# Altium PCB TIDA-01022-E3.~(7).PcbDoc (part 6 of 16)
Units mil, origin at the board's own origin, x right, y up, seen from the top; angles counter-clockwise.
Board outline 6929.13 x 11614.17 mil, 12 copper layers (L1_Top Layer, L2_GND, L3_GND, L4_Signal Layer 1, L5_GND, L6_PWR, L7_GND/PWR, L8_PWR, L9_GND/PWR, L10_Signal Layer 2, L11_GND, L12_Bottom Layer), stack 64.6 mil thick; 1733 components, 993 nets, 5987 pads, 3555 vias.

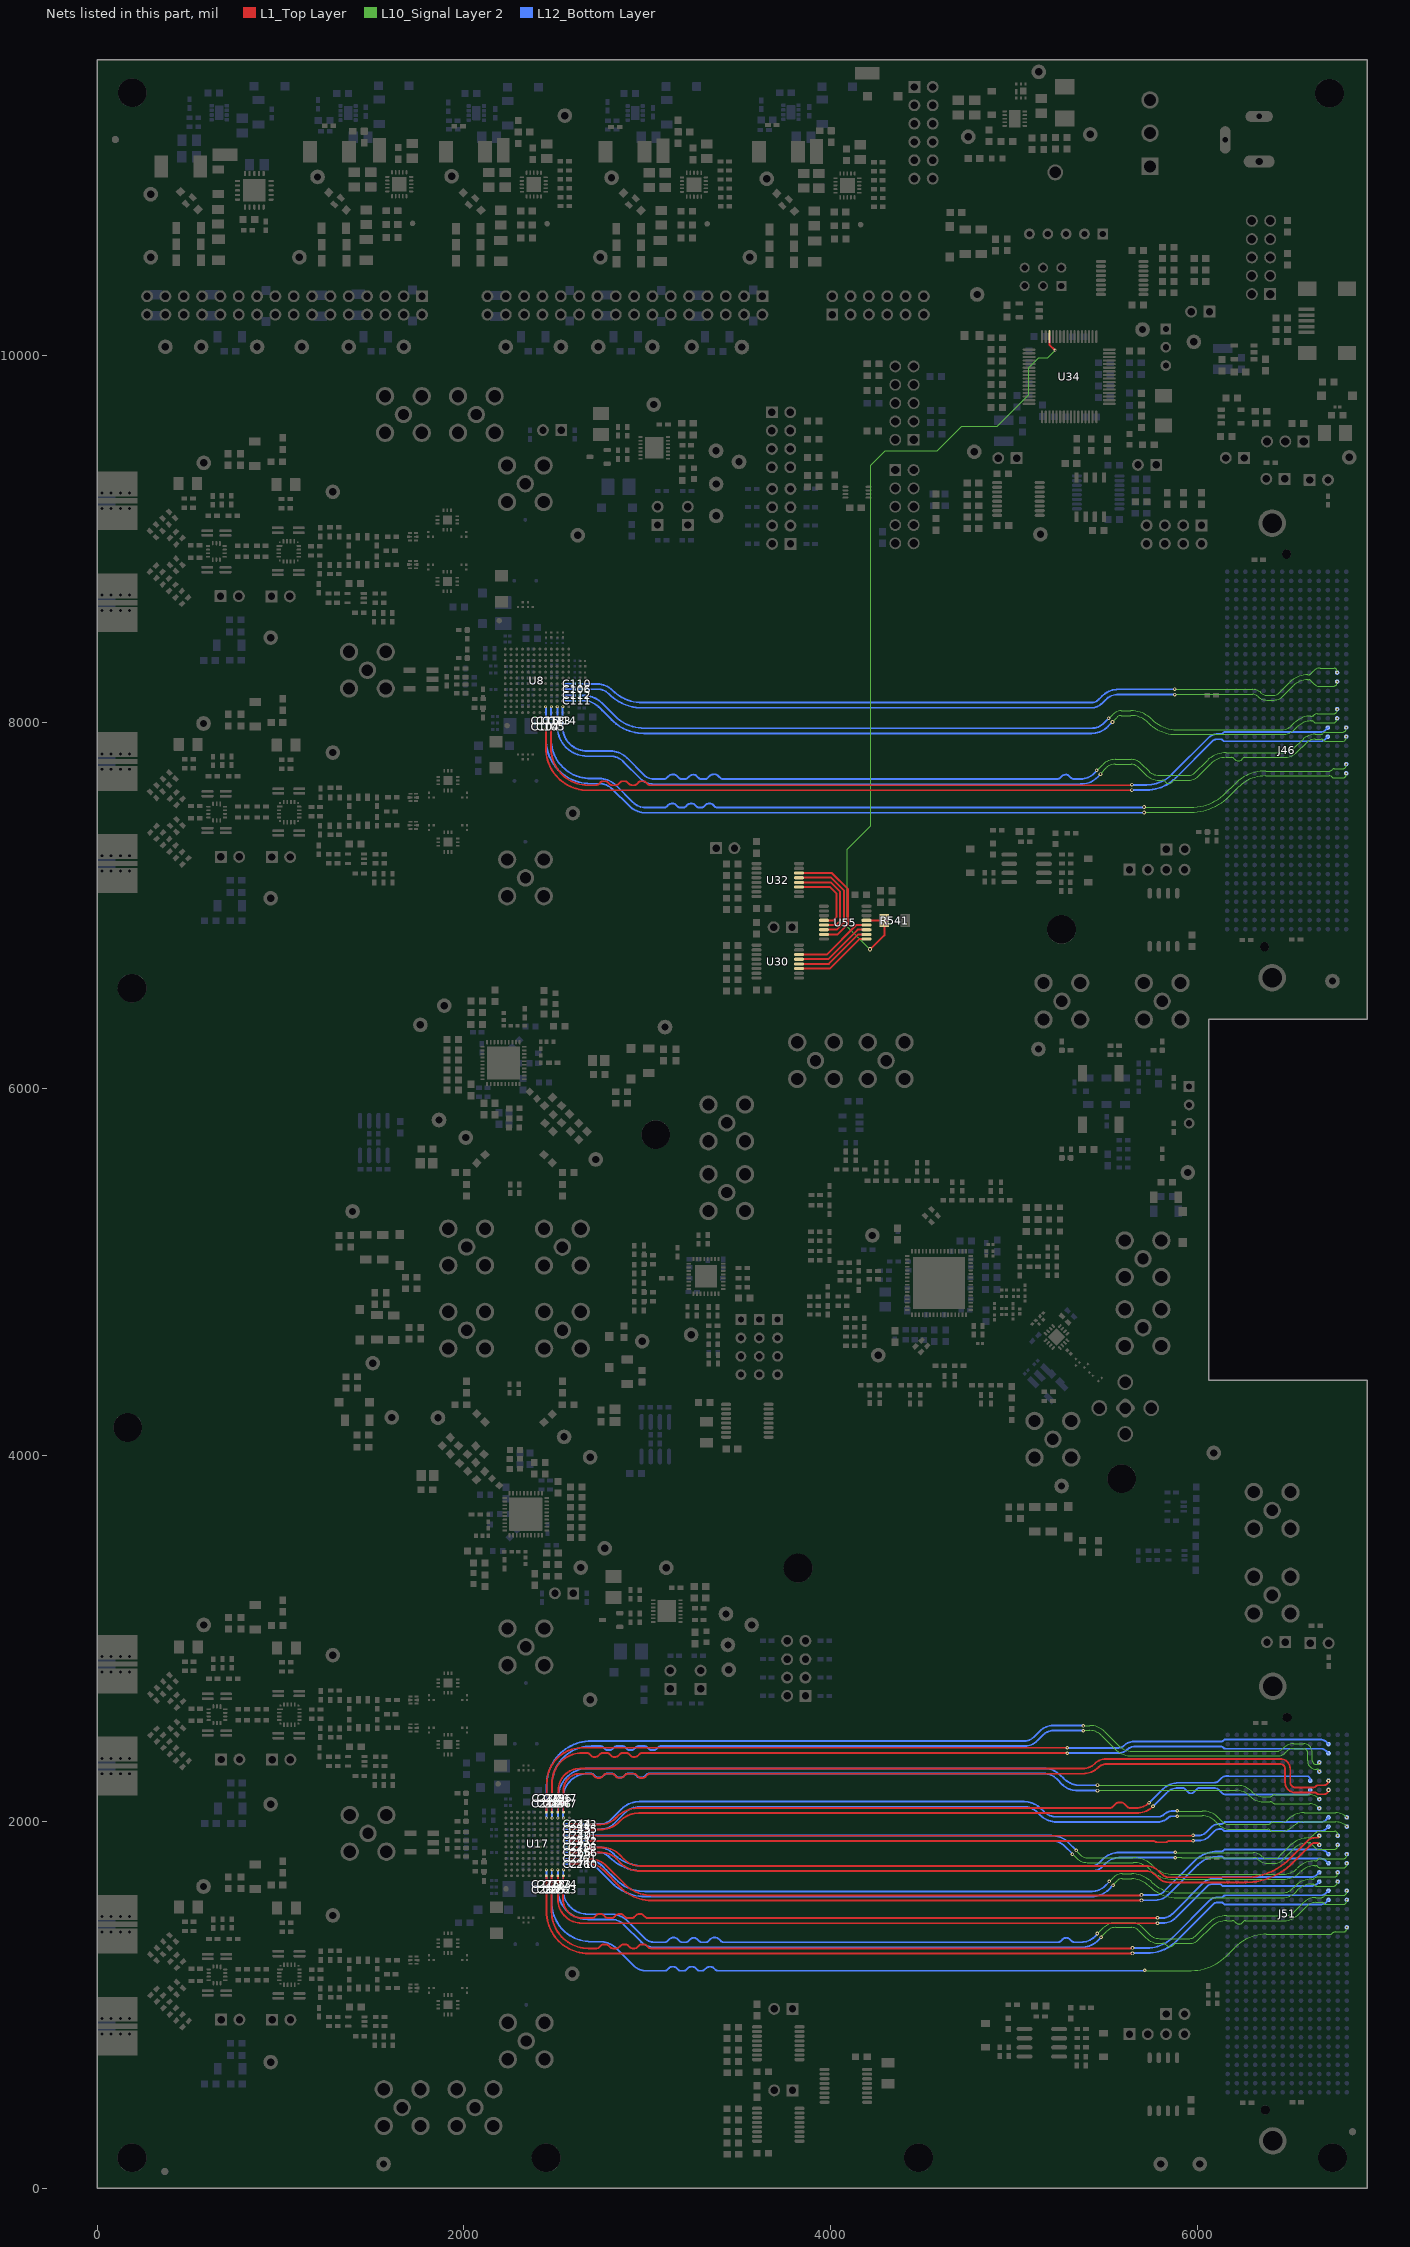
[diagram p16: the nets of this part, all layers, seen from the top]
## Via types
v1: diameter 16, hole 8, L1_Top Layer to L12_Bottom Layer, tented both sides, 1686 vias
v2: diameter 24, hole 12, L1_Top Layer to L12_Bottom Layer, tented both sides, 1590 vias
v3: diameter 20, hole 10, L1_Top Layer to L12_Bottom Layer, 279 vias

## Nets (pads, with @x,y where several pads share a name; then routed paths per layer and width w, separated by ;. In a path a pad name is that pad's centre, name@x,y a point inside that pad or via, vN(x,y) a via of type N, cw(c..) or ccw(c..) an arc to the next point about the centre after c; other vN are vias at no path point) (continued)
ADC1_DB3_M: C105.2 J46.A18 | length 4618.2
  L1_Top Layer w10: C105.2@2475.75,7961.28 2474.75,7960.28 2474.75,7856.77 ccw(c2675.85,7856.77) 2675.85,7655.67 2720.69,7655.67 ccw(c2720.69,7675.64) 2734.81,7661.52 2739.81,7666.52 2744.24,7670.96 cw(c2759.74,7655.46) 2759.74,7677.38 2770.91,7677.38 cw(c2770.91,7658.67) 2784.14,7671.9 2789.51,7666.53 2794.55,7661.48 ccw(c2808.58,7675.51) 2808.58,7655.67 2828.21,7655.67 ccw(c2828.21,7675.64) 2842.33,7661.52 2847.33,7666.52 2851.76,7670.96 cw(c2867.26,7655.46) 2867.26,7677.38 2878.43,7677.38 cw(c2878.43,7658.67) 2891.66,7671.9 2897.03,7666.53 2902.07,7661.48 ccw(c2916.1,7675.51) 2916.1,7655.67 2928.17,7655.67 ccw(c2928.17,7675.64) 2942.29,7661.52 2947.29,7666.52 2951.72,7670.96 cw(c2967.22,7655.46) 2967.22,7677.38 2978.39,7677.38 cw(c2978.39,7658.67) 2991.62,7671.9 2996.99,7666.53 3002.03,7661.48 ccw(c3016.06,7675.51) 3016.06,7655.67 v3@5643.74,7655.67
  L12_Bottom Layer w10: v3(5643.74,7658.4) 5644.74,7657.4 5724.33,7657.4 ccw(c5724.33,7852.38) 5862.19,7714.5 6064.69,7917.01 cw(c6105.74,7875.95) 6105.74,7934.01 6130.02,7934.01 ccw(c6130.02,7944) 6137.09,7936.94 6142.23,7942.08 cw(c6149.3,7935.02) 6149.3,7945.01 6672.48,7945.01 ccw(c6672.48,7982.74) 6699.16,7956.06 J46.A18@6713.11,7970.01
ADC1_DB3_P: C104.2 J46.A19 | length 4616.3
  L1_Top Layer w10: C104.2@2445.75,7961.28 2446.75,7960.28 2446.75,7856.77 ccw(c2675.85,7856.77) 2675.85,7627.67 v3@5641.81,7627.67
  L12_Bottom Layer w10: v3(5643.74,7628.4) 5644.74,7629.4 5724.33,7629.4 ccw(c5724.33,7852.38) 5882,7694.71 6084.49,7897.21 cw(c6105.74,7875.95) 6105.74,7906.01 6130.02,7906.01 cw(c6130.02,7896.02) 6137.09,7903.08 6142.23,7897.94 ccw(c6149.3,7905) 6149.3,7895.01 6669.06,7895.01 ccw(c6669.06,7941) 6701.58,7908.48 J46.A19@6713.11,7920.01
ADC1_DB4+: C106.1 U8.H11 | length 65.1
  L12_Bottom Layer w10: v1(2539.9,8177.85) 2541.65,8179.6 2602.91,8179.6 C106.1@2603.9,8178.61
ADC1_DB4-: C110.1 U8.G11 | length 65.1
  L12_Bottom Layer w10: v1(2539.9,8209.35) 2541.65,8207.6 2602.9,8207.6 C110.1@2603.9,8208.6
ADC1_DB4_M: C110.2 J46.Z12 | length 4261.4
  L10_Signal Layer 2 w6.3: v3(5877.5,8179.62) 5879.42,8177.7 6302.86,8177.7 cw(c6302.86,8111.32) 6349.78,8158.27 ccw(c6378.98,8187.44) 6378.96,8146.17 6418.51,8146.17 ccw(c6418.51,8184.8) 6445.83,8157.49 6505.46,8217.12 cw(c6603.86,8118.72) 6603.86,8257.88 6609.01,8257.88 ccw(c6609.01,8268.6) 6616.59,8261.02 6635,8279.43 cw(c6671.24,8243.2) 6671.24,8294.44 6746.74,8294.44 cw(c6746.74,8278.07) 6763.11,8278.07 v1(6763.11,8270.01)
  L12_Bottom Layer w10: C110.2@2629.88,8208.6 2631.11,8207.37 2727.5,8207.37 cw(c2727.49,8090.77) 2809.93,8173.22 ccw(c2972.65,8335.93) 2972.65,8105.82 4845.67,8105.82 ; 4845.68,8105.82 4887.67,8105.82 ; 4887.67,8105.82 5403.67,8105.82 5424.45,8105.82 ccw(c5424.45,8154.33) 5458.75,8120.03 ccw(c5416.88,8174.18) 5465.28,8125.78 5480.84,8141.34 cw(c5570.85,8051.33) 5570.85,8178.62 5876.5,8178.62 v3(5877.5,8179.62)
ADC1_DB4_P: C106.2 J46.Z13 | length 4262.5
  L10_Signal Layer 2 w6.3: v3(5877.5,8149.62) 5879.18,8151.3 6302.85,8151.3 cw(c6302.85,8111.32) 6331.12,8139.59 ccw(c6378.97,8187.44) 6378.97,8119.77 6418.51,8119.77 ccw(c6418.51,8184.81) 6464.5,8138.82 6524.13,8198.45 cw(c6603.87,8118.72) 6603.87,8231.48 6609.01,8231.48 cw(c6609.01,8219.94) 6617.17,8228.1 6639.06,8206.2 ccw(c6664.59,8231.74) 6664.59,8195.63 6745.03,8195.65 ccw(c6745.03,8213.73) 6763.11,8213.73 v1(6763.11,8220.01)
  L12_Bottom Layer w10: C106.2@2629.88,8178.61 2630.64,8179.37 2727.49,8179.37 cw(c2727.48,8090.77) 2790.13,8153.42 ccw(c2972.64,8335.93) 2972.64,8077.82 4887.67,8077.82 ; 4887.67,8077.82 5403.67,8077.82 5424.45,8077.82 ccw(c5424.45,8154.33) 5477.24,8098.95 ; 5478.55,8100.23 cw(c5424.45,8154.33) 5477.24,8098.95 ; v3(5877.5,8149.62) 5876.5,8150.62 5570.85,8150.62 ccw(c5570.85,8051.33) 5500.64,8121.54 5485.08,8105.98 cw(c5416.88,8174.18) 5477.24,8098.95
ADC1_DB5+: C111.1 U8.K11 | length 65.1
  L12_Bottom Layer w10: v1(2539.9,8114.86) 2541.65,8116.6 2602.91,8116.6 C111.1@2603.9,8115.61
ADC1_DB5-: C112.1 U8.J11 | length 65.1
  L12_Bottom Layer w10: v1(2539.9,8146.35) 2541.65,8144.6 2602.9,8144.6 C112.1@2603.9,8145.6
ADC1_DB5_M: C112.2 J46.Z16 | length 4295.2
  L10_Signal Layer 2 w6.3: v3(5516.96,8021.06) 5519.5,8021.06 5541.59,8043.15 cw(c5586.84,7997.9) 5586.83,8061.89 5638.45,8061.89 cw(c5638.48,7900.69) 5752.46,8014.68 ccw(c5887.41,8149.63) 5887.4,7958.78 6462.43,7958.78 ccw(c6462.43,8035.32) 6516.55,7981.2 6530.77,7995.42 cw(c6620.45,7905.73) 6620.45,8032.56 6625.27,8032.56 ccw(c6625.27,8048.57) 6636.59,8037.25 6636.7,8037.36 cw(c6655.17,8018.89) 6655.17,8045.01 6744.96,8045.01 ccw(c6744.96,8063.16) 6763.11,8063.16 v1(6763.11,8070.01)
  L12_Bottom Layer w10: C112.2@2629.88,8145.6 2630.88,8144.6 2652.49,8144.6 cw(c2652.49,8001.01) 2754.02,8102.55 2773.33,8083.24 2813.19,8043.37 2825.12,8031.44 ccw(c2982.5,8188.82) 2982.5,7966.25 4885.07,7966.25 ; 4885.07,7966.26 5422.75,7966.26 ccw(c5422.75,8066.26) 5493.46,7995.55 5515.54,8017.63 ccw(c5512.1,8021.06) v3(5516.96,8021.06)
ADC1_DB5_P: C111.2 J46.Z17 | length 4293.4
  L10_Signal Layer 2 w6.3: v3(5538.18,7999.84) 5538.18,8002.4 5560.26,8024.48 cw(c5586.84,7997.9) 5586.84,8035.49 5638.48,8035.49 cw(c5638.48,7900.69) 5733.79,7996.01 ccw(c5887.41,8149.63) 5887.39,7932.38 6462.43,7932.38 ccw(c6462.43,8035.32) 6535.22,7962.53 6549.44,7976.75 cw(c6620.45,7905.73) 6620.45,8006.16 6625.27,8006.16 cw(c6625.27,7991.36) 6635.74,8001.82 6640.3,7997.26 ccw(c6645.73,8002.69) 6645.73,7995.01 6740.88,7995.01 ccw(c6740.88,8017.24) 6763.11,8017.24 v1(6763.11,8020.01)
  L12_Bottom Layer w10: C111.2@2630.87,8116.6 2652.49,8116.6 cw(c2652.49,8001.01) 2734.22,8082.75 2753.53,8063.44 ; 2753.53,8063.43 2805.32,8011.64 ccw(c2982.5,8188.82) 2982.49,7938.25 4896.66,7938.25 5422.75,7938.26 ccw(c5422.75,8066.26) 5513.26,7975.75 5536.76,7999.25 cw(c5538.18,7997.83) v3(5538.18,7999.84)
ADC1_DB6+: C113.1 U8.L10 | length 65.1
  L12_Bottom Layer w10: v1(2508.4,8083.36) 2510.15,8081.62 2510.15,8020.35 C113.1@2509.16,8019.36
ADC1_DB6-: C114.1 U8.L11 | length 65.1
  L12_Bottom Layer w10: C114.1@2539.15,8019.36 2538.15,8020.36 2538.15,8081.61 v1(2539.9,8083.36)
ADC1_DB6_M: C114.2 J46.Y18 | length 4654.8
  L10_Signal Layer 2 w6.3: v3(5451.47,7737.01) 5454.01,7737.01 5485.04,7768.04 cw(c5552.57,7700.51) 5552.56,7796.01 5640.45,7796.01 cw(c5640.45,7719.77) 5694.36,7773.68 5735.02,7733.02 ccw(c5792.79,7790.79) 5792.79,7709.09 5880.37,7709.09 ; 5880.82,7709.09 5900.73,7709.09 ccw(c5900.6,7836.94) 5908.59,7709.34 5908.63,7709.38 5955.02,7709.38 ccw(c5955.02,7755.29) 5987.49,7722.83 6054.75,7790.09 cw(c6158.44,7686.39) 6158.46,7833.04 6472.07,7833.04 ccw(c6472.06,7911.05) 6527.22,7855.89 6575.47,7904.14 cw(c6644.11,7835.5) 6644.1,7932.57 6674.25,7932.57 ccw(c6674.25,7947.85) 6685.05,7937.04 ; 6686.71,7938.7 cw(c6701.94,7923.47) 6701.94,7945.01 6794.96,7945.01 ccw(c6794.96,7963.16) 6813.11,7963.16 v1(6813.11,7970.01)
  L12_Bottom Layer w10: C114.2@2538.16,7994.37 2537.16,7993.37 2537.16,7976.66 ccw(c2671.95,7976.66) 2671.95,7841.87 2798.71,7841.87 cw(c2798.71,7713.87) 2889.22,7804.38 2982.8,7710.8 ccw(c3035.17,7763.17) 3035.17,7689.11 3092,7689.11 ccw(c3092,7709.08) 3106.12,7694.96 3111.12,7699.96 3115.55,7704.4 cw(c3140.13,7679.81) 3140.13,7714.58 cw(c3140.14,7683.03) 3162.45,7705.34 3167.82,7699.97 3172.86,7694.92 ccw(c3186.89,7708.95) 3186.89,7689.11 3206.36,7689.11 ccw(c3206.36,7709.08) 3220.48,7694.96 3225.48,7699.96 3229.9,7704.39 cw(c3251,7683.3) 3250.99,7713.13 cw(c3251,7686.53) 3269.81,7705.34 3275.18,7699.97 3280.22,7694.92 ccw(c3294.25,7708.95) 3294.25,7689.11 3318.9,7689.11 ccw(c3318.9,7699.13) 3325.98,7692.04 3333.9,7699.96 3338.33,7704.4 cw(c3364.4,7678.33) 3364.4,7715.2 ; 3364.42,7715.2 cw(c3364.42,7681.52) 3388.23,7705.34 3393.6,7699.97 3398.64,7694.92 ccw(c3412.67,7708.95) 3412.67,7689.11 4885.07,7689.11 ; 4885.07,7689.11 4890.87,7689.11 4908.27,7689.11 5238.05,7689.11 5238.05,7689.27 ccw(c5238.05,7709.24) 5252.17,7695.12 5257.17,7700.12 5261.6,7704.56 cw(c5282.68,7683.48) 5282.68,7713.29 cw(c5282.69,7686.69) 5301.5,7705.5 5306.87,7700.13 5311.91,7695.08 ccw(c5325.94,7709.11) 5325.94,7689.27 ; 5324.09,7689.11 5324.24,7689.27 5325.94,7689.27 ; 5327.09,7689.11 5326.93,7689.27 ; v3(5451.47,7737.01) 5451.47,7733.53 5437.82,7719.88 cw(c5363.92,7793.78) 5363.92,7689.27 5326.93,7689.27 ; 5325.94,7689.27 5326.93,7689.27
ADC1_DB6_P: C113.2 J46.Y19 | length 4652.8
  L10_Signal Layer 2 w6.3: v3(5472.69,7715.79) 5472.69,7718.35 5503.71,7749.37 cw(c5552.57,7700.51) 5552.57,7769.61 5640.45,7769.61 cw(c5640.45,7719.77) 5675.69,7755.01 5716.35,7714.35 ccw(c5792.79,7790.8) 5792.79,7682.69 5810.15,7682.69 cw(c5810.15,7663.67) 5823.6,7677.12 5829.51,7671.21 ; 5829.53,7671.21 ccw(c5844.87,7687.11) 5844.85,7665.02 ccw(c5844.86,7694.57) 5865.76,7673.68 5870.49,7678.41 cw(c5880.82,7668.08) 5880.82,7682.69 5900.72,7682.69 ccw(c5900.75,7836.94) 5910.2,7682.98 5955.03,7682.98 ccw(c5955.03,7755.29) 6006.16,7704.16 6073.42,7771.42 cw(c6158.45,7686.39) 6158.45,7806.64 6189.14,7806.64 cw(c6189.14,7787.62) 6202.59,7801.07 6208.5,7795.16 6208.77,7794.9 ccw(c6224.4,7810.52) 6224.4,7788.42 6225.77,7788.42 ccw(c6225.77,7812.01) 6242.45,7795.33 6249.8,7802.68 cw(c6259.36,7793.12) 6259.36,7806.64 6472.06,7806.64 ccw(c6472.06,7911.05) 6545.89,7837.22 6594.14,7885.47 cw(c6644.11,7835.5) 6644.11,7906.17 6675.78,7906.17 cw(c6675.78,7887.53) 6688.96,7900.71 ccw(c6702.72,7914.47) 6702.72,7895.01 6791.29,7895.01 ccw(c6791.29,7916.83) 6813.11,7916.83 v1(6813.11,7920.01)
  L12_Bottom Layer w10: C113.2@2508.17,7994.37 C113.2@2509.16,7993.38 2509.16,7976.66 ccw(c2671.95,7976.66) 2671.95,7813.87 2798.71,7813.87 cw(c2798.71,7713.87) 2869.42,7784.58 2963,7691 ccw(c3035.17,7763.17) 3035.17,7661.11 4874.67,7661.11 ; 4874.68,7661.11 5362.96,7661.11 ; 5363.91,7661.27 ccw(c5363.92,7793.78) 5457.62,7700.08 5471.59,7714.05 v3@5472.69,7714.05
ADC1_DB7+: C115.1 U8.L8 | length 65.1
  L12_Bottom Layer w10: v1(2445.41,8083.36) 2447.16,8081.62 2447.16,8020.35 C115.1@2446.17,8019.36
ADC1_DB7-: C118.1 U8.L9 | length 65.1
  L12_Bottom Layer w10: C118.1@2476.16,8019.36 2475.16,8020.36 2475.16,8081.61 v1(2476.91,8083.36)
ADC1_DB7_M: C118.2 J46.Y22 | length 4730.5
  L10_Signal Layer 2 w6.3: v3(5710.46,7536.14) 5712.26,7534.34 5964.92,7534.34 ccw(c5964.92,7803.56) 6155.29,7613.2 6204.1,7662 cw(c6374.33,7491.77) 6374.32,7732.51 6722.02,7732.51 ccw(c6722.02,7749.55) 6734.07,7737.5 6736.55,7739.98 cw(c6748.7,7727.82) 6748.7,7745.01 6794.96,7745.01 ccw(c6794.96,7763.16) 6813.11,7763.16 v1(6813.11,7770.01)
  L12_Bottom Layer w10: C118.2@2476,7993.99 2475.77,7993.76 2475,7992.99 2475,7906.98 ccw(c2690.2,7906.98) 2690.2,7691.78 2738.8,7691.78 cw(c2738.8,7563.78) 2829.31,7654.29 2921.19,7562.41 ccw(c2991.9,7633.12) 2991.9,7533.12 3092,7533.12 ccw(c3092,7553.09) 3106.12,7538.97 3111.12,7543.97 3115.55,7548.41 cw(c3131.05,7532.91) 3131.05,7554.83 3142.22,7554.83 cw(c3142.22,7536.12) 3155.45,7549.35 3160.82,7543.98 3165.86,7538.93 ccw(c3179.89,7552.96) 3179.89,7533.12 3195.52,7533.12 ccw(c3195.52,7553.09) 3209.64,7538.97 3214.64,7543.97 3219.07,7548.41 cw(c3234.57,7532.91) 3234.57,7554.83 3245.74,7554.83 cw(c3245.74,7536.12) 3258.97,7549.35 3264.34,7543.98 3269.38,7538.93 ccw(c3283.41,7552.96) 3283.41,7533.12 3294.57,7533.12 ccw(c3294.57,7553.09) 3308.69,7538.97 3313.69,7543.97 3318.12,7548.41 cw(c3333.62,7532.91) 3333.62,7554.83 3344.79,7554.83 cw(c3344.79,7536.12) 3358.02,7549.35 3363.39,7543.98 3368.43,7538.93 ccw(c3382.46,7552.96) 3382.46,7533.12 4884.95,7533.12 4885.07,7533.24 5703.47,7533.24 ccw(c5703.47,7543.13) v3(5710.46,7536.14)
ADC1_DB7_P: C115.2 J46.Y23 | length 4728
  L10_Signal Layer 2 w6.3: v3(5710.46,7506.14) 5712.26,7507.94 5964.93,7507.94 ccw(c5964.92,7803.56) 6173.96,7594.53 6222.77,7643.33 cw(c6374.33,7491.77) 6374.33,7706.11 6434.9,7706.11 6662.33,7706.1 6720.74,7706.1 cw(c6720.74,7684.28) 6736.17,7699.71 ccw(c6747.52,7711.06) 6747.52,7695.01 6794.96,7695.01 ccw(c6794.96,7713.16) 6813.11,7713.16 v1(6813.11,7720.01)
  L12_Bottom Layer w10: C115.2@2447,7993 2447,7906.98 ccw(c2690.2,7906.98) 2690.2,7663.78 2738.8,7663.78 cw(c2738.8,7563.78) 2809.51,7634.49 2901.39,7542.61 ccw(c2991.9,7633.12) 2991.9,7505.12 4896.54,7505.12 4896.67,7505.24 v3@5710.46,7505.24
ADC1_NCOA0: U30.3 U55.9 | length 435.1
  L1_Top Layer w11: U30.3@3827.61,6654.83 3996.01,6654.83 4157.12,6815.95 U55.9@4195.96,6815.95
ADC1_NCOA1: U30.4 U55.10 | length 435.1
  L1_Top Layer w11: U30.4@3827.61,6680.42 3990.6,6680.42 4151.71,6841.54 U55.10@4195.96,6841.54
ADC1_NCOB0: U30.5 U55.11 | length 435.1
  L1_Top Layer w11: U30.5@3827.61,6706.01 3986.19,6706.01 4147.3,6867.13 U55.11@4195.96,6867.13
ADC1_NCOB1: U30.6 U55.12 | length 435.1
  L1_Top Layer w11: U30.6@3827.61,6731.61 3978.78,6731.61 4139.89,6892.72 U55.12@4195.96,6892.72
ADC1_OVRA0: U32.3 U55.4 | length 424.5
  L1_Top Layer w11: U32.3@3827.61,7099.54 3997.15,7099.54 4033.43,7063.26 4033.43,6937.08 4014.65,6918.31 U55.4@3963.68,6918.31
ADC1_OVRA1: U32.4 U55.5 | length 502.5
  L1_Top Layer w11: U32.4@3827.61,7125.13 4000.55,7125.13 4052.43,7073.26 4052.43,6915.08 4030.06,6892.72 U55.5@3963.68,6892.72
ADC1_OVRB0: U32.5 U55.6 | length 573.9
  L1_Top Layer w11: U32.5@3827.61,7150.72 4002.96,7150.72 4072.07,7081.62 4072.07,6904.73 4034.47,6867.13 U55.6@3963.68,6867.13
ADC1_OVRB1: U32.6 U55.7 | length 648.3
  L1_Top Layer w11: U32.6@3827.61,7176.31 4007.48,7176.31 4093.68,7090.12 4093.68,6896.33 4038.88,6841.54 U55.7@3963.68,6841.54
ADC1_STS: R541.1 U34.30 U55.13 | length 4473.6
  L1_Top Layer w11: U55.13@4195.96,6918.31 4291.6,6918.31 R541.1@4292.91,6917 4292.91,6835.91 4217,6760 v2(4215,6760) ; U34.30@5193.62,10102.47 5193.62,10059.13 5224.31,10028.44 v1(5225.31,10029.44)
  L10_Signal Layer 2 w6.5: v2(4215,6760) 4091,6884 4091,7306 4218.5,7433.5 4218.5,9400.5 4298,9480 4583,9480 4716,9613 4908,9613 5082,9787 5082,9933 5137,9988 5183.87,9988 v1(5225.31,10029.44)
ADC2_DA0+: C231.1 U17.E12 | length 64.5
  L1_Top Layer w10: U17.E12@2574.72,1926.34 2576.88,1924.18 C231.1@2638.33,1924.18
ADC2_DA0-: C232.1 U17.F12 | length 65.6
  L1_Top Layer w10: U17.F12@2574.72,1894.85 2576.06,1896.18 2638.33,1896.18 C232.1@2639.33,1895.18
ADC2_DA0_M: C232.2 J51.A11 | length 4087.4
  L1_Top Layer w10: C232.2@2666.3,1896.18 5045.6,1896.18 5758.86,1896.19 cw(c5758.86,1874.49) 5768.78,1893.79 ccw(c5780.57,1905.58) 5773.56,1890.45 ccw(c5780.57,1905.58) 5780.57,1888.91 5830.59,1888.91 ccw(c5830.59,1901.72) 5839.66,1892.66 cw(c5848.18,1884.14) 5848.18,1896.19 v3@5977.92,1896.19
  L12_Bottom Layer w10: v3(5977.92,1896.5) 5978.92,1897.5 6009.17,1897.5 ccw(c6009.17,1978.74) 6066.6,1921.28 6096.67,1951.33 cw(c6117.62,1930.39) 6117.61,1960.01 6133.35,1960.01 cw(c6133.35,1950.02) 6140.42,1957.08 6145.56,1951.94 ccw(c6152.63,1959) 6152.63,1949.01 6672.39,1949.01 ccw(c6672.39,1995) 6700.63,1958.71 ccw(c6672.39,1995) 6704.91,1962.48 J51.A11@6716.44,1974.01
ADC2_DA0_P: C231.2 J51.A10 | length 4093.2
  L1_Top Layer w10: C231.2@2664.31,1924.18 5034,1924.18 v3@5972.34,1924.19 ; v3@5972.34,1924.19 ccw(c5972.34,1932.08) v3(5977.92,1926.5) 5975.61,1924.19 v3@5972.34,1924.19
  L12_Bottom Layer w10: v3(5977.92,1926.5) 5978.92,1925.5 6009.17,1925.5 ccw(c6009.17,1978.73) 6046.8,1941.08 6076.87,1971.13 cw(c6117.62,1930.39) 6117.6,1988.01 6133.35,1988.01 ccw(c6133.35,1998) 6140.42,1990.94 6145.56,1996.08 cw(c6152.63,1989.02) 6152.63,1999.01 6675.81,1999.01 ccw(c6675.81,2036.74) 6702.49,2010.06 J51.A10@6716.44,2024.01
ADC2_DA1+: C233.1 U17.C12 | length 64.5
  L1_Top Layer w10: U17.C12@2574.72,1989.33 2576.88,1987.18 C233.1@2638.33,1987.18
ADC2_DA1-: C235.1 U17.D12 | length 65.6
  L1_Top Layer w10: U17.D12@2574.72,1957.84 2576.06,1959.18 2638.33,1959.18 C235.1@2639.33,1958.18
ADC2_DA1_M: C235.2 J51.C7 | length 4073.9
  L1_Top Layer w10: C235.2@2665.31,1958.18 2714.14,1958.17 2745.78,1958.17 ccw(c2745.78,2101.65) 2847.23,2000.19 2852.78,2005.74 cw(c2953.98,1904.54) 2953.98,2047.66 5670.11,2047.66 ccw(c5670.12,2173.78) v3(5759.3,2084.6)
  L12_Bottom Layer w10: v3(5759.3,2084.6) 5832.96,2158.25 cw(c5897.85,2093.37) 5897.84,2185.13 5920.34,2185.13 cw(c5920.34,2167) 5933.16,2179.82 5952.05,2160.93 ccw(c5963.85,2172.75) 5963.84,2156.05 5968.62,2156.04 ccw(c5968.65,2172.68) 5980.41,2160.91 5999.83,2180.33 cw(c6011.42,2168.74) 6011.42,2185.13 6092.11,2185.13 cw(c6092.11,2147.68) 6118.59,2174.16 6134.47,2158.28 ccw(c6157.07,2180.88) 6157.07,2148.92 6170.78,2148.92 6563.35,2149.01 6598.54,2149.01 ccw(c6598.54,2166.91) 6616.44,2166.91 J51.C7@6616.44,2174.01
ADC2_DA1_P: C233.2 J51.C6 | length 4078
  L1_Top Layer w10: C233.2@2664.31,1987.18 ccw(c2666.74,1989.6) 2666.74,1986.17 2714.14,1986.17 2745.78,1986.17 ccw(c2745.78,2101.64) 2827.43,2019.99 2832.98,2025.54 cw(c2953.98,1904.54) 2953.98,2075.66 5523.41,2075.66 ccw(c5523.42,2098.06) 5539.26,2082.22 5555.61,2098.57 cw(c5572.56,2081.62) 5572.56,2105.6 5589.34,2105.6 cw(c5582.26,2079.31) 5601.49,2098.57 5613.54,2086.52 5618.58,2081.47 ccw(c5632.61,2095.5) 5632.61,2075.66 5668.69,2075.66 ccw(c5668.69,2173.79) v3(5738.08,2104.4) cw(c5734.31,2104.4) v3@5736.98,2101.74
  L12_Bottom Layer w10: v3(5738.08,2104.4) 5739.5,2104.4 5813.16,2178.06 cw(c5897.85,2093.37) 5897.83,2213.13 6092.12,2213.13 ccw(c6092.11,2250.58) 6118.59,2224.1 6134.06,2239.57 cw(c6157.07,2216.56) 6157.07,2249.1 6170.78,2249.1 6563.35,2249.01 6598.54,2249.01 cw(c6598.54,2231.11) 6616.44,2231.11 J51.C6@6616.44,2224.01
ADC2_DA2+: C236.1 U17.A10 | length 64.5
  L1_Top Layer w10: U17.A10@2511.73,2052.33 2513.89,2054.48 C236.1@2513.89,2115.93
ADC2_DA2-: C237.1 U17.A11 | length 64.2
  L1_Top Layer w10: C237.1@2541.89,2115.93 2541.89,2053.66 U17.A11@2543.23,2052.33
ADC2_DA2_M: C237.2 J51.A7 | length 4450.3
  L1_Top Layer w10: C237.2@2542.88,2142.9 2542.88,2173.66 cw(c2631.45,2173.66) 2631.45,2262.23 2689.96,2262.23 cw(c2689.96,2242.39) 2703.99,2256.42 2709.03,2251.38 2714.4,2246 ccw(c2730.04,2261.64) 2730.04,2239.52 2736.39,2239.52 ccw(c2736.39,2264.85) 2754.3,2246.94 2758.73,2251.37 2763.73,2256.38 cw(c2777.85,2242.26) 2777.85,2262.23 2806.43,2262.23 cw(c2806.43,2242.39) 2820.46,2256.42 2825.5,2251.38 2830.87,2246 ccw(c2844.1,2259.23) 2844.1,2240.52 2855.27,2240.52 ccw(c2855.27,2262.44) 2870.77,2246.94 ; 2870.77,2246.94 2875.2,2251.37 2880.2,2256.38 cw(c2894.32,2242.26) 2894.32,2262.23 2927.08,2262.23 cw(c2927.08,2242.39) 2941.11,2256.42 2946.15,2251.38 2951.52,2246 ; 2951.52,2246 ccw(c2967.16,2261.64) 2967.16,2239.52 2973.51,2239.52 ccw(c2973.51,2264.85) 2991.42,2246.94 2995.85,2251.37 3000.85,2256.38 cw(c3014.97,2242.26) 3014.97,2262.23 5375.19,2262.23 ccw(c5375.19,2385.53) 5462.38,2298.34 cw(c5503.07,2257.67) 5503.06,2315.2 6453.64,2315.19 cw(c6453.64,2289.1) 6479.73,2289.1 6479.73,2214.59 ccw(c6534.57,2214.59) 6534.57,2159.75 6641.41,2159.75 cw(c6641.4,2146.28) 6650.93,2155.8 ccw(c6663.58,2168.45) 6663.58,2150.56 6692.99,2150.56 ccw(c6692.99,2174.01) v3(6716.44,2174.01)
ADC2_DA2_P: C236.2 J51.A6 | length 4452.2
  L1_Top Layer w10: C236.2@2513.89,2141.91 2514.88,2142.9 2514.88,2173.66 cw(c2631.45,2173.66) 2631.45,2290.23 5375.19,2290.23 ccw(c5375.19,2385.52) 5442.58,2318.14 cw(c5503.07,2257.66) 5503.05,2343.2 6453.64,2343.2 cw(c6453.63,2289.1) 6507.73,2289.1 6507.73,2214.59 ccw(c6534.57,2214.59) 6534.57,2187.75 6631.75,2187.75 ccw(c6631.74,2211.53) 6648.56,2194.72 6648.89,2195.04 cw(c6660.33,2183.6) 6660.33,2199.78 6692.21,2199.78 ccw(c6692.21,2224.01) v3(6716.44,2224.01)
ADC2_DA3+: C238.1 U17.A8 | length 64.5
  L1_Top Layer w10: U17.A8@2448.74,2052.33 2450.9,2054.48 C238.1@2450.9,2115.93
ADC2_DA3-: C239.1 U17.A9 | length 65.6
  L1_Top Layer w10: C239.1@2479.9,2116.93 2478.9,2115.93 2478.9,2053.66 U17.A9@2480.24,2052.33
ADC2_DA3_M: C239.2 J51.A3 | length 4465.4
  L1_Top Layer w10: C239.2@2480.9,2141.91 C239.2@2479.9,2142.91 2479.9,2210.29 cw(c2645.69,2210.29) 2645.69,2376.08 2669.53,2376.08 cw(c2669.53,2356.24) 2683.56,2370.27 2688.6,2365.23 2693.97,2359.85 ccw(c2707.2,2373.08) 2707.2,2354.37 2718.37,2354.37 ccw(c2718.37,2376.29) 2733.87,2360.79 2738.3,2365.22 2743.3,2370.23 cw(c2757.42,2356.11) 2757.42,2376.08 2778.55,2376.08 cw(c2778.55,2356.24) 2792.58,2370.27 2797.62,2365.23 2802.99,2359.85 ccw(c2816.22,2373.08) 2816.22,2354.37 2827.39,2354.37 ccw(c2827.39,2376.29) 2842.89,2360.79 2847.32,2365.22 2852.32,2370.23 cw(c2866.44,2356.11) 2866.44,2376.08 2884.96,2376.08 cw(c2884.96,2356.24) 2898.99,2370.27 2904.03,2365.23 2909.4,2359.85 ccw(c2922.63,2373.08) 2922.63,2354.37 2933.8,2354.37 ccw(c2933.8,2376.29) 2949.3,2360.79 2953.73,2365.22 2958.73,2370.23 cw(c2972.85,2356.11) 2972.85,2376.08 v3@5291.42,2376.08
  L12_Bottom Layer w10: v3(5291.42,2374.18) 5292.42,2375.18 5571.44,2375.18 ccw(c5571.44,2442.78) 5619.24,2394.98 cw(c5655.53,2358.69) 5655.53,2410.01 6133.35,2410.01 cw(c6133.35,2400.02) 6140.42,2407.08 6145.56,2401.94 ccw(c6152.63,2409) 6152.63,2399.01 6672.39,2399.01 cw(c6672.39,2353.02) 6704.91,2385.54 J51.A3@6716.44,2374.01
ADC2_DA3_P: C238.2 J51.A2 | length 4465.7
  L1_Top Layer w10: C238.2@2450.9,2141.91 2451.9,2142.91 2451.9,2210.29 cw(c2645.69,2210.29) 2645.69,2404.08 v3@5291.42,2404.08
  L12_Bottom Layer w10: v3(5291.42,2404.18) 5292.42,2403.18 5571.44,2403.18 ccw(c5571.44,2442.78) 5599.44,2414.78 cw(c5655.53,2358.69) 5655.53,2438.01 6133.35,2438.01 ccw(c6133.35,2448) 6140.42,2440.94 6145.56,2446.08 cw(c6152.63,2439.02) 6152.63,2449.01 6672.39,2449.01 cw(c6672.39,2403.02) 6704.91,2435.54 J51.A2@6716.44,2424.01
ADC2_DA4+: C240.1 U17.E11 | length 65.1
  L12_Bottom Layer w10: v1(2543.23,1926.34) 2544.98,1924.59 2606.23,1924.59 C240.1@2607.23,1925.59
ADC2_DA4-: C241.1 U17.F11 | length 65.1
  L12_Bottom Layer w10: v1(2543.23,1894.85) 2544.98,1896.59 2606.24,1896.59 C241.1@2607.23,1895.6
ADC2_DA4_M: C241.2 J51.Y15 | length 4301.6
  L10_Signal Layer 2 w6.3: v3(5319.08,1822.91) 5321.64,1822.91 5342.75,1801.8 ccw(c5400.38,1859.43) 5400.38,1777.93 5650.17,1777.93 cw(c5650.17,1650.68) 5740.15,1740.66 ccw(c5869.12,1869.63) 5869.12,1687.24 6469.13,1687.24 ccw(c6469.13,1820.2) 6563.14,1726.18 ; 6564.97,1728.01 cw(c6642.16,1650.82) 6642.16,1759.98 6646.57,1759.98 ; v1(6816.44,1774.01) 6816.44,1767.16 cw(c6797.96,1767.16) 6797.96,1748.68 6673.85,1748.68 cw(c6673.85,1770.05) 6658.74,1754.94 ; 6646.57,1759.98 cw(c6646.57,1742.77) 6658.74,1754.94 ; 6646.57,1759.98 cw(c6646.56,1742.77) 6654.3,1758.14 cw(c6646.59,1742.76) 6658.74,1754.95
  L12_Bottom Layer w10: C241.2@2633.21,1895.6 2634.2,1896.59 5206.87,1896.59 cw(c5206.87,1797.27) 5277.1,1867.5 5317.23,1827.37 cw(c5312.78,1822.91) v3(5319.08,1822.91)
ADC2_DA4_P: C240.2 J51.Y14 | length 4288.3
  L10_Signal Layer 2 w6.3: v3(5340.3,1844.13) 5340.3,1841.59 5361.42,1820.47 ccw(c5400.38,1859.43) 5400.37,1804.33 5650.18,1804.33 cw(c5650.18,1650.68) 5758.82,1759.33 ; 5758.82,1759.33 ccw(c5869.12,1869.63) 5869.11,1713.64 6469.12,1713.64 ccw(c6469.12,1820.2) 6544.47,1744.85 ; 6546.3,1746.68 cw(c6642.15,1650.82) 6642.15,1786.38 6646.34,1786.38 ccw(c6646.34,1798.48) 6654.89,1789.92 ; 6655.93,1790.97 6659.58,1794.62 cw(c6670.18,1784.02) 6670.18,1799.01 6798.29,1799.01 ccw(c6798.29,1817.16) 6816.44,1817.16 v1(6816.44,1824.01)
  L12_Bottom Layer w10: C240.2@2633.21,1925.59 2634.21,1924.59 5206.87,1924.59 cw(c5206.87,1797.27) 5296.9,1887.3 5340.07,1844.13 v3(5340.3,1844.13)
ADC2_DA5+: C244.1 U17.C11 | length 65.1
  L12_Bottom Layer w10: v1(2543.23,1989.33) 2544.98,1987.58 2606.23,1987.58 C244.1@2607.23,1988.58
ADC2_DA5-: C245.1 U17.D11 | length 65.1
  L12_Bottom Layer w10: v1(2543.23,1957.84) 2544.98,1959.58 2606.24,1959.58 C245.1@2607.23,1958.59
ADC2_DA5_M: C245.2 J51.Y11 | length 4304
  L10_Signal Layer 2 w6.3: v3(5891.6,2030.45) 5893.4,2032.25 6026.64,2032.25 cw(c6026.64,1927.98) 6100.37,2001.71 6119.06,1983.02 ccw(c6176.06,2040.02) 6176.06,1959.41 6383.9,1959.41 cw(c6383.9,1935.2) 6401.02,1952.32 ccw(c6412.08,1963.38) 6412.08,1947.74 6458.06,1947.74 ccw(c6458.06,2033.68) 6518.83,1972.91 cw(c6581.79,1909.95) 6581.79,1998.99 6756.13,1998.99 cw(c6756.13,1913.7) v1(6816.44,1974.01)
  L12_Bottom Layer w10: C245.2@2633.21,1958.59 2634.2,1959.58 2742.48,1959.58 ccw(c2742.48,2070.99) 2821.26,1992.22 2878.47,2049.42 cw(c2957.13,1970.75) 2957.13,2082 4900,2082 5056.17,2082.01 cw(c5056.17,1982.01) 5126.88,2052.72 5142.93,2036.67 ccw(c5233.44,2127.18) 5233.44,1999.18 5784.79,1999.18 ccw(c5784.79,2081.81) 5843.22,2023.38 cw(c5859.63,2006.97) 5859.63,2030.18 v3@5891.6,2030.18
ADC2_DA5_P: C244.2 J51.Y10 | length 4306.6
  L10_Signal Layer 2 w6.3: v3(5891.6,2060.45) 5893.4,2058.65 6026.65,2058.65 cw(c6026.64,1927.98) 6119.04,2020.38 6137.73,2001.69 ccw(c6176.06,2040.01) 6176.06,1985.81 6384.44,1985.81 ccw(c6384.44,2010.84) 6402.14,1993.14 cw(c6416.21,1979.07) 6416.21,1998.97 6461.63,1998.97 ccw(c6461.63,2049.43) 6497.31,2013.75 cw(c6583.62,1927.44) 6583.62,2049.5 6754.9,2049.5 cw(c6754.9,1962.47) v1(6816.44,2024.01)
  L12_Bottom Layer w10: C244.2@2633.21,1988.58 2634.21,1987.58 2742.48,1987.58 ccw(c2742.48,2070.99) 2801.46,2012.01 2858.67,2069.22 cw(c2957.13,1970.75) 2957.13,2110 4836,2110 5056.17,2110.01 cw(c5056.17,1982.01) 5146.68,2072.52 5162.73,2056.47 ccw(c5233.44,2127.18) 5233.44,2027.18 5784.79,2027.18 ccw(c5784.79,2081.81) 5823.42,2043.18 cw(c5859.63,2006.97) 5859.63,2058.18 5891.6,2058.18 v3(5891.6,2060.45)
ADC2_DA6+: C246.1 U17.B10 | length 65.1
  L12_Bottom Layer w10: v1(2511.73,2020.83) 2512.98,2022.08 2512.98,2084 C246.1@2511.98,2085
ADC2_DA6-: C247.1 U17.B11 | length 65.5
  L12_Bottom Layer w10: C247.1@2541.97,2085 2540.98,2084.01 2540.98,2023.07 v1(2543.23,2020.83)
ADC2_DA6_M: C247.2 J51.B9 | length 4321.8
  L10_Signal Layer 2 w6.3: v3(5456.51,2170.39) 5458.31,2172.19 6212.15,2172.19 cw(c6212.15,2072.19) 6282.86,2142.9 6283.02,2142.74 ccw(c6361.84,2221.56) 6361.84,2110.09 6397.48,2110.09 cw(c6397.48,2087.62) 6413.37,2103.51 ccw(c6426.33,2116.47) 6426.33,2098.14 6614.47,2098.14 cw(c6614.46,2030.93) 6661.99,2078.45 6665.19,2075.25 v1(6666.44,2074.01)
  L12_Bottom Layer w10: C247.2@2541.97,2110.98 2540.97,2111.98 2540.97,2128.69 cw(c2675.76,2128.69) 2675.76,2263.48 2693.35,2263.48 cw(c2693.35,2243.64) 2707.38,2257.67 2712.42,2252.63 ; 2712.42,2252.62 2717.79,2247.25 ccw(c2731.02,2260.48) 2731.02,2241.77 2742.19,2241.77 ccw(c2742.19,2263.69) 2757.69,2248.19 2762.12,2252.62 ; 2762.12,2252.63 2767.12,2257.63 cw(c2781.24,2243.51) 2781.24,2263.48 2806.67,2263.48 cw(c2806.67,2243.64) 2820.7,2257.67 2825.74,2252.63 ; 2825.74,2252.62 2831.11,2247.25 ccw(c2844.34,2260.48) 2844.34,2241.77 2855.51,2241.77 ccw(c2855.51,2263.69) 2871.01,2248.19 2875.44,2252.62 ; 2875.44,2252.63 2880.44,2257.63 cw(c2894.56,2243.51) 2894.56,2263.48 2920.48,2263.48 cw(c2920.48,2243.64) 2934.51,2257.67 2939.55,2252.63 ; 2939.55,2252.62 2944.92,2247.25 ccw(c2958.15,2260.48) 2958.15,2241.77 2969.32,2241.77 ccw(c2969.32,2263.69) 2984.82,2248.19 2989.25,2252.62 ; 2989.25,2252.63 2994.25,2257.63 cw(c3008.37,2243.51) 3008.37,2263.48 4928.59,2263.48 5163.27,2263.49 cw(c5163.27,2163.49) 5233.98,2234.2 5267.5,2200.68 ccw(c5338.21,2271.39) 5338.21,2171.39 5455.51,2171.39 v3(5456.51,2170.39)
ADC2_DA6_P: C246.2 J51.B8 | length 4320.8
  L10_Signal Layer 2 w6.3: v3(5456.51,2200.39) 5458.31,2198.59 6222.86,2198.59 cw(c6222.86,2098.05) 6293.96,2169.14 6301.69,2161.41 ccw(c6361.85,2221.56) 6361.85,2136.49 6396.65,2136.49 ccw(c6396.65,2153.32) 6408.55,2141.42 ; 6408.57,2141.44 cw(c6424.75,2125.26) 6424.75,2148.14 6614.47,2148.14 cw(c6614.46,2080.93) 6661.99,2128.45 6665.19,2125.25 v1(6666.44,2124.01)
  L12_Bottom Layer w10: C246.2@2511.98,2110.98 2512.97,2111.97 2512.97,2128.69 cw(c2675.76,2128.69) 2675.76,2291.48 4916.99,2291.48 5163.27,2291.49 cw(c5163.27,2163.49) 5253.78,2254 5270.9,2236.88 ccw(c5361.41,2327.39) 5361.41,2199.39 5455.51,2199.39 v3(5456.51,2200.39)
ADC2_DA7+: C248.1 U17.B8 | length 62.9
  L12_Bottom Layer w10: v1@2450,2022.09 C248.1@2450,2085
  other v1: 2448.74,2020.83
ADC2_DA7-: C249.1 U17.B9 | length 63.9
  L12_Bottom Layer w10: v1@2479.99,2021.08 C249.1@2479.99,2085
  other v1: 2480.24,2020.83
ADC2_DA7_M: C249.2 J51.B5 | length 4620.3
  L10_Signal Layer 2 w6.3: v3(5378.21,2496.82) 5380.01,2498.62 5414.38,2498.62 cw(c5414.38,2410.19) 5476.91,2472.72 5551.35,2398.26 ccw(c5645.13,2492.05) 5645.15,2359.43 6438.94,2359.43 ccw(c6438.93,2418.33) 6480.58,2376.68 6486.96,2383.06 cw(c6525.88,2344.14) 6525.87,2399.18 6580.74,2399.18 cw(c6580.74,2377.5) 6602.42,2377.5 6602.42,2332.36 ccw(c6647.74,2332.36) 6647.74,2287.04 6653.41,2287.04 cw(c6653.41,2274.01) v1(6666.44,2274.01)
  L12_Bottom Layer w10: C249.2@2479.99,2110.98 2478.99,2111.98 2478.99,2197.99 cw(c2694.19,2197.99) 2694.19,2413.19 2746.15,2413.19 cw(c2746.15,2393.35) 2760.18,2407.38 ; 2760.18,2407.38 2765.22,2402.34 2770.59,2396.96 ccw(c2784.06,2410.43) 2784.06,2391.38 2794.75,2391.38 ccw(c2794.75,2413.64) 2810.49,2397.9 2814.92,2402.33 2819.92,2407.34 ; 2819.92,2407.35 cw(c2834.04,2393.22) 2834.04,2413.19 2864.86,2413.19 cw(c2864.86,2393.35) 2878.89,2407.38 ; 2878.89,2407.38 2883.93,2402.34 2889.3,2396.96 ccw(c2902.55,2410.21) 2902.55,2391.47 2913.68,2391.47 ccw(c2913.68,2413.42) 2929.2,2397.9 2933.63,2402.33 2938.63,2407.34 cw(c2952.75,2393.22) 2952.75,2413.19 2985.81,2413.19 cw(c2985.81,2393.35) 2999.84,2407.38 ; 2999.84,2407.38 3004.88,2402.34 3010.25,2396.96 ccw(c3023.48,2410.19) 3023.48,2391.48 3034.65,2391.48 ccw(c3034.65,2413.4) 3050.15,2397.9 3054.58,2402.33 3059.58,2407.34 cw(c3073.7,2393.22) 3073.7,2413.19 4899.81,2413.19 4900,2413 ; 4900,2413.2 5058.42,2413.2 ccw(c5058.42,2511.26) 5127.75,2441.92 5161.22,2475.38 cw(c5215.39,2421.21) 5215.39,2497.82 v3@5378.21,2497.82
ADC2_DA7_P: C248.2 J51.B4 | length 4619.1
  L10_Signal Layer 2 w6.3: v3(5378.2,2523.22) 5380,2525.02 5414.37,2525.02 cw(c5414.39,2410.19) 5495.58,2491.39 5570.03,2416.94 ccw(c5645.14,2492.05) 5645.14,2385.83 6438.93,2385.83 ccw(c6438.93,2418.33) 6461.91,2395.35 6468.28,2401.73 cw(c6525.87,2344.13) 6525.87,2425.58 6580.74,2425.58 cw(c6580.74,2377.5) 6628.82,2377.5 6628.82,2332.36 ccw(c6647.74,2332.36) 6647.74,2313.44 6659.71,2313.44 ccw(c6659.71,2320.17) 6666.44,2320.17 v1(6666.44,2324.01)
  L12_Bottom Layer w10: C248.2@2450.99,2111.97 2450.99,2197.99 cw(c2694.19,2197.99) 2694.19,2441.19 4850,2441.19 5058.42,2441.2 ccw(c5058.42,2511.26) 5107.95,2461.72 5141.42,2495.18 cw(c5215.39,2421.21) 5215.39,2525.82 v3@5378,2525.82
ADC2_DB0+: C256.1 U17.H12 | length 65.6
  L1_Top Layer w10: U17.H12@2574.72,1831.85 2576.06,1833.19 2638.33,1833.19 C256.1@2639.33,1832.19
ADC2_DB0-: C258.1 U17.G12 | length 64.5
  L1_Top Layer w10: U17.G12@2574.72,1863.35 2576.88,1861.19 C258.1@2638.33,1861.19
ADC2_DB0_M: C258.2 J51.B12 | length 4132.3
  L1_Top Layer w10: C258.2@2664.31,1861.19 ccw(c2666.73,1863.61) 2666.73,1860.19 2753.07,1860.19 cw(c2753.07,1724.54) 2848.98,1820.47 2875.04,1794.42 ccw(c2958.79,1878.17) 2958.78,1759.73 5720.13,1759.73 cw(c5720.13,1660.3) 5789.24,1731.79 ; 5790.44,1730.61 ccw(c5720.13,1660.3) 5789.24,1731.79 ; v3(6666.44,1924.01) cw(c6655.44,1924.01) 6655.44,1913.01 6642.06,1913.01 ccw(c6642.06,1857.7) 6602.95,1896.81 6502.4,1796.26 cw(c6263.88,2034.78) 6263.88,1697.46 5847.96,1697.46 cw(c5847.96,1754) 5807.98,1714.02 5799,1723 ccw(c5710.32,1634.32) 5789.24,1731.79
ADC2_DB0_P: C256.2 J51.B13 | length 4129.3
  L1_Top Layer w10: C256.2@2665.31,1832.19 2753.08,1832.19 cw(c2753.07,1724.54) 2829.19,1800.66 2855.24,1774.62 ccw(c2958.79,1878.17) 2958.79,1731.73 5720.13,1731.73 cw(c5720.13,1660.3) 5770.64,1710.81 cw(c5710.32,1634.32) 5779.2,1703.2 5788.18,1694.22 ccw(c5847.96,1754) 5847.96,1669.46 6263.88,1669.46 ccw(c6263.88,2034.78) 6522.2,1776.46 6622.75,1877.01 cw(c6642.06,1857.71) 6642.06,1885.01 6655.44,1885.01 cw(c6655.44,1874.01) v3(6666.44,1874.01)
ADC2_DB1+: C260.1 U17.K12 | length 65.6
  L1_Top Layer w10: U17.K12@2574.72,1768.86 2576.06,1770.2 2638.33,1770.2 C260.1@2639.33,1769.2
ADC2_DB1-: C261.1 U17.J12 | length 64.5
  L1_Top Layer w10: U17.J12@2574.72,1800.36 2576.88,1798.2 C261.1@2638.33,1798.2
ADC2_DB1_M: C261.2 J51.A14 | length 4220.7
  L1_Top Layer w10: C261.2@2664.31,1798.2 ccw(c2666.73,1800.61) 2666.73,1797.2 2687.28,1797.2 cw(c2687.28,1671.55) 2776.13,1760.4 2878.31,1658.23 ccw(c3021.61,1801.52) 3021.61,1598.87 5031,1598.87 v3@5695.98,1598.88
  L12_Bottom Layer w10: v3(5695.98,1601.19) 5696.98,1600.19 5771.42,1600.19 ccw(c5771.42,1667.17) 5818.78,1619.81 5983.93,1784.96 cw(c6112.01,1656.88) 6112.01,1838.01 6133.35,1838.01 ccw(c6133.35,1848) 6140.42,1840.94 6145.56,1846.08 cw(c6152.63,1839.02) 6152.63,1849.01 6672.39,1849.01 cw(c6672.39,1803.02) 6704.91,1835.54 J51.A14@6716.44,1824.01
ADC2_DB1_P: C260.2 J51.A15 | length 4219.8
  L1_Top Layer w10: C260.2@2665.31,1769.2 2687.28,1769.2 cw(c2687.28,1671.55) 2756.33,1740.6 2858.51,1638.43 ccw(c3021.61,1801.52) 3021.6,1570.87 5042.6,1570.87 v3@5695.98,1570.88
  L12_Bottom Layer w10: v3(5695.98,1571.19) 5696.98,1572.19 5771.42,1572.19 ccw(c5771.42,1667.17) 5838.58,1600.01 6003.73,1765.16 cw(c6112.01,1656.88) 6112.01,1810.01 6133.35,1810.01 cw(c6133.35,1800.02) 6140.42,1807.08 6145.56,1801.94 ccw(c6152.63,1809) 6152.63,1799.01 6675.81,1799.01 cw(c6675.81,1761.28) 6702.49,1787.96 J51.A15@6716.44,1774.01
ADC2_DB2+: C262.1 U17.M10 | length 65.6
  L1_Top Layer w10: U17.M10@2511.73,1705.87 2513.07,1704.53 2513.07,1642.27 C262.1@2512.07,1641.27
ADC2_DB2-: C263.1 U17.M11 | length 64.5
  L1_Top Layer w10: C263.1@2541.07,1642.27 2541.07,1703.71 U17.M11@2543.23,1705.87
ADC2_DB2_M: C263.2 J51.B16 | length 4363.5
  L1_Top Layer w10: C263.2@2541.07,1616.28 2540.08,1615.29 2540.08,1577.83 ccw(c2643.06,1577.83) 2643.06,1474.85 2697.69,1474.85 ccw(c2697.69,1494.82) 2711.81,1480.7 2716.81,1485.7 2721.24,1490.14 cw(c2736.74,1474.64) 2736.74,1496.56 2747.91,1496.56 cw(c2747.91,1477.85) 2761.14,1491.08 2766.51,1485.71 2771.55,1480.66 ccw(c2785.58,1494.69) 2785.58,1474.85 2805.5,1474.85 ccw(c2805.5,1494.82) 2819.62,1480.7 2824.62,1485.7 2829.05,1490.14 cw(c2844.55,1474.64) 2844.55,1496.56 2855.72,1496.56 cw(c2855.72,1477.85) 2868.95,1491.08 2874.32,1485.71 2879.36,1480.66 ccw(c2893.39,1494.69) 2893.39,1474.85 2914.95,1474.85 ccw(c2914.95,1494.82) 2929.07,1480.7 2934.07,1485.7 2938.5,1490.14 cw(c2954,1474.64) 2954,1496.56 2965.17,1496.56 cw(c2965.17,1477.85) 2978.4,1491.08 2983.77,1485.71 2988.81,1480.66 ccw(c3002.84,1494.69) 3002.84,1474.85 5776.7,1474.85 ccw(c5776.7,1484.17) v3@5783.29,1477.58
  L12_Bottom Layer w10: v3(5783.29,1476.58) 5784.29,1475.58 5813.23,1475.58 ccw(c5813.22,1546.41) 5863.31,1496.33 6037.08,1670.09 cw(c6080.35,1626.81) 6080.37,1688.01 6123.35,1688.01 ccw(c6123.35,1698) 6130.42,1690.94 6135.56,1696.08 cw(c6142.63,1689.02) 6142.63,1699.01 6625.81,1699.01 ccw(c6625.81,1736.74) 6652.49,1710.06 J51.B16@6666.44,1724.01
ADC2_DB2_P: C262.2 J51.B17 | length 4363.2
  L1_Top Layer w10: C262.2@2511.08,1616.28 C262.2@2512.07,1615.28 ; C262.2@2512.07,1615.28 2512.08,1577.83 ccw(c2643.06,1577.83) 2643.06,1446.85 5779.94,1446.85 cw(c5779.94,1442.51) v3@5783.01,1445.58 ; v3@5783.01,1446.86 v3(5783.29,1446.58)
  L12_Bottom Layer w10: v3(5783.29,1446.58) 5784.29,1447.58 5813.23,1447.58 ccw(c5813.23,1546.42) 5883.12,1476.53 6056.88,1650.29 cw(c6080.35,1626.81) 6080.35,1660.01 6123.35,1660.01 cw(c6123.35,1650.02) 6130.42,1657.08 6135.56,1651.94 ccw(c6142.63,1659) 6142.63,1649.01 6622.39,1649.01 ccw(c6622.39,1695) 6654.91,1662.48 J51.B17@6666.44,1674.01
ADC2_DB3+: C264.1 U17.M8 | length 65.6
  L1_Top Layer w10: U17.M8@2448.74,1705.87 2450.08,1704.53 2450.08,1642.27 C264.1@2449.08,1641.27
ADC2_DB3-: C265.1 U17.M9 | length 64.5
  L1_Top Layer w10: C265.1@2478.08,1642.27 2478.08,1703.71 U17.M9@2480.24,1705.87
ADC2_DB3_M: C265.2 J51.A18 | length 4619.2
  L1_Top Layer w10: C265.2@2479.08,1615.28 2478.08,1614.28 2478.08,1510.77 ccw(c2679.18,1510.77) 2679.18,1309.67 2724.02,1309.67 ccw(c2724.02,1329.64) 2738.14,1315.52 2743.14,1320.52 2747.57,1324.96 cw(c2763.07,1309.46) 2763.07,1331.38 2774.24,1331.38 cw(c2774.24,1312.67) 2787.47,1325.9 2792.84,1320.53 2797.88,1315.48 ; 2797.88,1315.48 ccw(c2811.91,1329.51) 2811.91,1309.67 2831.54,1309.67 ccw(c2831.54,1329.64) 2845.66,1315.52 2850.66,1320.52 2855.09,1324.96 cw(c2870.59,1309.46) 2870.59,1331.38 2881.76,1331.38 cw(c2881.76,1312.67) 2894.99,1325.9 2900.36,1320.53 2905.4,1315.48 ; 2905.4,1315.48 ccw(c2919.43,1329.51) 2919.43,1309.67 2931.5,1309.67 ccw(c2931.5,1329.64) 2945.62,1315.52 2950.62,1320.52 2955.05,1324.96 cw(c2970.55,1309.46) 2970.55,1331.38 2981.72,1331.38 cw(c2981.72,1312.67) 2994.95,1325.9 3000.32,1320.53 3005.36,1315.48 ; 3005.36,1315.48 ccw(c3019.39,1329.51) 3019.39,1309.67 5638.06,1309.67 ccw(c5638.06,1322.41) v3@5647.07,1313.4
  L12_Bottom Layer w10: v3(5647.07,1312.4) 5648.07,1311.4 5727.66,1311.4 ccw(c5727.66,1506.38) 5865.52,1368.5 6068.02,1571.01 cw(c6109.07,1529.95) 6109.07,1588.01 6133.35,1588.01 ccw(c6133.35,1598) 6140.42,1590.94 6145.56,1596.08 cw(c6152.63,1589.02) 6152.63,1599.01 6675.81,1599.01 ccw(c6675.81,1636.74) 6702.49,1610.06 J51.A18@6716.44,1624.01
ADC2_DB3_P: C264.2 J51.A19 | length 4618.5
  L1_Top Layer w10: C264.2@2449.08,1615.28 2450.08,1614.28 2450.08,1510.77 ccw(c2679.18,1510.77) 2679.18,1281.67 5645.14,1281.67 cw(c5645.14,1278.95) v3@5647.07,1280.87
  L12_Bottom Layer w10: v3(5647.07,1282.4) 5648.07,1283.4 5727.66,1283.4 ccw(c5727.66,1506.38) 5885.33,1348.71 6087.82,1551.21 cw(c6109.07,1529.95) 6109.07,1560.01 ; 6109.08,1560.01 6133.35,1560.01 cw(c6133.35,1550.02) 6140.42,1557.08 6145.56,1551.94 ccw(c6152.63,1559) 6152.63,1549.01 6672.39,1549.01 ccw(c6672.39,1595) 6704.91,1562.48 J51.A19@6716.44,1574.01
ADC2_DB4+: C266.1 U17.H11 | length 65.1
  L12_Bottom Layer w10: v1(2543.23,1831.85) 2544.98,1833.6 2606.24,1833.6 C266.1@2607.23,1832.61
ADC2_DB4-: C270.1 U17.G11 | length 65.1
  L12_Bottom Layer w10: v1(2543.23,1863.35) 2544.98,1861.6 2606.23,1861.6 C270.1@2607.23,1862.6
ADC2_DB4_M: C270.2 J51.Z12 | length 4261.4
  L10_Signal Layer 2 w6.3: v3(5880.83,1833.62) 5882.63,1831.82 5927.94,1831.82 5928.06,1831.7 6306.19,1831.7 cw(c6306.19,1765.32) 6353.12,1812.27 ccw(c6382.31,1841.44) 6382.29,1800.17 6421.84,1800.17 ccw(c6421.84,1838.8) 6449.16,1811.49 6508.79,1871.12 cw(c6607.19,1772.72) 6607.19,1911.88 6612.34,1911.88 ccw(c6612.34,1922.6) 6619.92,1915.02 6638.33,1933.43 cw(c6674.57,1897.2) 6674.57,1948.44 6750.07,1948.44 cw(c6750.07,1932.07) 6766.44,1932.07 v1(6766.44,1924.01)
  L12_Bottom Layer w10: C270.2@2633.21,1862.6 2634.44,1861.37 2730.83,1861.37 cw(c2730.82,1744.77) 2813.26,1827.23 ccw(c2975.98,1989.93) 2975.98,1759.82 4849,1759.82 4891,1759.83 5407,1759.82 5427.78,1759.83 ccw(c5427.78,1808.33) 5462.08,1774.03 ccw(c5420.21,1828.18) 5468.61,1779.78 5484.17,1795.34 ; 5484.17,1795.34 cw(c5574.18,1705.33) 5574.18,1832.62 5879.83,1832.62 v3(5880.83,1833.62)
ADC2_DB4_P: C266.2 J51.Z13 | length 4262.4
  L10_Signal Layer 2 w6.3: v3(5880.83,1803.62) 5882.63,1805.42 5917,1805.42 ; 5917.12,1805.3 6306.18,1805.3 cw(c6306.18,1765.32) 6334.45,1793.59 ccw(c6382.3,1841.44) 6382.3,1773.77 6421.84,1773.77 ccw(c6421.84,1838.81) 6467.83,1792.82 6527.46,1852.45 cw(c6607.2,1772.72) 6607.2,1885.48 6612.34,1885.48 cw(c6612.34,1873.94) 6620.5,1882.1 6642.39,1860.2 ccw(c6667.92,1885.74) 6667.92,1849.63 6748.36,1849.65 ccw(c6748.36,1867.73) 6766.44,1867.73 v1(6766.44,1874.01)
  L12_Bottom Layer w10: C266.2@2633.21,1832.61 2633.97,1833.37 2730.82,1833.37 cw(c2730.81,1744.77) 2793.46,1807.42 ccw(c2975.97,1989.93) 2975.97,1731.82 4891,1731.82 5407,1731.82 5427.78,1731.83 ccw(c5427.78,1808.33) 5480.57,1752.95 ; 5481.88,1754.23 cw(c5427.78,1808.33) 5480.57,1752.95 ; v3(5880.83,1803.62) 5879.83,1804.62 5574.18,1804.62 ccw(c5574.18,1705.33) 5503.97,1775.54 5488.41,1759.98 cw(c5420.21,1828.18) 5480.57,1752.95
ADC2_DB5+: C271.1 U17.K11 | length 65.1
  L12_Bottom Layer w10: v1@2543.23,1768.86 2544.98,1770.61 2606.24,1770.61 C271.1@2607.23,1769.62
  other v1: 2543.23,1768.86
ADC2_DB5-: C272.1 U17.J11 | length 65.1
  L12_Bottom Layer w10: v1(2543.23,1800.36) 2544.98,1798.61 2606.23,1798.61 C272.1@2607.23,1799.61
ADC2_DB5_M: C272.2 J51.Z16 | length 4295.2
  L10_Signal Layer 2 w6.3: v3(5520.29,1675.06) 5522.83,1675.06 5544.92,1697.15 ; 5544.92,1697.15 cw(c5590.17,1651.9) 5590.16,1715.89 5641.78,1715.89 cw(c5641.81,1554.69) 5755.79,1668.68 ccw(c5890.74,1803.63) 5890.73,1612.78 6465.76,1612.78 ccw(c6465.76,1689.32) 6519.88,1635.2 6534.1,1649.42 cw(c6623.78,1559.73) 6623.78,1686.56 6628.6,1686.56 ccw(c6628.6,1702.57) 6639.92,1691.25 6640.03,1691.36 cw(c6658.5,1672.89) 6658.5,1699.01 6748.29,1699.01 ccw(c6748.29,1717.16) 6766.44,1717.16 v1(6766.44,1724.01)
  L12_Bottom Layer w10: C272.2@2633.21,1799.61 2634.21,1798.61 2655.82,1798.61 cw(c2655.82,1655.02) 2757.35,1756.56 2776.66,1737.25 2816.52,1697.38 2828.45,1685.45 ccw(c2985.83,1842.83) 2985.83,1620.26 4888.4,1620.26 5426.08,1620.26 ccw(c5426.08,1720.26) 5496.79,1649.55 v3@5518.87,1671.63 ; v3@5518.87,1671.64 ccw(c5515.43,1675.06) v3(5520.29,1675.06)
ADC2_DB5_P: C271.2 J51.Z17 | length 4293.4
  L10_Signal Layer 2 w6.3: v3(5541.51,1653.84) 5541.51,1656.4 5563.59,1678.48 cw(c5590.17,1651.9) 5590.17,1689.49 5641.81,1689.49 cw(c5641.81,1554.69) 5737.12,1650.02 ; 5737.12,1650.01 ccw(c5890.74,1803.63) 5890.72,1586.38 6465.76,1586.38 ccw(c6465.76,1689.32) 6538.55,1616.53 6552.77,1630.75 cw(c6623.78,1559.73) 6623.78,1660.16 6628.6,1660.16 cw(c6628.6,1645.36) 6639.07,1655.82 6643.63,1651.26 ccw(c6649.06,1656.69) 6649.06,1649.01 6744.21,1649.01 ccw(c6744.21,1671.24) 6766.44,1671.24 v1(6766.44,1674.01)
  L12_Bottom Layer w10: C271.2@2634.2,1770.61 2655.82,1770.61 cw(c2655.82,1655.02) 2737.55,1736.76 2756.86,1717.45 2808.65,1665.65 ccw(c2985.83,1842.83) 2985.82,1592.26 4899.99,1592.26 5426.08,1592.26 ccw(c5426.08,1720.26) 5516.59,1629.75 5540.09,1653.25 cw(c5541.51,1651.83) v3(5541.51,1653.84)
ADC2_DB6+: C273.1 U17.L10 | length 65.1
  L12_Bottom Layer w10: v1(2511.73,1737.37) 2513.48,1735.63 2513.48,1674.36 C273.1@2512.49,1673.37
ADC2_DB6-: C274.1 U17.L11 | length 65.1
  L12_Bottom Layer w10: C274.1@2542.48,1673.37 2541.48,1674.37 2541.48,1735.62 v1(2543.23,1737.37)
ADC2_DB6_M: C274.2 J51.Y18 | length 4654.8
  L10_Signal Layer 2 w6.3: v3(5454.8,1391.01) 5457.34,1391.01 5488.37,1422.04 cw(c5555.9,1354.51) 5555.89,1450.01 5643.78,1450.01 cw(c5643.78,1373.77) 5697.69,1427.68 5738.35,1387.02 ccw(c5796.12,1444.79) 5796.12,1363.09 5883.7,1363.09 ; 5884.15,1363.09 5904.06,1363.09 ccw(c5903.93,1490.94) 5911.92,1363.34 5911.96,1363.38 5958.35,1363.38 ccw(c5958.35,1409.29) 5990.82,1376.83 ; 5990.82,1376.83 6058.08,1444.09 cw(c6161.77,1340.39) 6161.79,1487.04 6475.4,1487.04 ccw(c6475.39,1565.05) 6530.55,1509.89 6578.8,1558.14 cw(c6647.44,1489.5) 6647.43,1586.57 6677.58,1586.57 ccw(c6677.58,1601.85) 6688.38,1591.04 ; 6690.04,1592.7 cw(c6705.27,1577.47) 6705.27,1599.01 6798.29,1599.01 ccw(c6798.29,1617.16) 6816.44,1617.16 v1(6816.44,1624.01)
  L12_Bottom Layer w10: C274.2@2541.49,1648.37 2540.49,1647.37 2540.49,1630.66 ccw(c2675.28,1630.66) 2675.28,1495.87 2802.04,1495.87 cw(c2802.04,1367.87) 2892.55,1458.38 2986.13,1364.8 ccw(c3038.5,1417.17) 3038.5,1343.11 3095.33,1343.11 ccw(c3095.33,1363.08) 3109.45,1348.96 3114.45,1353.96 3118.88,1358.4 cw(c3143.46,1333.81) 3143.46,1368.58 ; 3143.47,1368.58 cw(c3143.47,1337.03) 3165.78,1359.34 3171.15,1353.97 3176.19,1348.92 ccw(c3190.22,1362.95) 3190.22,1343.11 3209.69,1343.11 ccw(c3209.69,1363.08) 3223.81,1348.96 3228.81,1353.96 3233.23,1358.39 cw(c3254.33,1337.3) 3254.32,1367.13 cw(c3254.33,1340.53) 3273.14,1359.34 3278.51,1353.97 3283.55,1348.92 ccw(c3297.58,1362.95) 3297.58,1343.11 3322.23,1343.11 ccw(c3322.23,1353.13) 3329.31,1346.04 3337.23,1353.96 3341.66,1358.4 cw(c3367.73,1332.33) 3367.73,1369.2 cw(c3367.75,1335.52) 3391.56,1359.34 3396.93,1353.97 3401.97,1348.92 ccw(c3416,1362.95) 3416,1343.11 4888.4,1343.11 4894.2,1343.12 4911.6,1343.12 5241.38,1343.12 5241.38,1343.27 ccw(c5241.38,1363.24) 5255.5,1349.12 5260.5,1354.12 5264.93,1358.56 cw(c5286.01,1337.48) 5286.01,1367.29 cw(c5286.02,1340.69) 5304.83,1359.5 5310.2,1354.13 5315.24,1349.08 ccw(c5329.27,1363.11) 5329.27,1343.27 ; 5327.42,1343.12 5327.57,1343.27 5329.27,1343.27 ; 5330.42,1343.12 5330.26,1343.27 ; v3(5454.8,1391.01) 5454.8,1387.53 5441.15,1373.88 cw(c5367.25,1447.78) 5367.25,1343.27 5330.26,1343.27 ; 5329.27,1343.27 5330.26,1343.27
ADC2_DB6_P: C273.2 J51.Y19 | length 4652.8
  L10_Signal Layer 2 w6.3: v3(5476.02,1369.79) 5476.02,1372.35 5507.04,1403.37 cw(c5555.9,1354.51) 5555.9,1423.61 5643.78,1423.61 cw(c5643.78,1373.77) 5679.02,1409.01 ; 5679.02,1409.01 5719.68,1368.35 ccw(c5796.12,1444.8) 5796.12,1336.69 5813.48,1336.69 cw(c5813.48,1317.67) 5826.93,1331.12 5832.84,1325.21 ccw(c5848.2,1341.11) 5848.18,1319.02 ccw(c5848.19,1348.57) 5869.09,1327.68 5873.82,1332.41 cw(c5884.15,1322.08) 5884.15,1336.69 5904.05,1336.69 ccw(c5904.08,1490.94) 5913.53,1336.98 5958.36,1336.98 ccw(c5958.36,1409.29) 6009.49,1358.16 6076.75,1425.42 cw(c6161.78,1340.39) 6161.78,1460.64 6192.47,1460.64 cw(c6192.47,1441.62) 6205.92,1455.07 6211.83,1449.16 6212.1,1448.9 ccw(c6227.73,1464.52) 6227.73,1442.42 6229.1,1442.42 ccw(c6229.1,1466.01) 6245.78,1449.33 6253.13,1456.68 cw(c6262.69,1447.12) 6262.69,1460.64 6475.39,1460.64 ccw(c6475.39,1565.05) 6549.22,1491.22 6597.47,1539.47 cw(c6647.44,1489.5) 6647.44,1560.17 6679.11,1560.17 cw(c6679.11,1541.53) 6692.29,1554.71 ccw(c6706.05,1568.47) 6706.05,1549.01 6794.62,1549.01 ccw(c6794.62,1570.83) 6816.44,1570.83 v1(6816.44,1574.01)
  L12_Bottom Layer w10: C273.2@2511.5,1648.37 C273.2@2512.49,1647.38 2512.49,1630.66 ccw(c2675.28,1630.66) 2675.28,1467.87 2802.04,1467.87 cw(c2802.04,1367.87) 2872.75,1438.58 2966.33,1345 ccw(c3038.5,1417.17) 3038.5,1315.11 4878,1315.11 5366.29,1315.12 ; 5367.24,1315.27 ccw(c5367.25,1447.78) 5460.95,1354.08 5474.92,1368.05 v3@5476.02,1368.05
ADC2_DB7+: C275.1 U17.L8 | length 65.1
  L12_Bottom Layer w10: v1(2448.74,1737.37) 2450.49,1735.63 2450.49,1674.36 C275.1@2449.5,1673.37
ADC2_DB7-: C278.1 U17.L9 | length 65.1
  L12_Bottom Layer w10: C278.1@2479.49,1673.37 2478.49,1674.37 2478.49,1735.62 v1(2480.24,1737.37)
ADC2_DB7_M: C278.2 J51.Y22 | length 4730.3
  L10_Signal Layer 2 w6.3: v3(5713.79,1190.14) 5715.59,1188.34 5968.25,1188.34 ccw(c5968.25,1457.56) 6158.62,1267.2 ; 6158.62,1267.2 6207.43,1316 cw(c6377.66,1145.77) 6377.65,1386.51 6725.35,1386.51 ccw(c6725.35,1403.55) 6737.4,1391.5 6739.88,1393.98 cw(c6752.03,1381.82) 6752.03,1399.01 6798.29,1399.01 ccw(c6798.29,1417.16) 6816.44,1417.16 v1(6816.44,1424.01)
  L12_Bottom Layer w10: C278.2@2479.33,1647.99 2479.1,1647.77 2478.33,1646.99 2478.33,1560.98 ccw(c2693.53,1560.98) 2693.53,1345.78 2742.13,1345.78 cw(c2742.13,1217.78) 2832.64,1308.29 2924.52,1216.41 ccw(c2995.23,1287.12) 2995.23,1187.12 3095.33,1187.12 ccw(c3095.33,1207.09) 3109.45,1192.97 3114.45,1197.97 3118.88,1202.41 cw(c3134.38,1186.91) 3134.38,1208.83 3145.55,1208.83 cw(c3145.55,1190.12) 3158.78,1203.35 3164.15,1197.98 3169.19,1192.93 ccw(c3183.22,1206.96) 3183.22,1187.12 3198.85,1187.12 ccw(c3198.85,1207.09) 3212.97,1192.97 3217.97,1197.97 3222.4,1202.41 cw(c3237.9,1186.91) 3237.9,1208.83 3249.07,1208.83 cw(c3249.07,1190.12) 3262.3,1203.35 3267.67,1197.98 3272.71,1192.93 ccw(c3286.74,1206.96) 3286.74,1187.12 3297.9,1187.12 ccw(c3297.9,1207.09) 3312.02,1192.97 3317.02,1197.97 3321.45,1202.41 cw(c3336.95,1186.91) 3336.95,1208.83 3348.12,1208.83 cw(c3348.12,1190.12) 3361.35,1203.35 3366.72,1197.98 3371.76,1192.93 ccw(c3385.79,1206.96) 3385.79,1187.12 4888.28,1187.12 ; 4888.4,1187.25 5706.8,1187.25 ccw(c5706.8,1197.13) v3(5713.79,1190.14)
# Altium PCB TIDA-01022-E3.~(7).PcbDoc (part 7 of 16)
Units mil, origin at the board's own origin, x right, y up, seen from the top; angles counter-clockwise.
Board outline 6929.13 x 11614.17 mil, 12 copper layers (L1_Top Layer, L2_GND, L3_GND, L4_Signal Layer 1, L5_GND, L6_PWR, L7_GND/PWR, L8_PWR, L9_GND/PWR, L10_Signal Layer 2, L11_GND, L12_Bottom Layer), stack 64.6 mil thick; 1733 components, 993 nets, 5987 pads, 3555 vias.

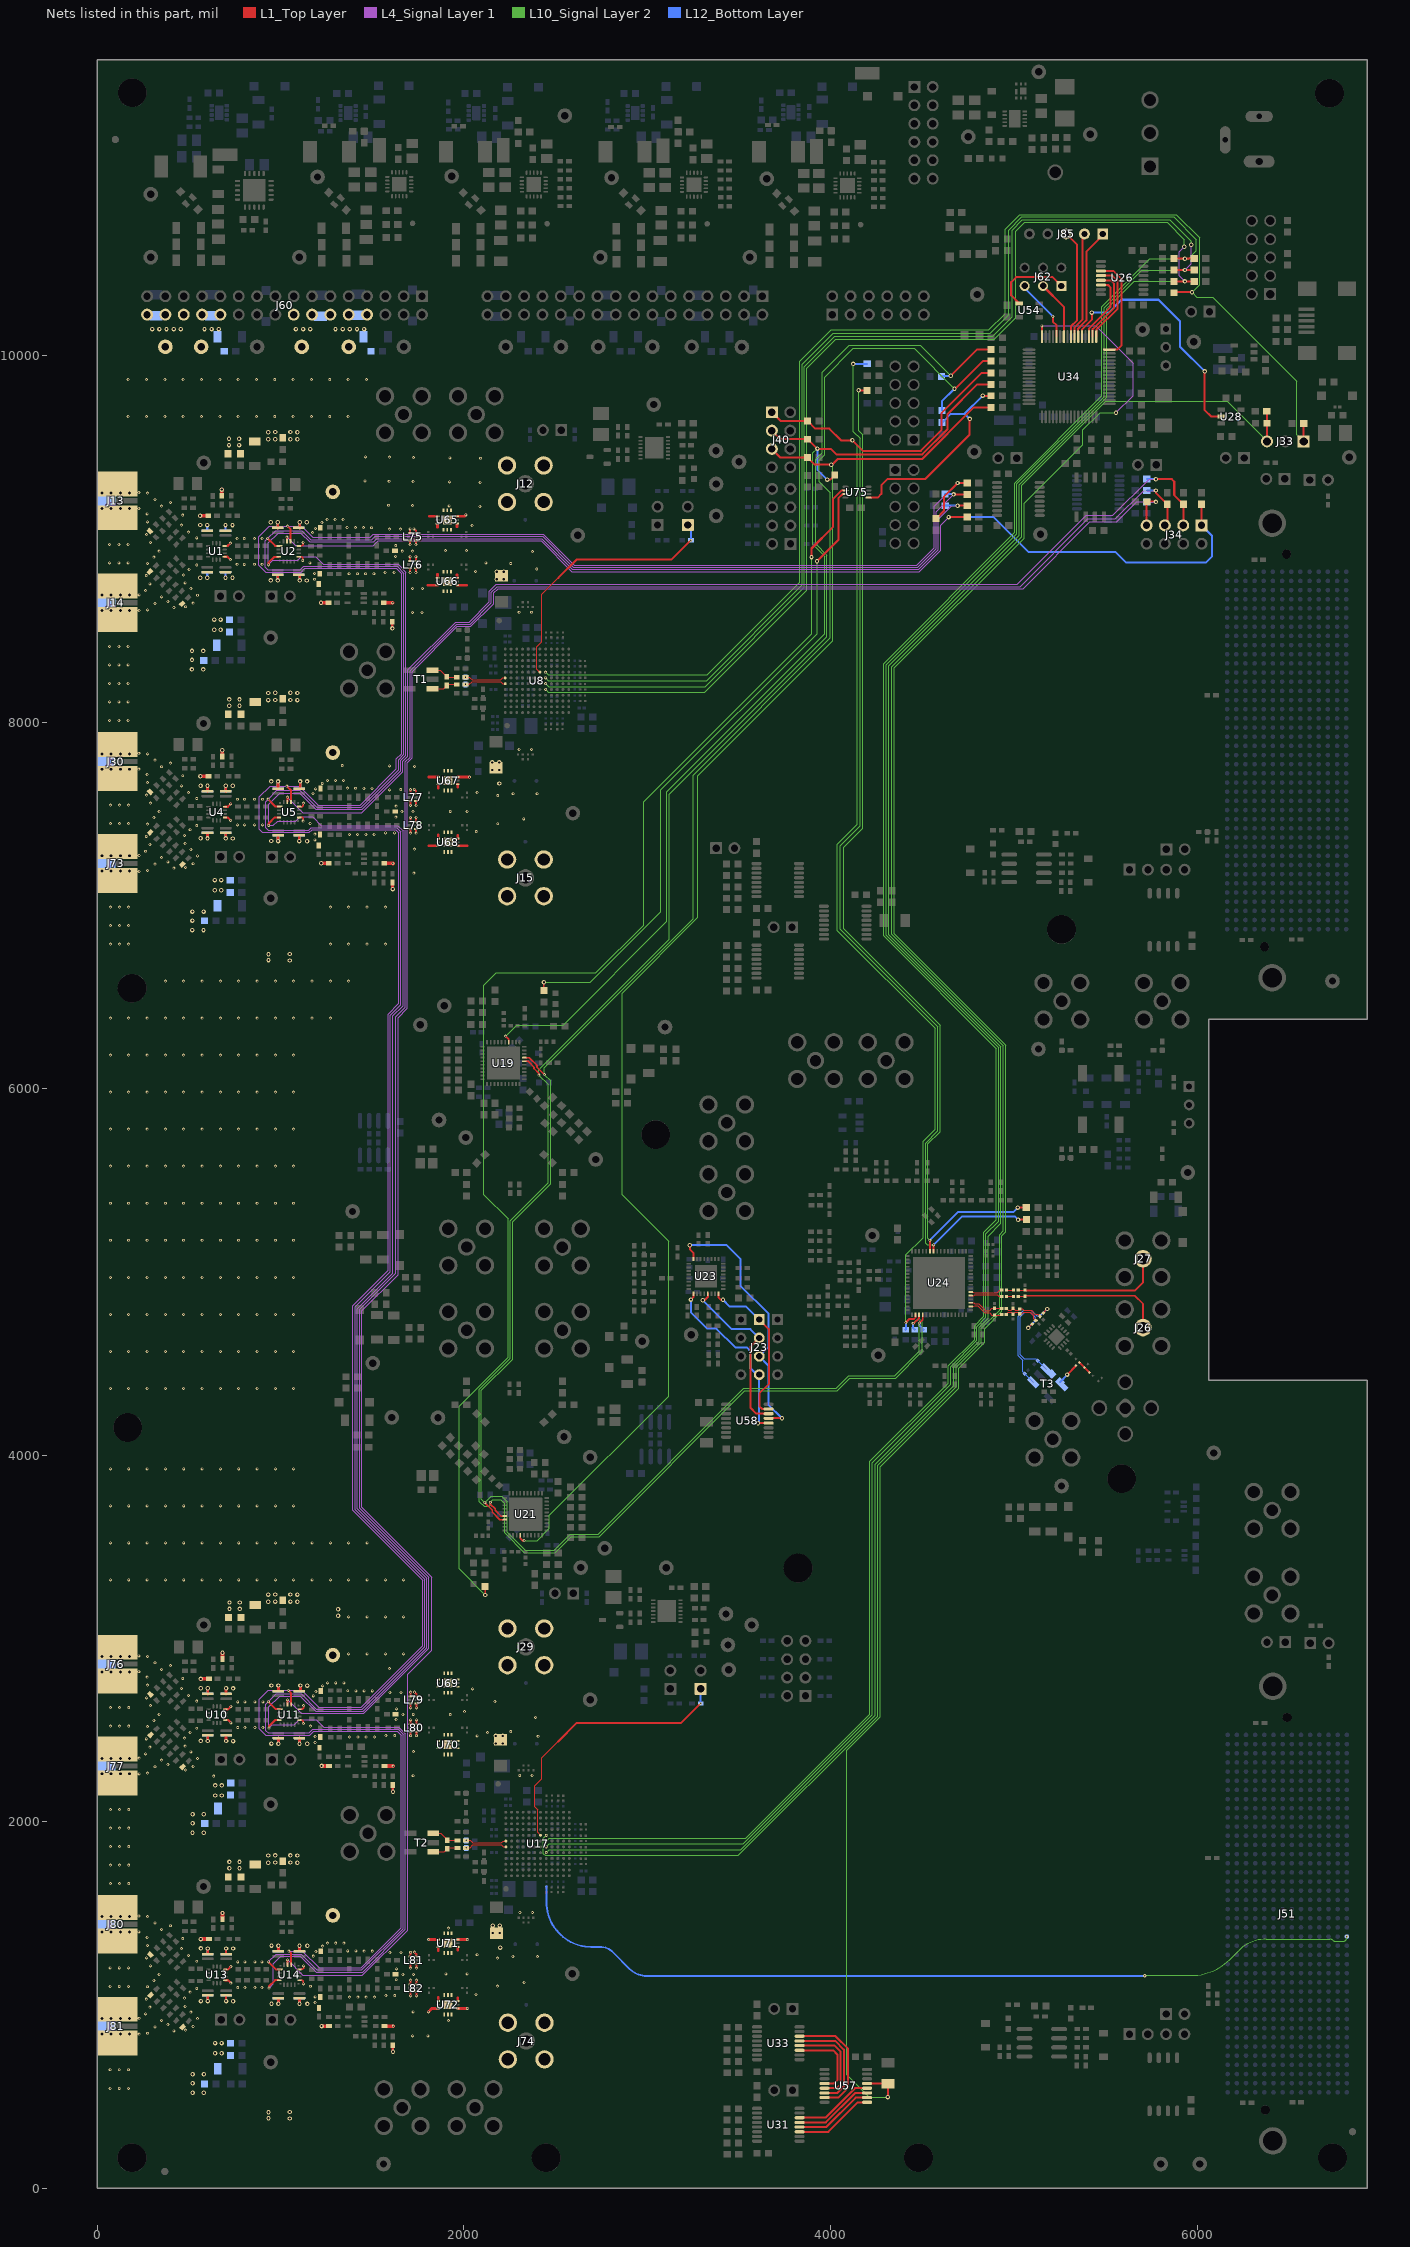
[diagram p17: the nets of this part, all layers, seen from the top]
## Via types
v1: diameter 16, hole 8, L1_Top Layer to L12_Bottom Layer, tented both sides, 1686 vias
v2: diameter 24, hole 12, L1_Top Layer to L12_Bottom Layer, tented both sides, 1590 vias
v3: diameter 20, hole 10, L1_Top Layer to L12_Bottom Layer, 279 vias

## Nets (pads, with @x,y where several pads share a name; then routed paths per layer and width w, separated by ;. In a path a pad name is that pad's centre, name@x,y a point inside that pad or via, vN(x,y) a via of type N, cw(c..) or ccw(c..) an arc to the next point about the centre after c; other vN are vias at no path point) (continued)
ADC2_DB7_P: C275.2 J51.Y23 | length 4727.8
  L10_Signal Layer 2 w6.3: v3(5713.79,1160.14) 5715.59,1161.94 5968.26,1161.94 ccw(c5968.25,1457.56) 6177.29,1248.53 6226.1,1297.33 cw(c6377.66,1145.77) 6377.66,1360.11 6438.23,1360.11 6665.66,1360.1 6724.07,1360.1 cw(c6724.07,1338.28) 6739.5,1353.71 ccw(c6750.85,1365.06) 6750.85,1349.01 6798.29,1349.01 ccw(c6798.29,1367.16) 6816.44,1367.16 v1(6816.44,1374.01)
  L12_Bottom Layer w10: C275.2@2450.33,1647 2450.33,1560.98 ccw(c2693.53,1560.98) 2693.53,1317.78 2742.13,1317.78 cw(c2742.13,1217.78) 2812.84,1288.49 2904.72,1196.61 ccw(c2995.23,1287.12) 2995.23,1159.12 4899.87,1159.12 ; 4900,1159.25 v3@5713.79,1159.25
ADC2_NCOA0: U31.3 U57.9 | length 435.1
  L1_Top Layer w11: U31.3@3830.94,308.84 3987.51,308.84 4148.62,469.95 U57.9@4199.29,469.95
ADC2_NCOA1: U31.4 U57.10 | length 435.1
  L1_Top Layer w11: U31.4@3830.94,334.43 3975.1,334.43 4136.21,495.54 U57.10@4199.29,495.54
ADC2_NCOB0: U31.5 U57.11 | length 435.1
  L1_Top Layer w11: U31.5@3830.94,360.02 3974.7,360.02 4135.81,521.13 U57.11@4199.29,521.13
ADC2_NCOB1: U31.6 U57.12 | length 435.1
  L1_Top Layer w11: U31.6@3830.94,385.61 3972.29,385.61 4133.4,546.72 U57.12@4199.29,546.72
ADC2_OVRA0: U33.3 U57.4 | length 432.2
  L1_Top Layer w11: U33.3@3830.94,753.55 4013.59,753.55 4036.76,730.37 4036.76,591.09 4017.98,572.31 U57.4@3967.01,572.31
ADC2_OVRA1: U33.4 U57.5 | length 512.1
  L1_Top Layer w11: U33.4@3830.94,779.14 4021.7,779.14 4054.76,746.08 4054.76,568.09 4033.39,546.72 U57.5@3967.01,546.72
ADC2_OVRB0: U33.5 U57.6 | length 582.8
  L1_Top Layer w11: U33.5@3830.94,804.73 4025.11,804.73 4072.76,757.08 4072.76,556.09 4037.8,521.13 U57.6@3967.01,521.13
ADC2_OVRB1: U33.6 U57.7 | length 656.3
  L1_Top Layer w11: U33.6@3830.94,830.32 4026.79,830.32 4095.4,761.7 4095.4,548.73 4042.21,495.54 U57.7@3967.01,495.54
ADC2_STS: R548.1 U34.32 U57.13 | length 11641.4
  L1_Top Layer w11: U57.13@4199.29,572.31 4312.27,572.31 R548.1@4313.15,571.43 ; R548.1@4312.27,570.55 4312.27,498.27 v2(4312.41,498.27) ; v1(5153.31,10161.44) 5154.25,10160.5 U34.32@5154.25,10102.47
  L4_Signal Layer 1 w5.5: v1(5153.31,10161.44) 5447.27,10161.44 5650,9958.7 5650,9781 v2(5557,9688)
  L10_Signal Layer 2 w6.5: v2(4312.41,498.27) 4209.73,498.27 4088.59,619.41 4088.59,2390.94 4271,2573.36 4271,3938.32 4699,4366.32 4699,4474 4840.1,4615.1 4840.1,4691.1 4935,4786 4935,5197 4956,5218 4956,6236.71 4348,6844.71 4348,8295 5056.5,9003.5 5056.5,9194.5 5376,9514 5376,9594 5470,9688 v2(5557,9688)
ADC_SCK: U26.3 U34.16 | length 569.8
  L1_Top Layer w11: U26.3@5474.72,10461.36 5542.64,10461.36 5588,10416 5588,10056 5563.61,10031.61 U34.16@5520.39,10031.61
ADC_SCS0: U26.6 U34.19 | length 374
  L1_Top Layer w11: U34.19@5410.15,10102.47 5410.15,10148.15 5526,10264 5526,10372 5513.41,10384.59 U26.6@5474.72,10384.59
ADC_SCS1: U28.2 U34.21 | length 1358.3
  L1_Top Layer w11: U34.21@5370.78,10102.47 5370.78,10141.39 5425,10195.61 v2(5425,10234) ; v2(6041,9913) 6041,9702 6076.09,9666.91 U28.2@6131.45,9666.91
  L12_Bottom Layer w11: v2(5425,10234) 5517,10234 5587,10304 5789,10304 5906.5,10186.5 5906.5,10047.5 v2(6041,9913)
ADC_SCS2X: J85.1 U34.22 | length 618.9
  L1_Top Layer w11: U34.22@5351.1,10102.47 5351.1,10147.1 5396,10192 5396,10567 J85.1@5492,10663
ADC_SCS3X: J85.2 U34.23 | length 585.6
  L1_Top Layer w11: U34.23@5331.41,10102.47 5331.41,10153.41 5374,10196 5374,10645 J85.2@5392,10663
ADC_SCS4X: J85.3 U34.24 | length 599.2
  L1_Top Layer w11: J85.3@5285,10663 5345,10603 5345,10193 5311.73,10159.73 U34.24@5311.73,10102.47
ADC_SDI: U26.4 U34.17 | length 456
  L1_Top Layer w11: U34.17@5449.52,10102.47 5449.52,10139.44 5566,10255.92 5566,10407 5537.23,10435.77 U26.4@5474.72,10435.77
ADC_SDO: U26.5 U34.18 | length 417.9
  L1_Top Layer w11: U34.18@5429.84,10102.47 5429.84,10143.8 5547,10260.96 5547,10392 5528.82,10410.18 U26.5@5474.72,10410.18
AGND: C1.2 C2.1 C3.1 C4.1 C5.1 C6.2 C7.2 C8.2 C9.2 C10.2 C12.2 C15.2 C17.2 C18.2 C19.2 C20.2 C21.1 C22.1 C23.1 C24.1 C25.1 C27.2 C28.2 C35.2 C36.1 C37.1 C38.1 C39.1 C40.2 C41.2 C42.2 C43.2 C44.2 C46.2 C49.2 C51.2 C52.2 C53.2 C54.2 C55.1 C56.1 C57.1 C58.1 C59.1 C61.2 C62.2 C161.2 C162.1 C163.1 C164.1 C165.1 C166.2 C167.2 C168.2 C169.2 C170.2 C172.2 C175.2 C177.2 C178.2 C179.2 C180.2 C181.1 C182.1 C183.1 C184.1 C185.1 C187.2 C188.2 C195.2 C196.1 C197.1 C198.1 C199.1 C200.2 C201.2 C202.2 C203.2 C204.2 C206.2 C209.2 C211.2 C212.2 C213.2 C214.2 C215.1 C216.1 C217.1 C218.1 C219.1 C221.2 C222.2 C561.1 C562.1 C563.1 C564.1 C566.1 C567.1 C570.1 C572.1 C573.1 C574.1 C575.1 C576.1 C658.2 C659.2 C663.1 C664.2 C665.1 C666.2 C670.2 C671.2 C672.1 C673.2 C674.1 C675.2 C689.2 C693.1 C694.2 C700.2 C703.1 C704.2 C709.2 C712.1 C713.2 C718.2 C721.1 C722.2 J12.2 J12.3 J12.4 J12.5 J13. J13.2 J13.3 J13.4 J14. J14.2 J14.3 J14.4 J15.2 J15.3 J15.4 J15.5 J29.2 J29.3 J29.4 J29.5 J30. J30.2 J30.3 J30.4 J60.8 J60.10 J60.12 J60.14 J60.16 J60.24 J60.26 J60.28 J60.30 J60.32 J73. J73.2 J73.3 J73.4 J74.2 J74.3 J74.4 J74.5 J76. J76.2 J76.3 J76.4 J77. J77.2 J77.3 J77.4 J80. J80.2 J80.3 J80.4 J81. J81.2 J81.3 J81.4 L75.1 L75.3 L75.4 L75.6 L76.1 L76.3 L76.4 L76.6 L77.1 L77.3 L77.4 L77.6 L78.1 L78.3 L78.4 L78.6 L79.1 L79.3 L79.4 L79.6 L80.1 L80.3 L80.4 L80.6 L81.1 L81.3 L81.4 L81.6 L82.1 L82.3 L82.4 L82.6 L93.1 L94.1 L95.1 L96.1 R20.1 R21.1 R44.1 R45.1 R101.1 R102.1 R125.1 R126.1 R188.2 R204.2 R207.2 R215.2 R483.1 R555.1 R558.1 R559.1 R564.1 R567.1 R568.1 R573.1 R576.1 R577.1 R582.1 R585.1 TP15.1 TP28.1 TP29.1 TP50.1 TP51.1 TP52.1 TP53.1 TP64.1 U1.11 U1.14 U2.9 U2.12 U4.11 U4.14 U5.9 U5.12 U10.11 U10.14 U11.9 U11.12 U13.11 U13.14 U14.9 U14.12 U65.1 U65.3 U65.4 U65.5 U65.6 U65.7 U65.9 U65.10 U65.11 U65.12 U65.13 U66.1 U66.3 U66.4 U66.5 U66.6 U66.7 U66.9 U66.10 U66.11 U66.12 U66.13 U67.1 U67.3 U67.4 U67.5 U67.6 U67.7 U67.9 U67.10 U67.11 U67.12 U67.13 U68.1 U68.3 U68.4 U68.5 U68.6 U68.7 U68.9 U68.10 U68.11 U68.12 U68.13 U69.1 U69.3 U69.4 U69.5 U69.6 U69.7 U69.9 U69.10 U69.11 U69.12 U69.13 U70.1 U70.3 U70.4 U70.5 U70.6 U70.7 U70.9 U70.10 U70.11 U70.12 U70.13 U71.1 U71.3 U71.4 U71.5 U71.6 U71.7 U71.9 U71.10 U71.11 U71.12 U71.13 U72.1 U72.3 U72.4 U72.5 U72.6 U72.7 U72.9 U72.10 U72.11 U72.12 U72.13 | length 4920.4
  L1_Top Layer w8: U2.9@1099.21,8901.73 1114.81,8901.73 1120.34,8896.2 v1(1120.34,8882) ; U2.12@1099.21,8960.79 1114.81,8960.79 1122,8967.98 v1(1122,8980) ; U5.9@1101.01,7479.6 1116.6,7479.6 1122.14,7474.07 v1(1122.14,7459.87) ; U5.12@1101.01,7538.66 1116.6,7538.66 1123.8,7545.85 v1(1123.8,7557.87) ; U11.9@1102.53,2555.37 1118.12,2555.37 1123.65,2549.84 v1(1123.65,2535.64) ; U11.12@1102.53,2614.42 1118.12,2614.42 1125.32,2621.62 v1(1125.32,2633.64) ; U14.9@1102.6,1136.03 1118.2,1136.03 1123.73,1130.5 v1(1123.73,1116.3) ; U14.12@1102.6,1195.09 1118.2,1195.09 1125.39,1202.28 v1(1125.39,1214.3)
  L1_Top Layer w11: v1(1705.63,8816) L76.3@1705.63,8839.31 ; L76.1@1705.63,8878.69 v1(1705.63,8902) ; v1(1705.63,8968) L75.3@1705.63,8991.31 ; L75.1@1705.63,9030.69 v1(1705.63,9054) ; v1(1707.43,7393.87) L78.3@1707.43,7417.19 ; L78.1@1707.43,7456.56 v1(1707.43,7479.87) ; v1(1707.43,7545.87) L77.3@1707.43,7569.19 ; L77.1@1707.43,7608.56 v1(1707.43,7631.87) ; v1(1708.95,2469.64) L80.3@1708.95,2492.95 ; L80.1@1708.95,2532.32 v1(1708.95,2555.64) ; v1(1708.95,2621.64) L79.3@1708.95,2644.95 ; L79.1@1708.95,2684.32 v1(1708.95,2707.64) ; v1(1709.02,1050.3) L82.3@1709.02,1073.62 ; L82.1@1709.02,1112.99 v1(1709.02,1136.3) ; v1(1709.02,1202.3) L81.3@1709.02,1225.62 ; L81.1@1709.02,1264.99 v1(1709.02,1288.3) ; v1(1726.68,9054.36) 1737.13,9043.92 L75.6@1737.13,9030.69 ; v1(1728.48,7632.23) 1738.92,7621.79 L77.6@1738.92,7608.56 ; v1(1730,2708) 1740.44,2697.56 L79.6@1740.44,2684.32 ; v1(1730.07,1288.66) 1740.52,1278.22 L81.6@1740.52,1264.99 ; v1(1737.13,8816) L76.4@1737.13,8839.31 ; L76.6@1737.13,8878.69 v1(1737.13,8902) ; v1(1737.13,8968) L75.4@1737.13,8991.31 ; v1(1738.92,7393.87) L78.4@1738.92,7417.19 ; L78.6@1738.92,7456.56 v1(1738.92,7479.87) ; v1(1738.92,7545.87) L77.4@1738.92,7569.19 ; v1(1740.44,2469.64) L80.4@1740.44,2492.95 ; L80.6@1740.44,2532.32 v1(1740.44,2555.64) ; v1(1740.44,2621.64) L79.4@1740.44,2644.95 ; v1(1740.52,1050.3) L82.4@1740.52,1073.62 ; L82.6@1740.52,1112.99 v1(1740.52,1136.3) ; v1(1740.52,1202.3) L81.4@1740.52,1225.62
  L1_Top Layer w12: v2(602.3,1021.64) C215.1@602.3,1052.5 ; C196.1@602.3,1278.09 v2(602.3,1308.95) ; U1.11@694.19,8901.46 709.78,8901.46 v1(725.19,8886.05) ; U1.14@694.19,8960.52 709.78,8960.52 v1(725.19,8975.93) ; U4.11@695.98,7479.34 711.58,7479.34 v1(726.99,7463.92) ; U4.14@695.98,7538.39 711.58,7538.39 v1(726.99,7553.8) ; U10.11@697.5,2555.1 713.1,2555.1 v1(728.51,2539.69) ; U10.14@697.5,2614.16 713.1,2614.16 v1(728.51,2629.57) ; U13.11@697.58,1135.76 713.17,1135.76 v1(728.59,1120.35) ; U13.14@697.58,1194.82 713.17,1194.82 v1(728.59,1210.23) ; v2(702.3,1021.64) C216.1@702.3,1052.5 ; C197.1@702.3,1278.09 v2(702.3,1308.95)
  L1_Top Layer w15: v2(600.71,7365.21) C55.1@600.71,7396.07 ; C36.1@600.71,7621.66 v2(600.71,7652.52) ; v2(602.23,2440.97) C181.1@602.23,2471.83 ; C162.1@602.23,2697.42 v2(602.23,2728.29) ; v2(700.71,7365.21) C56.1@700.71,7396.07 ; C37.1@700.71,7621.66 v2(700.71,7652.52) ; v2(702.23,2440.97) C182.1@702.23,2471.83 ; C163.1@702.23,2697.42 v2(702.23,2728.29) ; v2(984.09,8772.6) C23.1@984.09,8803.46 ; C4.1@984.09,9059.05 v2(984.09,9089.92) ; v2(985.55,7676) 985.55,7637.27 C38.1@985.89,7636.93 ; v2(985.89,7350.47) C57.1@985.89,7381.34 ; v2(987.41,2426.24) C183.1@987.41,2457.1 ; C164.1@987.41,2712.69 v2(987.41,2743.55) ; v2(987.48,1006.9) C217.1@987.48,1037.77 ; C198.1@987.48,1293.36 v2(987.48,1324.22) ; v2(1100.89,7350.47) C58.1@1100.89,7381.34 ; v2(1102.41,2426.24) C184.1@1102.41,2457.1 ; v2(1102.48,1006.9) C218.1@1102.48,1037.76 ; C199.1@1102.48,1293.36 v2(1102.48,1324.22) ; v2(1104.09,8772.6) C24.1@1104.09,8803.46 ; C5.1@1104.09,9059.05 v2(1104.09,9089.92) ; C39.1@1105.89,7636.93 1106,7637.04 v2(1106,7676) ; C165.1@1107.41,2712.69 v2(1107.41,2743.55) ; R558.1@1607.91,8547.16 1607.91,8512.21 v2(1609.19,8510.93) ; R567.1@1609.71,7125.04 1609.71,7090.09 v2(1610.99,7088.8) ; R576.1@1611.23,2200.8 1611.23,2165.85 v2(1612.51,2164.57) ; R585.1@1611.3,781.47 1611.3,746.52 v2(1612.59,745.23) ; 1803.55,8746.76 U66.3@1855.38,8746.76 ; v1(1805.24,963.3) 1823.92,981.98 U72.3@1859,981.98 ; v1(1807.16,1357.84) U71.1@1859,1357.84 ; 1807.16,7324.68 U68.3@1859,7324.68 ; 1807.16,7700.54 U67.1@1859,7700.54 ; 1810,9122.62 U65.1@1855.38,9122.62 ; U66.1@1855.38,8786.92 1855.38,8806.6 ; 1855.38,9062.78 U65.3@1855.38,9082.46 ; U72.1@1859,1022.14 1859,1041.81 ; 1859,1298 U71.3@1859,1317.68 ; U68.1@1859,7364.84 1859,7384.52 ; 1859,7640.7 U67.3@1859,7660.38 ; U66.7@1962.46,8746.76 2014.3,8746.76 ; U66.9@1962.46,8786.92 1962.46,8803.52 ; 1962.46,9065.86 U65.7@1962.46,9082.46 ; U65.9@1962.46,9122.62 2002.62,9122.62 v1(2010,9130) ; U72.7@1966.08,981.98 v1(2017.91,981.98) ; U72.9@1966.08,1022.14 1966.08,1038.74 ; 1966.08,1301.08 U71.7@1966.08,1317.68 ; U71.9@1966.08,1357.84 v1(2017.91,1357.84) ; U68.7@1966.08,7324.68 2017.91,7324.68 ; U68.9@1966.08,7364.84 1966.08,7381.44 ; 1966.08,7643.78 U67.7@1966.08,7660.38 ; U67.9@1966.08,7700.54 1966.62,7700 v1(2030,7700)
  L1_Top Layer w20: v2(560.31,9125.93) 560.25,9125.99 C1.2@604.79,9125.99 ; v2(562.11,7703.8) 562.05,7703.86 C35.2@606.59,7703.86 ; v2(563.63,2779.57) 563.57,2779.63 C161.2@608.11,2779.63 ; v2(563.7,1360.23) 563.65,1360.29 C195.2@608.18,1360.29 ; R483.1@678.91,9234.61 v2(678.91,9268.33) ; R559.1@680.71,7812.48 v2(680.71,7846.2) ; R568.1@682.23,2888.25 v2(682.23,2921.97) ; R577.1@682.3,1468.91 v2(682.3,1502.63) ; v2(1219.87,8651.26) C25.1@1260.47,8651.26 ; v2(1221.67,7229.13) C59.1@1262.27,7229.13 ; v2(1223.18,2304.9) C185.1@1263.79,2304.9 ; v2(1223.26,885.56) C219.1@1263.86,885.56 ; C28.2@1562.71,8651.26 1610.52,8651.26 v1(1610.52,8650.6) ; C62.2@1564.51,7229.13 1612.32,7229.13 v1(1612.32,7228.48) ; C188.2@1566.03,2304.9 1613.84,2304.9 v1(1613.84,2304.24) ; C222.2@1566.11,885.56 v1@1613.91,885.56
  L12_Bottom Layer w12: v2(598.91,8787.33) C17.2@598.91,8818.19 ; C6.2@598.91,9043.79 v2(598.91,9074.65) ; v2(600.71,7365.21) C51.2@600.71,7396.07 ; C40.2@600.71,7621.66 v2(600.71,7652.52) ; v2(602.23,2440.97) C177.2@602.23,2471.83 ; C166.2@602.23,2697.42 v2(602.23,2728.29) ; v2(602.3,1021.64) C211.2@602.3,1052.5 ; C200.2@602.3,1278.09 v2(602.3,1308.95) ; v2(698.91,8787.33) C18.2@698.91,8818.19 ; C7.2@698.91,9043.79 v2(698.91,9074.65) ; v2(700.71,7365.21) C52.2@700.71,7396.07 ; C41.2@700.71,7621.66 v2(700.71,7652.52) ; v2(702.23,2440.97) C178.2@702.23,2471.83 ; C167.2@702.23,2697.42 v2(702.23,2728.29) ; v2(702.3,1021.64) C212.2@702.3,1052.5 ; C201.2@702.3,1278.09 v2(702.3,1308.95)
  L12_Bottom Layer w15: v2(984.09,8772.6) C19.2@984.09,8803.46 ; C8.2@984.09,9059.05 v2(984.09,9089.92) ; v2(985.55,7676) 985.55,7637.27 C42.2@985.89,7636.93 ; v2(985.89,7350.47) C53.2@985.89,7381.34 ; v2(987.41,2426.24) C179.2@987.41,2457.1 ; C168.2@987.41,2712.69 v2(987.41,2743.55) ; v2(987.48,1006.9) C213.2@987.48,1037.77 ; C202.2@987.48,1293.36 v2(987.48,1324.22) ; v2(1100.89,7350.47) C54.2@1100.89,7381.34 ; v2(1102.41,2426.24) C180.2@1102.41,2457.1 ; v2(1102.48,1006.9) C214.2@1102.48,1037.77 ; C203.2@1102.48,1293.36 v2(1102.48,1324.22) ; v2(1104.09,8772.6) C20.2@1104.09,8803.46 ; C9.2@1104.09,9059.05 v2(1104.09,9089.92) ; C43.2@1105.89,7636.93 1106,7637.04 v2(1106,7676) ; C169.2@1107.41,2712.69 v2(1107.41,2743.55)
  other v1: 69.24,546.21 119.24,546.21 169.24,546.21 69.24,647.21 119.24,647.21 169.24,647.21 1720.14,832.11 1803.14,832.11 228,841.78 274.3,846.65 417.41,859.3 481,863.3 314.19,881.18 522.54,883.3 1613.91,884.91 383.97,893.04 1915,915 350.19,917.18 546.13,926.16 228,928.44 263.52,951.68 510.23,962.13 1722.24,963.3 286.33,988.61 478.68,993.2 1912.54,1002.06 1188.16,1013.3 266.36,1033.18 475.15,1037.74 1376.47,1043.3 1421.39,1043.3 1466.31,1043.3 1511.23,1043.3 1188.16,1045.3 1573.39,1051.3 1622.39,1051.3 2065.45,1058.43 505.77,1070.43 541.98,1091.1 765.59,1095.16 804.39,1095.03 859.59,1095.16 897.59,1095.16 272.7,1100.01 69.24,1102.3 119.24,1102.3 169.24,1102.3 1162.39,1102.88 2182,1104 2328,1124 307.79,1134.57 1630.23,1138.3 337,1167.3 1666.59,1167.3 1723.39,1167.3 1901.62,1170.22 2016.62,1170.22 1630.96,1197.3 69.24,1203.3 119.24,1203.3 169.24,1203.3 289,1214.3 804.39,1235.3 765.59,1235.43 859.59,1235.43 897.59,1235.43 541.98,1239.35 2182,1256 268,1257.3 2400,1265 2266.45,1265.43 1177.73,1267.33 495.97,1270.94 2071.16,1274.74 1596.2,1286.87 1656.39,1287.3 1192.43,1291.3 1410.39,1295.3 1455.01,1294.91 1499.64,1294.53 1365.77,1295.69 458.51,1308.33 1228.39,1322.03 272.23,1326.3 1256.39,1338.3 1300.39,1338.3 1344.39,1338.3 1912.54,1337.76 465.76,1363.3 271.35,1369.73 226.3,1399.51 350.19,1412.65 1915,1420 397.79,1432.78 314.19,1448.65 274.3,1483.17 226.3,1486.17 2305.26,1505.23 2372.85,1505.23 71.08,1662.55 121.08,1662.55 171.08,1662.55 71.08,1763.55 121.08,1763.55 171.08,1763.55 71.08,1864.55 121.08,1864.55 171.08,1864.55 71.08,1965.55 121.08,1965.55 171.08,1965.55 71.08,2066.55 121.08,2066.55 171.08,2066.55 634.63,2249.69 1721.98,2251.45 2304.05,2253.38 2371.64,2253.38 228,2261.12 274.3,2265.99 481,2282.64 314.19,2300.51 522.54,2302.64 383.97,2312.38 350.19,2336.51 546.13,2345.5 228,2347.77 263.52,2371.02 510.23,2381.46 1724.08,2382.64 286.33,2407.95 478.68,2412.53 1928,2419.27 1188.09,2432.64 266.36,2452.52 475.93,2457.06 1376.39,2462.64 1421.32,2462.64 1466.24,2462.64 1511.16,2462.64 1188.09,2464.64 2403.97,2467 2072,2469 1573.32,2470.64 1622.32,2470.64 2129,2487 506,2487.63 2255,2491.64 541.98,2510.44 765.52,2514.49 804.32,2514.36 859.52,2514.49 902.32,2514.36 272.7,2519.34 71.08,2521.64 121.08,2521.64 171.08,2521.64 1162.32,2522.21 307.79,2553.9 1630.15,2557.64 2390.65,2569.68 1925,2585 337,2586.64 1666.52,2586.64 1723.32,2586.64 2002.79,2600.89 1630.88,2616.64 71.08,2622.64 121.08,2622.64 171.08,2622.64 289,2633.64 765.52,2654.77 804.32,2654.64 859.52,2654.77 902.32,2654.64 2169,2655.36 541.98,2658.69 268,2676.64 1177.65,2686.67 495.97,2690.28 1596.12,2706.21 1656.32,2706.64 1192.35,2710.64 1454.94,2714.25 1499.56,2713.86 1365.69,2715.03 1410.32,2714.64 2047.32,2725.64 458.51,2727.67 1228.32,2741.37 272.23,2745.64 1912.54,2756.86 1256.32,2757.64 1300.32,2757.64 1344.32,2757.64 465.76,2782.64 271.35,2789.07 226.3,2818.85 350.19,2831.98 1593.09,2836.33 397.79,2852.11 314.19,2867.98 274.3,2902.51 226.3,2905.51 1371,2916 1471,2916 1571,2916 1671,2916 1371,3118 1471,3118 1571,3118 1671,3118 71,3320 171,3320 271,3320 371,3320 471,3320 571,3320 671,3320 771,3320 871,3320 971,3320 1071,3320 1171,3320 1271,3320 1371,3320 1471,3320 1571,3320 1671,3320 71,3522 171,3522 271,3522 371,3522 471,3522 571,3522 671,3522 771,3522 871,3522 971,3522 1071,3522 1171,3522 1271,3522 1371,3522 1471,3522 71,3724 171,3724 271,3724 371,3724 471,3724 571,3724 671,3724 771,3724 871,3724 971,3724 1071,3724 71,3926 171,3926 271,3926 371,3926 471,3926 571,3926 671,3926 771,3926 871,3926 971,3926 1071,3926 70.8,4364.78 170.8,4364.78 270.8,4364.78 370.8,4364.78 470.8,4364.78 570.8,4364.78 670.8,4364.78 770.8,4364.78 870.8,4364.78 970.8,4364.78 1070.8,4364.78 70.8,4566.78 170.8,4566.78 270.8,4566.78 370.8,4566.78 470.8,4566.78 570.8,4566.78 670.8,4566.78 770.8,4566.78 870.8,4566.78 970.8,4566.78 1070.8,4566.78 70.8,4768.78 170.8,4768.78 270.8,4768.78 370.8,4768.78 470.8,4768.78 570.8,4768.78 670.8,4768.78 770.8,4768.78 870.8,4768.78 970.8,4768.78 1070.8,4768.78 70.8,4970.78 170.8,4970.78 270.8,4970.78 370.8,4970.78 470.8,4970.78 570.8,4970.78 670.8,4970.78 770.8,4970.78 870.8,4970.78 970.8,4970.78 1070.8,4970.78 70.8,5172.78 170.8,5172.78 270.8,5172.78 370.8,5172.78 470.8,5172.78 570.8,5172.78 670.8,5172.78 770.8,5172.78 870.8,5172.78 970.8,5172.78 1070.8,5172.78 70.8,5374.78 170.8,5374.78 270.8,5374.78 370.8,5374.78 470.8,5374.78 570.8,5374.78 670.8,5374.78 770.8,5374.78 870.8,5374.78 970.8,5374.78 1070.8,5374.78 70.8,5576.78 170.8,5576.78 270.8,5576.78 370.8,5576.78 470.8,5576.78 570.8,5576.78 670.8,5576.78 770.8,5576.78 870.8,5576.78 970.8,5576.78 1070.8,5576.78 70.8,5778.78 170.8,5778.78 270.8,5778.78 370.8,5778.78 470.8,5778.78 570.8,5778.78 670.8,5778.78 770.8,5778.78 870.8,5778.78 970.8,5778.78 1070.8,5778.78 70.8,5980.78 170.8,5980.78 270.8,5980.78 370.8,5980.78 470.8,5980.78 570.8,5980.78 670.8,5980.78 770.8,5980.78 870.8,5980.78 970.8,5980.78 1070.8,5980.78 70.8,6182.78 170.8,6182.78 270.8,6182.78 370.8,6182.78 470.8,6182.78 570.8,6182.78 670.8,6182.78 770.8,6182.78 870.8,6182.78 970.8,6182.78 1070.8,6182.78 70.8,6384.78 170.8,6384.78 270.8,6384.78 370.8,6384.78 470.8,6384.78 570.8,6384.78 670.8,6384.78 770.8,6384.78 870.8,6384.78 970.8,6384.78 1070.8,6384.78 1170.8,6384.78 1270.8,6384.78 370.8,6586.78 470.8,6586.78 570.8,6586.78 670.8,6586.78 770.8,6586.78 870.8,6586.78 970.8,6586.78 1070.8,6586.78 1170.8,6586.78 1270.8,6586.78 1370.8,6586.78 70.8,6788.78 120.8,6788.78 170.8,6788.78 1270.8,6788.78 1370.8,6788.78 1470.8,6788.78 1570.8,6788.78 70.8,6889.78 120.8,6889.78 170.8,6889.78 70.8,6990.78 120.8,6990.78 170.8,6990.78 1270.8,6990.78 1370.8,6990.78 1470.8,6990.78 1570.8,6990.78 1727,7176 228,7185.35 274.3,7190.22 417.41,7202.87 481,7206.87 314.19,7224.75 522.54,7226.87 383.97,7236.61 350.19,7260.75 546.13,7269.73 228,7272.01 263.52,7295.25 510.23,7305.7 1729.1,7307.19 286.33,7332.18 478.68,7336.77 1925,7344.31 1186.57,7356.87 266.36,7376.75 474.81,7381.55 1374.88,7386.87 1419.8,7386.87 1464.72,7386.87 1509.64,7386.87 1186.57,7388.87 1571.8,7394.87 1620.8,7394.87 2067,7402 505.59,7412.34 541.98,7434.67 764,7438.73 802.8,7438.6 858,7438.73 900.8,7438.73 272.7,7443.58 2184,7445 70.8,7445.87 120.8,7445.87 170.8,7445.87 1160.8,7446.45 2326,7472 307.79,7478.14 1628.64,7481.87 337,7510.87 1661,7511 1721.8,7510.87 1925,7513 2016.62,7512.92 1629.36,7540.87 70.8,7546.87 120.8,7546.87 170.8,7546.87 289,7557.87 764,7579 802.8,7578.87 858,7579 900.8,7579 541.98,7582.92 2184,7599 268,7600.87 2268,7609 2399,7609 1176.14,7610.9 495.97,7614.51 2071.5,7615.48 1594.6,7630.44 1654.8,7630.87 1190.83,7634.87 1498.04,7638.1 1364.18,7639.26 1408.8,7638.87 1453.42,7638.48 458.51,7651.9 1226.8,7665.6 272.23,7669.87 1925,7680 1254.8,7681.87 1298.8,7681.87 1342.8,7681.87 465.76,7706.87 271.35,7713.3 226.3,7743.08 350.19,7756.22 1731,7758 1592.81,7760.57 1335.62,7762.66 397.79,7776.35 314.19,7792.22 274.3,7826.74 226.3,7829.74 2301.08,7851.2 2368.67,7851.2 67,8008.91 117,8008.91 167,8008.91 67,8109.91 117,8109.91 167,8109.91 67,8210.91 117,8210.91 167,8210.91 67,8311.91 117,8311.91 167,8311.91 67,8412.91 117,8412.91 167,8412.91 1717.9,8597.81 1770.9,8597.81 2301,8599 2368.59,8599 228,8607.48 274.3,8612.35 417.41,8625 481,8629 314.19,8646.87 522.54,8649 383.97,8658.74 350.19,8682.87 546.13,8691.86 228,8694.14 263.52,8717.38 510.23,8727.83 1720,8729 1773,8729 286.33,8754.31 478.68,8758.89 1908.92,8766.84 1184.77,8779 266.36,8798.88 470.28,8802.31 1373.08,8809 1418,8809 1462.92,8809 1507.84,8809 1184.77,8811 1570,8817 1619,8817 2063,8821.88 500.75,8832.4 2397,8835 541.98,8856.8 762.2,8860.85 801,8860.73 856.2,8860.85 899,8860.85 2255,8865 272.7,8865.71 67,8868 117,8868 167,8868 2119,8868 1159,8868.57 307.79,8900.27 1626.84,8904 2373,8930 337,8933 1663.2,8933 1720,8933 1898,8935 2013,8935 1627.57,8963 67,8969 117,8969 167,8969 289,8980 762.2,9001.13 801,9001 856.2,9001.13 899,9001.13 541.98,9005.05 268,9023 1174.34,9033.03 495.97,9036.64 1592.81,9052.57 1653,9053 1189.04,9057 1496.24,9060.22 1407,9061 1451.62,9060.61 1362.38,9061.39 2044,9072 458.51,9074.03 1225,9087.73 272.23,9092 1908.92,9102.54 1253,9104 1297,9104 1341,9104 465.76,9129 271.35,9135.43 226.3,9165.21 2086.19,9176.9 350.19,9178.34 1919.19,9178.9 1720.2,9180.6 1589.01,9182.69 397.79,9198.47 314.19,9214.34 274.3,9248.87 226.3,9251.87 2088.29,9308.09 1921.29,9310.09 1722.3,9311.78 1591.11,9313.88 1459.92,9315.98 2090.39,9439.28 1923.39,9441.28 1724.4,9442.97 1593.21,9445.07 1462.02,9447.17 167.68,9666.36 267.68,9666.36 367.68,9666.36 467.68,9666.36 567.68,9666.36 667.68,9666.36 767.68,9666.36 867.68,9666.36 967.68,9666.36 1067.68,9666.36 1167.68,9666.36 1267.68,9666.36 1367.68,9666.36 167.68,9868.36 267.68,9868.36 367.68,9868.36 467.68,9868.36 567.68,9868.36 667.68,9868.36 767.68,9868.36 867.68,9868.36 967.68,9868.36 1067.68,9868.36 1167.68,9868.36 1267.68,9868.36 1367.68,9868.36 1467.68,9868.36
  other v2: 1049.25,381.2 933.25,383.2 933.64,415.58 1049.25,416.58 519.18,521.43 580.59,521.43 519.59,573.43 519.59,622.43 581.01,622.43 642.33,737.37 677.33,737.37 642.33,792.62 677.33,792.62 949.57,1007.26 1145.4,1006.55 740.21,1021.28 564.39,1021.99 564.39,1309.3 740.21,1308.6 2198,1314 1145.4,1323.87 949.57,1324.57 2157.41,1392.9 2195.33,1393 2157.41,1433.9 2195.33,1434 719.91,1746.23 775.17,1746.23 932.54,1777.06 1091,1777.06 970.54,1777.84 1053,1777.84 719.91,1781.23 775.17,1781.23 932.31,1816.04 1091.23,1816.04 970.77,1816.82 1052.77,1816.82 518.8,1940.55 580.21,1940.55 519.21,1992.55 519.21,2041.55 580.63,2041.55 642.88,2143.32 677.88,2143.32 642.88,2198.58 677.88,2198.58 1145.32,2425.89 949.5,2426.59 2173.08,2427.9 2211,2428 740.14,2440.62 564.32,2441.32 2173.08,2468.9 2211,2469 740.14,2727.93 564.32,2728.64 1145.32,2743.2 949.5,2743.91 1313.41,3124.43 1313.41,3159.43 720.84,3161.5 776.09,3161.5 720.84,3196.5 776.09,3196.5 932.54,3200.64 1091,3200.64 970.54,3201.41 1053,3201.41 932.31,3239.61 1091.23,3239.61 970.77,3240.39 1052.77,3240.39 1049.25,6699.2 933.25,6701.2 933.64,6733.58 1049.25,6734.58 517.58,6865 579,6865 518,6917 518,6966 579.42,6966 640.56,7082.57 675.56,7082.57 640.56,7137.83 675.56,7137.83 1143.8,7350.12 947.98,7350.83 738.62,7364.85 562.8,7365.56 738.62,7652.17 562.8,7652.87 2193,7665 947.98,7676 1143.8,7676 2154.08,7738.9 2192,7739 2154.08,7779.9 2192,7780 719.74,8088.8 774.99,8088.8 932.54,8119.63 1091,8119.63 970.54,8120.41 1053,8120.41 719.74,8123.8 774.99,8123.8 932.31,8158.61 1091.23,8158.61 970.77,8159.39 1052.77,8159.39 515.79,8287.13 577.2,8287.13 516.2,8339.13 516.2,8388.13 577.62,8388.13 636.97,8503.83 671.97,8503.83 636.97,8559.08 671.97,8559.08 1142,8772.25 946.18,8772.95 2179.08,8778.9 2217,8779 736.82,8786.98 561,8787.69 2179.08,8819.9 2217,8820 736.82,9074.29 561,9075 946.18,9090.27 1142,9089.56 717.94,9510.93 773.19,9510.93 932.54,9542.63 1091,9542.63 970.54,9543.42 1053,9543.42 717.94,9545.93 773.19,9545.93 932.31,9581.61 1091.23,9581.61 970.77,9582.39 1052.77,9582.39 299,10144 338,10144 377,10144 416,10144 455,10144 584,10144 623,10144 662,10144 1083,10144 1122,10144 1161,10144 1299,10144 1338,10144 1377,10144 1416,10144 1455,10144
BADC1_SCS: J33.1 R380.2 R400.2 U8.E8 | length 7271.2
  L1_Top Layer w11: R400.2@5873.84,10342.12 5876.72,10345 v2(5972,10345) ; J33.1@6581,9531 R380.2@6581,9629.5
  L10_Signal Layer 2 w3.5: v1(2445.41,8272.34) 2460.16,8257.59 2597.38,8257.59
  L10_Signal Layer 2 w6.5: 2597.38,8257.59 3327.59,8257.59 3832.5,8762.5 3832.5,9967.5 4005,10140 4864,10140 4952,10228 4952,10688 5033,10769 5887,10769 6014,10642 6014,10387 v2(5972,10345) 5999,10318 6084,10318 6544,9858 6544,9568 J33.1@6581,9531
BADC2_SCS: J33.3 R382.2 R416.2 U17.E8 | length 11574.9
  L1_Top Layer w11: R382.2@6379.5,9696 6380.5,9695 R416.2@6380.5,9630 6380.5,9531.5 J33.3@6381,9531
  L10_Signal Layer 2 w3.5: v1(2448.74,1926.34) 2433.33,1910.93 2433.33,1826.4 2442.63,1817.1 2601.3,1817.1
  L10_Signal Layer 2 w6.5: 2601.3,1817.1 3497.07,1817.1 4257,2577.03 4257,3946 4685,4374 4685,4477 4686.5,4478.5 4686.5,4479.18 4823.16,4615.84 4823.16,4691.84 4922.5,4791.18 4922.5,5204 4942,5223.5 4942,6233.03 4334,6841.03 4334,8300.8 5044,9010.8 5044,9291 5502,9749 6163,9749 J33.3@6381,9531
BADC_SCK: R375.1 R394.2 U8.F8 U17.F8 | length 17212.2
  L1_Top Layer w11: R394.2@5873.84,10528.12 v2(5933,10528.12) R375.1@5983.79,10528.12
  L10_Signal Layer 2 w3.5: v1(2445.41,8240.84) 2460.16,8226.09 2597.97,8226.09 ; v1(2448.74,1894.85) 2465.49,1911.59 2601.3,1911.59
  L10_Signal Layer 2 w6.5: 2597.97,8226.09 3323.09,8226.09 3845,8748 3845,9952 4014,10121 4870,10121 4971,10222 4971,10684 5043,10756 5872,10756 5996,10632 5996,10570 5954.12,10528.12 v2(5933,10528.12) 5740.11,10528.12 5479,10267.01 5479,9779.03 5004,9304.03 5004,9034.44 4289,8319.44 4289,6833 4904.5,6217.5 4904.5,5284.5 4835.25,5215.25 4835.25,4756.96 4785.66,4707.37 4785.66,4631.37 4642,4487.71 4642,4394 4214,3966 4214,2587.07 3538.53,1911.59 2601.3,1911.59
BADC_SDI: R377.1 R396.2 U8.G8 U17.G8 | length 17209.2
  L1_Top Layer w11: R396.2@5873.84,10466.12 v2(5933,10466.12) 5933.07,10466.05 R377.1@5983.79,10466.05
  L4_Signal Layer 1 w5.5: v2(5933,10466.12) 5968,10501.12 v2(5968,10604)
  L10_Signal Layer 2 w3.5: v1(2445.41,8209.35) 2461.58,8193.17 2597.97,8193.17 ; v1(2448.74,1863.35) 2465.49,1880.1 2601.3,1880.1
  L10_Signal Layer 2 w6.5: 2597.97,8193.17 3316.17,8193.17 3857.5,8734.5 3857.5,9939.5 4023,10105 4884,10105 4991,10212 4991,10684 5047,10740 5851,10740 5968,10623 v2(5968,10604) ; 2601.3,1880.1 3524.71,1880.1 4228,2583.39 4228,3958 4656,4386 4656,4484.03 4798.16,4626.19 4798.16,4702.19 4847.75,4751.78 4847.75,5207.43 4917,5276.68 4917,6222.68 4303,6836.68 4303,8313.64 5016.5,9027.14 5016.5,9298.86 5493,9775.36 5493,10261.21 5697.9,10466.12 v2(5933,10466.12)
BADC_SDO: R379.1 R398.2 U8.H8 U17.H8 | length 17235.9
  L1_Top Layer w11: R398.2@5873.84,10404.12 v2(5933,10404.12) 5934.12,10403 R379.1@5984,10403
  L4_Signal Layer 1 w5.5: v2(5930,10593) 5903,10566 5903,10434.12 v2(5933,10404.12)
  L10_Signal Layer 2 w3.5: v1(2445.41,8177.85) 2460.16,8163.1 2483.02,8163.1 2483.09,8163.17 2502.22,8163.17 2502.29,8163.1 2546.01,8163.1 2546.08,8163.17 2597.97,8163.17 ; v1(2448.74,1831.85) 2464.06,1847.18 2601.3,1847.18
  L10_Signal Layer 2 w6.5: 2597.97,8163.17 3313.17,8163.17 3870,8720 3870,9931 4027.5,10088.5 4893.5,10088.5 5010,10205 5010,10678 5058,10726 5836,10726 5930,10632 v2(5930,10593) ; 2601.3,1847.18 3509.47,1847.18 4243,2580.71 4243,3952 4671,4380 4671,4481.36 4810.66,4621.02 4810.66,4697.02 4860.25,4746.61 4860.25,5195.86 4929.5,5265.11 4929.5,6227.86 4318,6839.36 4318,8307.43 5029,9018.43 5029,9293.68 5508,9772.68 5508,10255 5657.12,10404.12 v2(5933,10404.12)
BDBUS0: J62.3 U34.26 | length 323.5
  L1_Top Layer w11: J62.3@5159,10379 5272.36,10265.64 U34.26@5272.36,10102.47
BDBUS1: J62.1 U54.4 | length 440.2
  L1_Top Layer w11: U54.4@5029.75,10283.37 4985,10328.12 4985,10400 5012,10427 5211,10427 J62.1@5259,10379
BDBUS2: J62.5 U34.28 | length 348.6
  L1_Top Layer w11: v1(5212.88,10213.47) 5212.88,10184.46 5232.99,10164.35 U34.28@5232.99,10102.47
  L12_Bottom Layer w11: J62.5@5059,10379 5059,10367.36 v1(5212.88,10213.47)
BLMH1_SCS: J34.1 R381.2 R402.2 U2.15 | length 5905.4
  L1_Top Layer w11: U2.15@1034.25,8986.38 v1(1034.25,9009) ; v2(4644,9118) 4745.12,9118 R402.2@4745.32,9118.2 ; R381.2@6021.5,9186 R381.2@6024,9188.5 J34.1@6024,9073
  L4_Signal Layer 1 w5.5: v1@1033,9010 1081.35,8961.65 1505.07,8961.65 1531.58,8988.15 2420.57,8988.15 2587.72,8821 4485,8821 4601,8937 4601,9075 v2(4644,9118)
  L12_Bottom Layer w11: v2(4644,9118) 4890,9118 5079,8929 5553,8929 5612,8870 6047,8870 6082,8905 6082,9015 J34.1@6024,9073
BLMH2_SCS: J34.3 R383.2 R424.2 U5.15 | length 6309.1
  L1_Top Layer w11: U5.15@1036,7566.2 v1(1036,7590) ; v2(5775,9325.2) 5861.8,9325.2 5875,9312 5875,9238.5 R383.2@5925,9188.5 5925,9074 J34.3@5924,9073
  L4_Signal Layer 1 w5.5: v1(1036,7590) 1120,7506 1442,7506 1666,7730 1666,7785.53 1694.5,7814.03 1694.5,8284.82 1954.84,8545.16 2028.51,8545.16 2138.5,8655.15 2138.5,8713.76 2175.74,8751 5018,8751 5394,9127 5540,9127 5738.2,9325.2 v2(5775,9325.2)
  L12_Bottom Layer w11: R424.2@5725.31,9325.2 v2(5775,9325.2)
BLMH3_SCS: J34.5 R384.2 R423.2 U11.15 | length 11361.6
  L1_Top Layer w11: v1(1037.52,2665.77) 1037.52,2640.06 U11.15@1037.57,2640.01 ; v2(5775,9263.2) 5775,9250.5 R384.2@5837,9188.5 5837,9086 J34.5@5824,9073
  L4_Signal Layer 1 w5.5: v1(1037.52,2665.77) 1112.28,2591 1453.8,2591 1808.5,2945.7 1808.5,3333.29 1430,3711.79 1430,4795.74 1627,4992.74 1627,6391.26 1679.18,6443.44 1679.18,7782.44 1706,7809.26 1706,8280.06 1959.6,8533.66 2033.27,8533.66 2150,8650.39 2150,8709 2180.33,8739.33 5034.33,8739.33 5404,9109 5553,9109 5707.2,9263.2 v2(5775,9263.2)
  L12_Bottom Layer w11: R423.2@5725.31,9263.2 v2(5775,9263.2)
BLMH4_SCS: J34.7 R385.2 R421.2 U14.15 | length 12713.9
  L1_Top Layer w11: v1(1037.59,1246.43) 1037.59,1220.73 U14.15@1037.64,1220.68 ; J34.7@5724,9073 5724,9199.89 R385.2@5726.13,9202.01 5774.19,9202.01 v2(5775,9201.2)
  L4_Signal Layer 1 w5.5: v1(1037.59,1246.43) 1121.59,1162.43 1446.22,1162.43 1692.2,1408.41 1692.2,2806.2 1823,2937 1823,3335.05 1442,3716.05 1442,4787 1640,4985 1640,6388 1690.68,6438.68 1690.68,7777.68 1717.5,7804.5 1717.5,8275.3 1964.36,8522.16 2038.03,8522.16 2162,8646.13 2162,8704.23 2185.59,8727.83 5049.83,8727.83 5414,9092 5561,9092 5670.2,9201.2 v2(5775,9201.2)
  L12_Bottom Layer w11: R421.2@5725.31,9201.2 v2(5775,9201.2)
BLMH_CLK: R374.1 R409.2 U2.14 U5.14 U11.14 U14.14 | length 17342.8
  L1_Top Layer w11: v1(1033.23,7650) 1056.5,7626.73 1056.5,7565.02 U5.14@1055.73,7564.25 ; v1(1037.52,9069) 1053.93,9052.58 U2.14@1053.93,8986.38 ; v1(1041.38,2717) 1057.25,2701.13 U11.14@1057.25,2640.01 ; v1(1044.22,1295) 1057.33,1281.9 U14.14@1057.33,1220.68 ; R374.1@4576,9110 4620,9154 4620,9231.2 v2(4693,9304.2) R409.2@4745.32,9304.2
  L4_Signal Layer 1 w5.5: v1(1044.22,1295) 1118.02,1295 1209.59,1203.43 1438.43,1203.43 1657.7,1422.7 1657.7,2471.81 1636.01,2493.5 1179.5,2493.5 1159.53,2473.53 919.46,2473.53 884,2508.99 884,2669 932,2717 v1(1041.38,2717) 1115.28,2717 1206.78,2625.5 1439.51,2625.5 1774,2959.99 1774,3319 1393,3700 1393,4815 1587,5009 1587,6407 1644.68,6464.68 1644.68,7396.2 1628.37,7412.5 1171.5,7412.5 1157,7398 900,7398 884,7414 884,7592 942,7650 v1(1033.23,7650) 1101,7650 1204,7547 1434.21,7547 1631.5,7744.29 1631.5,7799.82 1660,7828.32 1660,8808.16 1630.16,8838 1130.26,8838 1110.76,8818.5 917.24,8818.5 880,8855.74 880,9011 938,9069 v1(1037.52,9069) 1114.68,9069 1175.91,9007.77 1488.77,9007.77 1505.35,9024.35 2433.16,9024.35 2601.26,8856.25 4471.46,8856.25 4565,8949.79 4565,9176.2 v2(4693,9304.2)
BLMH_SDI: R378.1 R407.2 U2.1 U5.1 U11.1 U14.1 | length 17028.2
  L1_Top Layer w11: v1(929.13,9001.58) 969.93,8960.79 U2.1@992.91,8960.79 ; v1(930.93,7579.46) 971.73,7538.66 U5.1@994.71,7538.66 ; v1(932.45,2655.22) 973.25,2614.42 U11.1@996.23,2614.42 ; v1(932.52,1235.89) 973.32,1195.09 U14.1@996.3,1195.09 ; v2(4671,9242) 4745.12,9242 R407.2@4745.32,9242.2
  L4_Signal Layer 1 w5.5: v1(932.52,1235.89) 974.89,1278.25 1111.54,1278.25 1197.86,1191.93 1443.19,1191.93 1669.2,1417.93 1669.2,2476.58 1640.77,2505 1174.74,2505 1154.77,2485.03 930.89,2485.03 919.4,2496.53 919.4,2642.18 v1(932.45,2655.22) 974.99,2697.77 1111.28,2697.77 1195.05,2614 1444.27,2614 1785.5,2955.23 1785.5,3323.76 1406,3703.26 1406,4809.26 1599,5002.26 1599,6401 1656.18,6458.18 1656.18,7400.96 1633.14,7424 1166.74,7424 1152.24,7409.5 932.5,7409.5 917.55,7424.45 917.55,7566.08 v1(930.93,7579.46) 978.47,7627 1104.76,7627 1196.26,7535.5 1438.97,7535.5 1643,7739.53 1643,7795.05 1671.5,7823.55 1671.5,8812.93 1634.93,8849.5 1125.5,8849.5 1106,8830 930,8830 916,8844 916,8988.45 v1(929.13,9001.58) 971.79,9044.24 1115.29,9044.24 1165.22,8994.31 1497.31,8994.31 1515.85,9012.85 2428.4,9012.85 2596.49,8844.75 4476.22,8844.75 4576.5,8945.03 4576.5,9147.5 v2(4671,9242)
  L12_Bottom Layer w11: R378.1@4623.5,9244 4669,9244 v2(4671,9242)
BLMH_SDO: R376.1 R405.2 U2.4 U5.4 U11.4 U14.4 | length 17115.7
  L1_Top Layer w11: v1(932.84,8858) 932.84,8868.57 965.99,8901.73 U2.4@988.97,8901.73 ; v1(934.63,7435.87) 934.63,7446.45 967.79,7479.6 U5.4@990.77,7479.6 ; v1(936.15,2511.64) 936.15,2522.21 969.31,2555.37 U11.4@992.29,2555.37 ; v1(936.23,1092.3) 936.23,1102.88 969.39,1136.03 U14.4@992.37,1136.03 ; v2(4693,9180.2) R405.2@4745.32,9180.2
  L4_Signal Layer 1 w5.5: v1(934.63,7435.87) 959.87,7435.87 983,7459 1082,7459 1106,7483 1174,7483 1221.5,7435.5 1637.9,7435.5 1667.68,7405.72 1667.68,6453.41 1612,6397.74 1612,4994 1418,4800 1418,3707.53 1797,3328.53 1797,2950.47 1449.03,2602.5 1190.28,2602.5 1106.52,2686.27 994.02,2686.27 936.15,2628.4 v1@936.15,2513.77 ; v1@934.63,7438 934.63,7552.63 994,7612 1103.5,7612 1191.5,7524 1443.74,7524 1654.5,7734.76 1654.5,7790.29 1683,7818.79 1683,8818 1640,8861 1231,8861 1190.33,8901.67 1112.67,8901.67 1093,8882 956.84,8882 v1(932.84,8858) 932.84,8977.41 986.42,9031 1109.29,9031 1157.48,8982.81 1507.67,8982.81 1524.51,8999.65 2425.33,8999.65 2591.73,8833.25 4480.99,8833.25 4588,8940.26 4588,9107.73 4660.47,9180.2 v2(4693,9180.2) ; v1(936.15,2511.64) 954.52,2530 1074.78,2530 1100.78,2556 1195,2556 1234,2517 1645.04,2517 1680.7,2481.34 1680.7,1413.17 1447.96,1180.43 1193.09,1180.43 1106.77,1266.75 1001.41,1266.75 960,1225.34 960,1116.07 v1(936.23,1092.3)
  L12_Bottom Layer w11: R376.1@4625.06,9180.1 4625.16,9180.2 v2(4693,9180.2)
BLMK_LMX_SCK: C426.2 R426.1 R445.2 U19.16 U21.16 U24.19 | length 11880.3
  L1_Top Layer w9: v1(2143.7,3743.46) 2143.7,3733.36 2169.71,3707.35 2169.71,3700.31 2202.05,3667.97 2222.59,3667.97 U21.16@2222.93,3667.97 ; U19.16@2329.03,6149.66 2349.91,6149.66 2382.25,6117.32 2382.25,6110.28 2408.26,6084.27 v1(2408.26,6074.17)
  L1_Top Layer w9.84: 4480.31,4745.35 4482.99,4748.04 U24.19@4482.99,4766.5
  L1_Top Layer w11: v1(4450.47,4719.94) 4454.89,4719.94 4480.31,4745.35 ; v2(4656,9889) 4800,10033 R445.2@4874.82,10033
  L10_Signal Layer 2 w6.5: v1(4450.47,4719.94) 4469.25,4738.72 4491.15,4738.72 4501.25,4728.61 4501.25,4566.57 4354.68,4420 4104.54,4420 4036.28,4351.74 3532.74,4351.74 2737,3556 2584.68,3556 2497.18,3468.5 2329.82,3468.5 2222,3576.32 2222,3735.32 2199.82,3757.5 2157.74,3757.5 v1(2143.7,3743.46) 2143.7,3727.7 2136.75,3720.75 2109.25,3720.75 2083,3747 2083,4359.19 2253.5,4529.69 2253.5,5279.95 2459.5,5485.95 2459.5,6022.93 v1(2408.26,6074.17) 2408.26,6102.29 3120,6814.03 3120,7605 3980,8465 3980,8911 3919,8972 3919,9434 3955,9470 3955,9909 4102,10056 4489,10056 v2(4656,9889)
  L12_Bottom Layer w11: v1(4450.47,4719.94) 4450.47,4694.52 4459.47,4685.52 C426.2@4458.97,4685.02 ; R426.1@4605.5,9886 4608.5,9889 v2(4656,9889)
BLMK_LMX_SDI: C425.2 R427.1 R447.2 U19.17 U21.17 U24.20 | length 11888
  L1_Top Layer w9: v1(2113.65,3740.78) 2153.71,3700.72 2153.71,3690.46 2195.54,3648.63 U21.17@2222.59,3648.63 ; U19.17@2329.38,6169 2356.42,6169 2398.25,6127.17 2398.25,6116.91 v1(2438.31,6076.84)
  L1_Top Layer w9.84: 4502.68,4740.15 U24.20@4502.68,4766.5
  L1_Top Layer w11: v1(4484,4721.47) 4502.68,4740.15 ; v2(4676,9818) 4680,9818 4831,9969 R447.2@4874.82,9969
  L10_Signal Layer 2 w6.5: v1(4484,4721.47) 4484,4567 4349.5,4432.5 4099.36,4432.5 4031.1,4364.24 3527.56,4364.24 2731.82,3568.5 2579.5,3568.5 2492,3481 2335,3481 2236,3580 2236,3745 2206,3775 2147.87,3775 v1(2113.65,3740.78) 2095.5,3758.94 2095.5,4354.01 2266,4524.51 2266,5274.77 2472,5480.77 2472,6043.16 v1(2438.31,6076.84) 2438.31,6114.67 3250,6926.36 3250,7711 3998,8459 3998,9251 3938,9311 3938,9429 3968,9459 3968,9882 4124.5,10038.5 4455.5,10038.5 v2(4676,9818)
  L12_Bottom Layer w11: v1(4484,4721.47) 4484,4708.73 4487.2,4705.53 4487.2,4705.28 C425.2@4507.97,4684.51 ; R427.1@4607.5,9699 4607.5,9749.5 v2(4676,9818)
BLMK_LMX_SDO: R428.1 R449.2 U75.1 | length 1175.4
  L1_Top Layer w11: U75.1@4206.99,9224.47 4256.47,9224.47 4277,9245 4277,9292 4310,9325 4515,9325 4759,9569 v2(4759,9654) ; v2(4830,9781) 4830,9780 R449.2@4874.82,9780
  L12_Bottom Layer w11: R428.1@4608.5,9634 4656,9681.5 4730.5,9681.5 ; v2(4759,9654) 4758,9654 4730.5,9681.5 ; v2(4830,9781) 4730.5,9681.5
BLMK_LMX_SDO1: R187.2 U75.7 | length 3547.8
  L1_Top Layer w8.6: R187.2@2435.81,6535.21 v2(2435.81,6580.72)
  L1_Top Layer w11: v2(3926,8877) 4042.09,8993.09 4042.09,9220.01 4066.24,9244.16 U75.7@4081.01,9244.16
  L10_Signal Layer 2 w6.5: v2(2435.81,6580.72) 2689.72,6580.72 3074,6965 3074,7630.68 3926,8482.68 v2(3926,8877)
BLMK_LMX_SDO2: R227.2 U75.6 | length 7443.7
  L1_Top Layer w8.6: v2(2115.8,3237.26) R227.2@2115.8,3282.76
  L1_Top Layer w11: v2(3896,8900) 3896,8947 4014,9065 4014,9218 4059.84,9263.84 U75.6@4081.01,9263.84
  L10_Signal Layer 2 w6.5: v2(2115.8,3237.26) 1973,3380.06 1973,4266.87 2241,4534.87 2241,5290 2109,5422 2109,6563 2177,6631 2719,6631 2980,6892 2980,7566 3896,8482 v2(3896,8900)
BLMK_SCS: C427.2 J40.1 R429.2 R451.2 U24.18 | length 6790.7
  L1_Top Layer w8: 4452.16,4743.19 4454.95,4743.19
  L1_Top Layer w9.84: 4454.95,4743.21 4463.31,4751.58 U24.18@4463.31,4766.5
  L1_Top Layer w11: J40.1@3679.92,9690 3726.92,9643 R429.2@3874.5,9643 3916.5,9601 3993,9601 4057,9537 v2(4119,9537) 4176,9480 4492,9480 4606,9594 4606,9687 4824,9905 R451.2@4874.82,9905 ; v1(4410.47,4723.94) 4409.47,4723.94 4428.72,4743.19 4452.16,4743.19
  L10_Signal Layer 2 w6.5: v2(4119,9537) 4146.5,9509.5 4146.5,7441.5 4037,7332 4037,6862.32 4571,6328.32 4571,5777.64 4505,5711.64 4505,5187.1 4410.47,5092.57 v1(4410.47,4723.94)
  L12_Bottom Layer w11: C427.2@4409.97,4684.58 4410.47,4685.08 v1(4410.47,4723.94)
BLMX1_SCS: J40.3 R410.2 R430.2 R452.2 U19.24 | length 5852.7
  L1_Top Layer w8: v1(2227.18,6286.92) 2244.39,6269.72 U19.24@2244.39,6253.99
  L1_Top Layer w11: J40.3@3679.92,9590 3726.92,9543 R430.2@3874.5,9543 3927.5,9490 4002,9490 4032,9460 4500.96,9460 4637,9596.04 4637,9678 4801,9842 R452.2@4874.82,9842 R452.2@4871.82,9839 ; v2(3982,9323) 3998.5,9323 R410.2@4023,9347.5
  L10_Signal Layer 2 w6.5: v1(2227.18,6286.92) 2287.26,6347 2541.08,6347 3107,6912.92 3107,7621 3967.5,8481.5 3967.5,8905.82 3906.5,8966.82 3906.5,8967.5 3904,8970 3904,9468 v2(3928,9492)
  L12_Bottom Layer w11: v2(3928,9492) 3928,9377 v2(3982,9323)
BLMX2_SCS: J40.5 R431.2 R454.2 U21.24 | length 8221.1
  L1_Top Layer w8: U21.24@2307.23,3563.98 2307.23,3548.26 v1@2324.44,3531.05
  L1_Top Layer w11: J40.5@3679.92,9490 3726.92,9443 R431.2@3874.5,9443 3912.75,9404.75 4007.75,9404.75 4038,9435 4500,9435 4782,9717 R454.2@4874.82,9717
  L10_Signal Layer 2 w6.5: v1(2327.63,3534.25) 2398.91,3534.25 2465.72,3601.06 2465.72,3672.34 3116,4322.62 3116,5167.32 2862.18,5421.15 2862.18,6520.85 3276,6934.68 3276,7708 4010.5,8442.5 4010.5,9397.5 v2(4004,9404)
BUF_CLKIN_SEL0: J23.2 U23.13 U58.6 | length 958.8
  L1_Top Layer w11: v2(3303,4845) 3312,4845 3330.13,4863.13 U23.13@3330.13,4881.29 ; J23.2@3610.74,4639.66 3563,4591.92 3563,4259 3595.46,4226.54 U58.6@3662.32,4226.54
  L12_Bottom Layer w11: v2(3303,4845) 3460,4688 3562.39,4688 J23.2@3610.74,4639.66
BUF_CLKIN_SEL1: J23.1 U23.16 U58.7 | length 864.1
  L1_Top Layer w11: U23.16@3389.19,4881.29 3389.19,4859.81 3401,4848 v2(3413,4848) ; J23.1@3610.74,4739.66 3663,4687.39 3663,4388 3612,4337 3612,4268 3627.87,4252.13 U58.7@3662.32,4252.13
  L12_Bottom Layer w11: v2(3413,4848) 3450,4811 3539.39,4811 J23.1@3610.74,4739.66
CALTRG1: J7.1 R66.2 U8.E7 | length 1467.3
  L1_Top Layer w3.5: U8.E7@2413.91,8272.34 2398.08,8288.17 2398.08,8412.16 2424.32,8438.4 2424.32,8696.04 2515.2,8786.92
  L1_Top Layer w11: 2515.2,8786.92 2613.96,8885.68 3131.69,8885.68 v1(3237.92,8991.91)
  L12_Bottom Layer w11: J7.1@3221.08,9074.99 3237.92,9058.15 v1(3237.92,8991.91)
CALTRG2: J18.1 R147.2 U17.E7 | length 1520.9
  L1_Top Layer w3.5: U17.E7@2417.24,1926.34 2401.41,1942.18 2401.41,2066.16 2385.17,2082.4 2385.17,2197 2423.76,2235.59 2423.76,2348.53 2513.59,2438.37
  L1_Top Layer w11: 2513.59,2438.37 2614.91,2539.68 3184.3,2539.68 v1(3291.01,2646.38)
  L12_Bottom Layer w11: v1(3291.01,2646.38) J18.1@3291.01,2725.21
CLK1+*: C91.2 R73.2 T1.1 | length 147.7
  L1_Top Layer w6: T1.1@1828.98,8283 1870.29,8283 R73.2@1906.17,8247.12 1908.29,8245 C91.2@1960.92,8245
CLK1-*: C97.2 R73.1 T1.3 | length 141.1
  L1_Top Layer w6: T1.3@1828.98,8183 1889.29,8183 R73.1@1906.17,8199.88 1911.29,8205 C97.2@1960.92,8205
CLK2+*: C251.2 R154.2 T2.1 | length 147.7
  L1_Top Layer w6: T2.1@1832.31,1937 1873.62,1937 1910.2,1900.42 1911.62,1899 C251.2@1964.25,1899
CLK2-*: C257.2 R154.1 T2.3 | length 141.1
  L1_Top Layer w6: T2.3@1832.31,1837 1892.62,1837 1908.79,1853.18 1914.62,1859 C257.2@1964.25,1859
CLK-IN: R296.1 R392.2 T3.6 | length 125.6
  L1_Top Layer w11: v2(5290.37,4440) R392.2@5338.81,4488.44
  L12_Bottom Layer w11: R296.1@5251.46,4399 5290.37,4437.91 v2(5290.37,4440)
CLK-IN*: R301.2 R308.2 R392.1 R401.1 | length 78.1
  L1_Top Layer w11: R401.1@5357.19,4506.81 R308.2@5385,4479 5412.13,4451.87 R301.2@5412.5,4451.87
CLK_1+: C90.1 C91.1 C92.1 U8.F1 | length 227
  L1_Top Layer w6: v1(2008.17,8245) 2029.91,8245 2044.32,8230.59 2200.81,8230.59 2211.06,8240.84 U8.F1@2224.94,8240.84
CLK_1-: C93.1 C97.1 C99.1 U8.G1 | length 227.1
  L1_Top Layer w6: v1(2008.17,8205) 2029.91,8205 2044.51,8219.59 2200.81,8219.59 2211.06,8209.35 U8.G1@2224.94,8209.35
CLK_2+: C250.1 C251.1 C252.1 U17.F1 | length 227
  L1_Top Layer w6: v1(2011.5,1899) 2033.25,1899 2047.65,1884.6 2204.15,1884.6 2214.39,1894.85 U17.F1@2228.27,1894.85
CLK_2-: C253.1 C257.1 C259.1 U17.G1 | length 227.1
  L1_Top Layer w6: v1(2011.5,1859) 2033.25,1859 2047.84,1873.6 2204.15,1873.6 2214.39,1863.35 U17.G1@2228.27,1863.35
CLKIN0_N: C400.2 U24.38 | length 176.8
  L1_Top Layer w6: U24.38@4764.49,4890.51 4782.3,4890.51 4786.64,4886.17 4908.06,4886.17 4922.66,4900.77 C400.2@4933.42,4900.77
CLKIN0_P: C397.2 U24.37 | length 174.2
  L1_Top Layer w6: U24.37@4764.49,4870.83 4782.3,4870.83 4786.64,4875.17 4909.96,4875.17 4918.36,4866.77 C397.2@4933.42,4866.77
CLKIN1_N: C404.2 C405.2 U24.35 | length 191.9
  L1_Top Layer w6: U24.35@4764.49,4831.46 4782.3,4831.46 4786.64,4827.11 4808.45,4827.11 4846.56,4789 4867.61,4789 4880.62,4802.01 C405.2@4894.89,4802.01 4931.99,4802.01 C404.2@4932.98,4801.02
CLKIN1_P: C351.2 C403.2 U24.34 | length 193.1
  L1_Top Layer w6: U24.34@4764.49,4811.77 4782.3,4811.77 4786.64,4816.11 4803.89,4816.11 4842,4778 4867.61,4778 4880.62,4764.99 C351.2@4894.89,4764.99 4928.95,4764.99 C403.2@4932.98,4769.02
CLKIN_SEL0: R371.1 R599.2 U24.58 | length 5844.5
  L1_Top Layer w9.84: U24.58@4561.73,5112.95 v1(4561.73,5147.2)
  L1_Top Layer w11: v2(5023.09,5284.94) 5024.55,5286.39 R371.1@5069.53,5286.39
  L10_Signal Layer 2 w6.5: v2(4124,9954) 4124,9585 4162,9547 4162,7435 4052,7325 4052,6869 4584.5,6336.5 4584.5,5769.18 4518.5,5703.18 4518.5,5155.5 4526.8,5147.2 v1(4561.73,5147.2)
  L12_Bottom Layer w11: v2(4124,9954) 4198.09,9954 R599.2@4199.5,9954 ; v1(4561.73,5147.2) 4717.53,5303 5005.03,5303 v2(5023.09,5284.94)
CLKIN_SEL1: R370.1 R602.1 U24.59 | length 5645.5
  L1_Top Layer w9.84: v1(4541.47,5172.94) 4542.05,5172.36 U24.59@4542.05,5112.95
  L1_Top Layer w11: v2(4153,9810) 4154,9809 R602.1@4199.01,9809 ; v2(5021.56,5350.94) 5023.01,5352.39 R370.1@5067.99,5352.39
  L10_Signal Layer 2 w6.5: v2(4153,9810) 4153,9590 4175,9568 4175,7420 4072,7317 4072,6871.36 4597,6346.36 4597,5764 4531,5698 4531,5183.41 v1(4541.47,5172.94)
  L12_Bottom Layer w11: v1(4541.47,5172.94) 4694.47,5325.94 4996.56,5325.94 v2(5021.56,5350.94)
CLKINN: R309.1 R311.2 T3.3 | length 625.6
  L1_Top Layer w6: R309.1@5160.46,4776.4 v2(5181.92,4797.86)
  L12_Bottom Layer w6: T3.3@5105.64,4398.11 5105.51,4398.11 R311.2@5058.81,4444.81 5048.72,4454.9 5048.72,4518 5023,4543.72 5023,4759 5054.5,4790.5 5094.06,4790.5 5124.28,4760.28 5144.34,4760.28 v2(5181.92,4797.86)
CLKINN0: J27.1 R290.1 R291.2 | length 829
  L1_Top Layer w6: R290.1@5024.4,4900.77 R291.2@5060.72,4900.77
  L1_Top Layer w10: R291.2@5060.97,4901.02 5063.98,4898.02 5660.08,4898.02 5704.79,4942.72 J27.1@5704.79,5071.8
CLKINN1: C400.1 R290.2 | length 39
  L1_Top Layer w6: C400.1@4959.4,4900.77 R290.2@4998.42,4900.77
CLKINN*: C404.1 R305.1 R309.2 R312.2 R395.1 | length 218.8
  L1_Top Layer w6: C404.1@4958.96,4801.02 4969.46,4790.52 4985.51,4790.52 R312.2@4996,4801.01 5006.51,4790.5 5024.51,4790.5 R305.1@5032,4797.99 5046.27,4797.99 5053.76,4790.5 5094.06,4790.5 5111.67,4772.89 ; 5113.78,4770.78 5111.67,4772.89 ; R395.1@5142.09,4758.03 5131.44,4768.67 5115.89,4768.67 5111.67,4772.89
CLKINP: R296.2 R297.2 R302.1 T3.1 | length 589.2
  L1_Top Layer w6: v2(5078.92,4694.86) R302.1@5100.38,4716.32
  L12_Bottom Layer w6: v2(5078.92,4694.86) 5116.5,4732.44 5116.5,4752.5 5089.5,4779.5 5059.06,4779.5 5034,4754.44 5034,4548.28 5057,4525.28 5120.1,4525.28 R297.2@5130.19,4515.19 5130.19,4514.99 T3.1@5176.35,4468.82
CLKINP0: J26.1 R278.1 R281.2 | length 829.4
  L1_Top Layer w6: R278.1@5024.4,4866.77 R281.2@5060.73,4866.77
  L1_Top Layer w10: R281.2@5060.73,4866.77 R281.2@5060.97,4867.01 5063.98,4870.02 5659.92,4870.02 5704.79,4825.15 J26.1@5704.79,4696.07
CLKINP1: C397.1 R278.2 | length 39
  L1_Top Layer w6: C397.1@4959.4,4866.77 R278.2@4998.42,4866.77
CLKINP*: C403.1 R298.1 R302.2 R305.2 R399.1 | length 206.7
  L1_Top Layer w6: C403.1@4958.96,4769.02 4969.46,4779.52 4985.48,4779.52 R298.1@4996,4768.99 5006.51,4779.5 5024.51,4779.5 R305.2@5032,4772.01 5046.27,4772.01 5053.76,4779.5 5089.5,4779.5 5108.11,4760.89 5108.11,4745.34 R399.1@5118.75,4734.69
CLKOUT_TYPE0: J23.4 U23.9 U58.4 | length 997.6
  L1_Top Layer w11: v2(3238,4849) 3251.39,4862.39 U23.9@3251.39,4881.29 ; v2(3604,4175) 3604.36,4175.36 U58.4@3662.32,4175.36
  L12_Bottom Layer w11: v2(3238,4849) 3238,4779 3326,4691 3377,4691 3480,4588 3542,4588 3563,4567 3563,4473.92 J23.4@3604,4432.92 ; v2(3604,4175) 3610.74,4181.74 J23.4@3610.74,4439.66
CLKOUT_TYPE1: J23.3 U23.32 U58.5 | length 1469.4
  L1_Top Layer w11: v2(3232,5146) 3232,5123 3251.39,5103.61 U23.32@3251.39,5070.26 ; U58.5@3662.32,4200.95 3663.37,4202 v2(3735,4202)
  L12_Bottom Layer w11: v2(3232,5146) 3433,5146 3508,5071 3508,4925 3662,4771 3662,4590.92 J23.3@3610.74,4539.66 3660.74,4489.66 3660.74,4276.26 v2(3735,4202)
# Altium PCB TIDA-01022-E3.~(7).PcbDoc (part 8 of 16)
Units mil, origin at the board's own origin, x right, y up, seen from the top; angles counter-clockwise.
Board outline 6929.13 x 11614.17 mil, 12 copper layers (L1_Top Layer, L2_GND, L3_GND, L4_Signal Layer 1, L5_GND, L6_PWR, L7_GND/PWR, L8_PWR, L9_GND/PWR, L10_Signal Layer 2, L11_GND, L12_Bottom Layer), stack 64.6 mil thick; 1733 components, 993 nets, 5987 pads, 3555 vias.

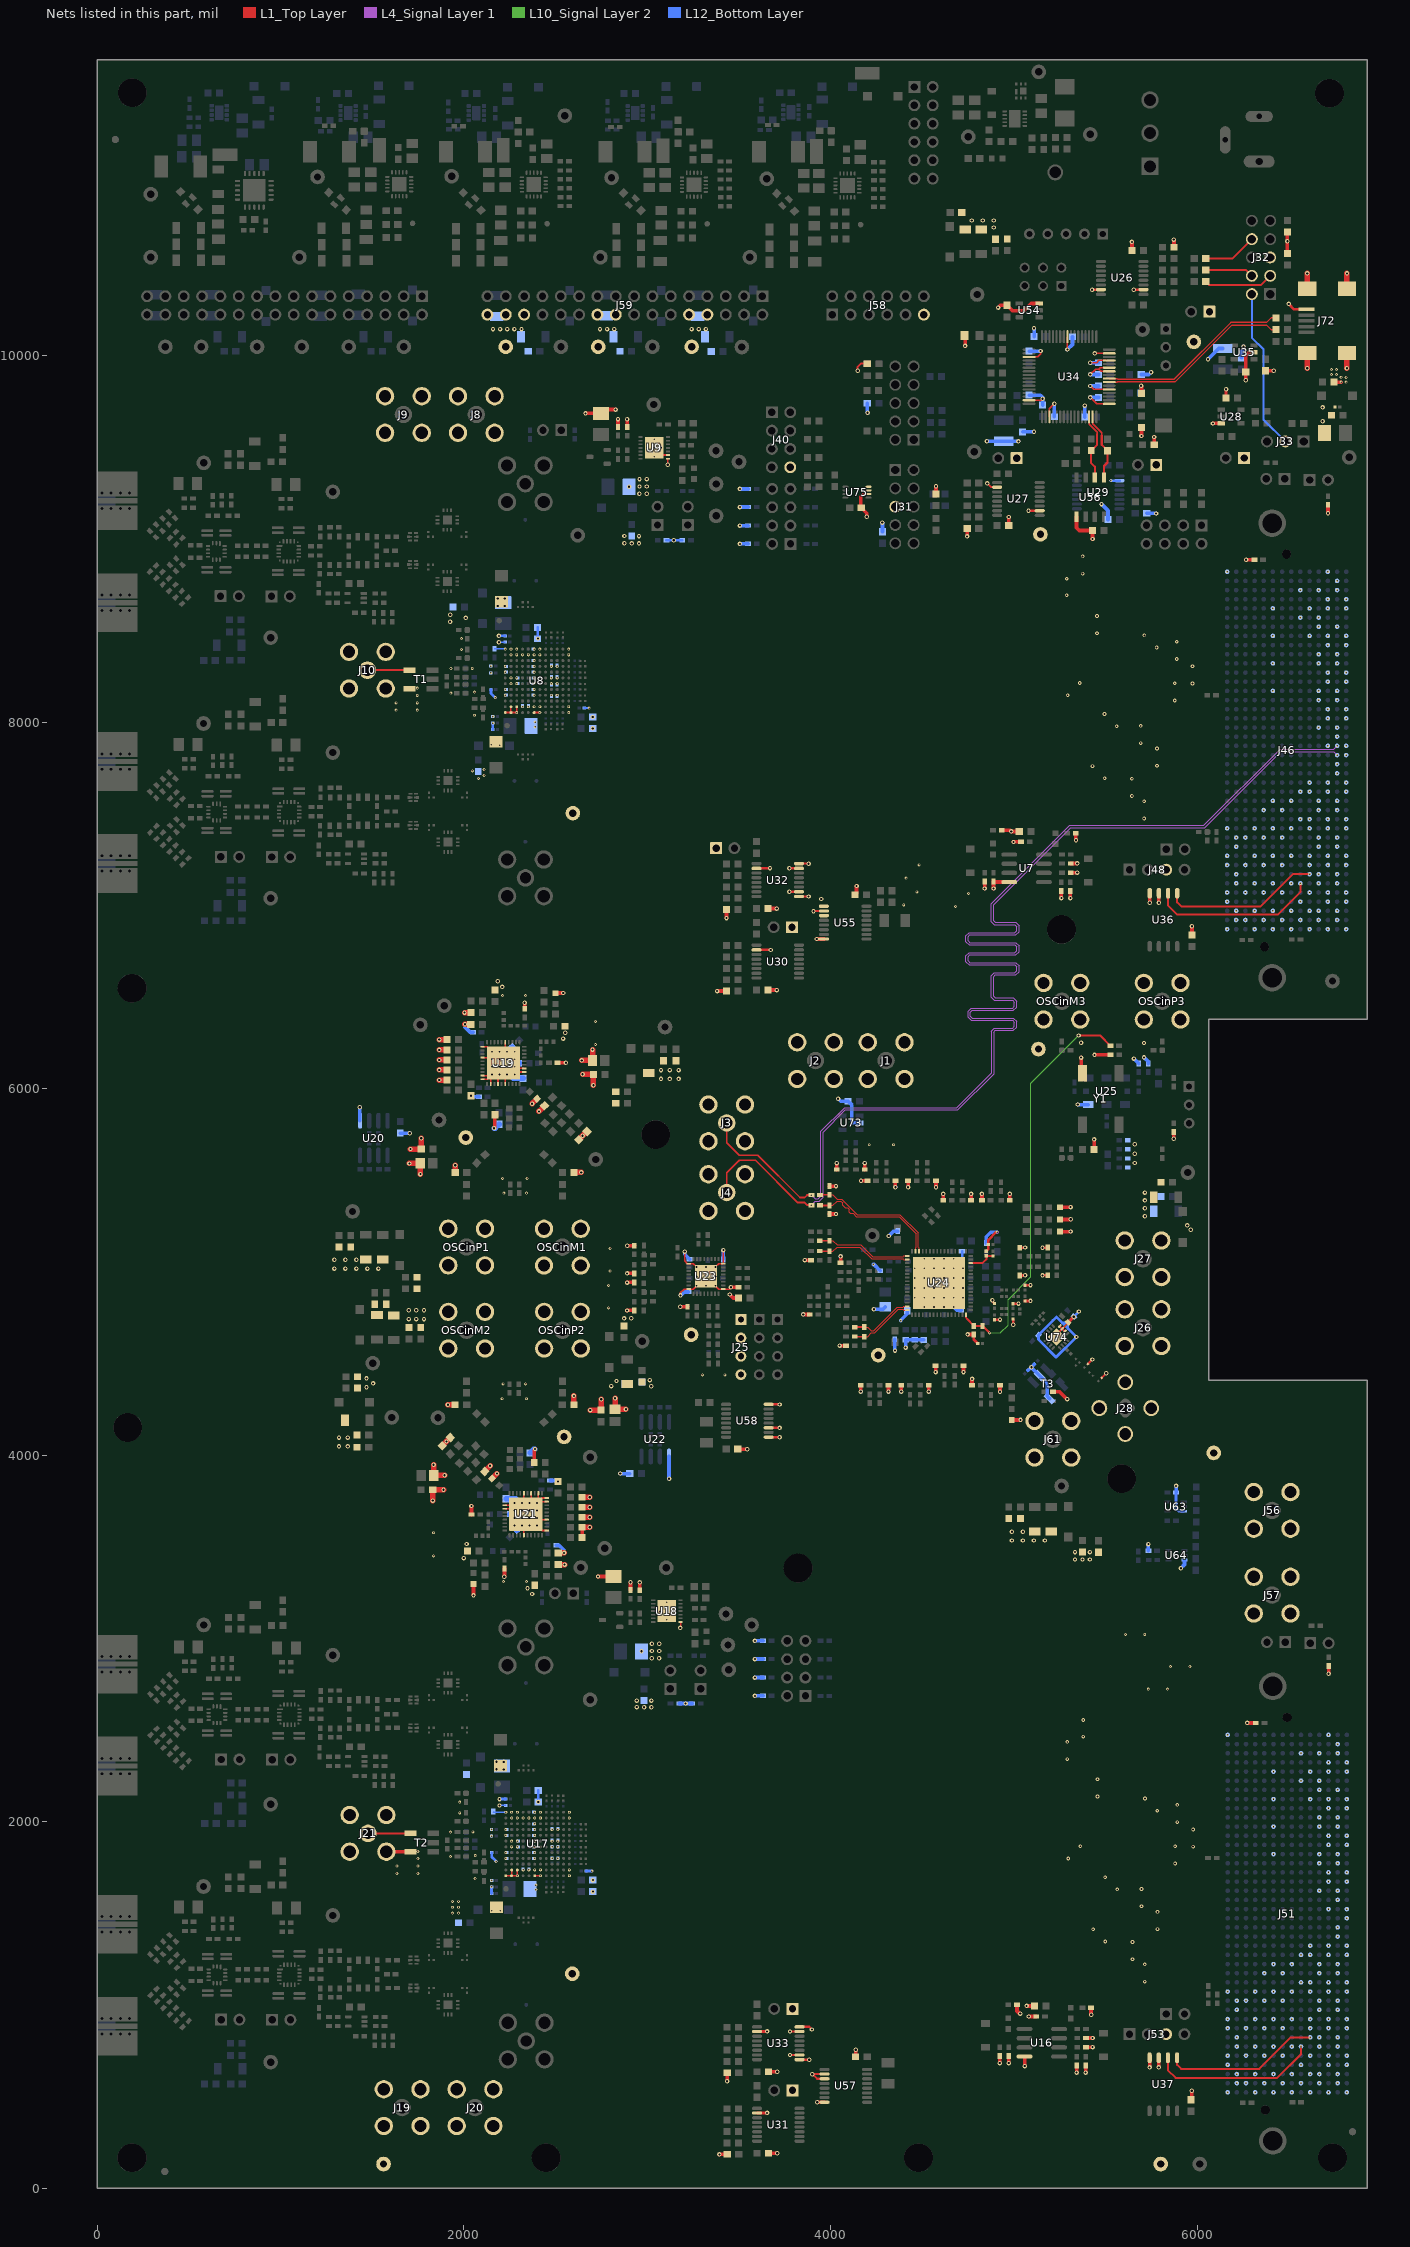
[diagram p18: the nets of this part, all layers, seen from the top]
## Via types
v1: diameter 16, hole 8, L1_Top Layer to L12_Bottom Layer, tented both sides, 1686 vias
v2: diameter 24, hole 12, L1_Top Layer to L12_Bottom Layer, tented both sides, 1590 vias
v3: diameter 20, hole 10, L1_Top Layer to L12_Bottom Layer, 279 vias

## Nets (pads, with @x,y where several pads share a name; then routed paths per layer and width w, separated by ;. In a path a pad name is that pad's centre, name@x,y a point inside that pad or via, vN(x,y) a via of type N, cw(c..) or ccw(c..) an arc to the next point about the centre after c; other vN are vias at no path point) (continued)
CPOUT1: C398.2 C399.2 R359.2 U24.32 | length 2235.7
  L1_Top Layer w9.84: U24.32@4738.9,4766.5 4738.9,4749.51 4745,4743.41
  L1_Top Layer w11: 4745,4743.41 4780.97,4707.44 C399.2@4780.97,4705.64 C398.2@4828.97,4705.64 4867.61,4667 v1(4867.89,4667) ; v2(5353,6290) 5470.82,6290 R359.2@5526.87,6233.95
  L10_Signal Layer 2 w6.5: v1(4867.89,4667) 4925,4667 4968,4710 4968,4848 5093,4973 5093,6030 v2(5353,6290)
CPOUT2: C393.1 C395.1 U24.46 | length 149.5
  L1_Top Layer w9.84: U24.46@4764.49,5047.99 4800,5047.99
  L1_Top Layer w11: 4800,5047.99 4828.53,5047.99 4849.35,5068.82 C395.1@4849.35,5087.47 4885.94,5087.47 C393.1@4886.47,5086.95
DCLKOUT0+: C394.1 R274.2 U24.1 | length 515.3
  L1_Top Layer w6: C394.1@3941.09,5169.44 C394.1@3942.02,5170.37 ; R274.2@3993.95,5170.37 4011.76,5170.37 4035.14,5146.99 4164.9,5146.99 4228.87,5083.02 4395.88,5083.02 4400.22,5087.36 U24.1@4418.03,5087.36
  L1_Top Layer w10: C394.1@3942.02,5170.37 R274.2@3993.95,5170.37
DCLKOUT0-: C396.1 R273.2 U24.2 | length 515.7
  L1_Top Layer w6: C396.1@3941.09,5114.44 C396.1@3942.92,5112.61 ; R273.2@3993.95,5112.61 4011.76,5112.61 4035.14,5135.99 4160.34,5135.99 4224.31,5072.02 4395.88,5072.02 4400.22,5067.68 U24.2@4418.03,5067.68
  L1_Top Layer w10: C396.1@3942.92,5112.61 R273.2@3993.95,5112.61
DCLKOUT2+: C401.1 R289.2 U24.15 | length 350.8
  L1_Top Layer w6: C401.1@4131.63,4698.08 C401.1@4133.01,4699.46 ; R289.2@4184.01,4699.46 4201.82,4699.46 4222.7,4678.58 4235.89,4678.58 4364.74,4807.43 4395.88,4807.43 4400.22,4811.77 U24.15@4418.03,4811.77
  L1_Top Layer w10: C401.1@4133.01,4699.46 R289.2@4184.01,4699.46
DCLKOUT2-: C402.1 R288.2 U24.16 | length 350.8
  L1_Top Layer w6: C402.1@4131.63,4648.08 C402.1@4133.01,4646.7 ; R288.2@4184.01,4646.7 4201.82,4646.7 4222.7,4667.58 4240.45,4667.58 4369.3,4796.43 4395.88,4796.43 4400.22,4792.09 U24.16@4418.03,4792.09
  L1_Top Layer w10: C402.1@4133.01,4646.7 R288.2@4184.01,4646.7
DCLKOUT12+: C413.1 R365.2 U24.62 | length 722.2
  L1_Top Layer w6: R365.2@3994.28,5420.88 4012.09,5420.88 4035.47,5397.5 4061.39,5397.5 4145.89,5313 4378.45,5313 4478.65,5212.79 4478.65,5135.11 4482.99,5130.76 U24.62@4482.99,5112.95
  L1_Top Layer w10: C413.1@3944.28,5420.88 R365.2@3994.28,5420.88
DCLKOUT12-: C415.1 R364.2 U24.63 | length 722.2
  L1_Top Layer w6: R364.2@3994.28,5363.13 4012.09,5363.13 4035.47,5386.5 4056.83,5386.5 4066.33,5377 4066.33,5363.17 4079.08,5350.42 4092.92,5350.42 4101.36,5341.97 4101.36,5324.64 4107.08,5318.92 4124.42,5318.92 4141.33,5302 4373.89,5302 4467.65,5208.24 4467.65,5135.11 4463.31,5130.76 U24.63@4463.31,5112.95
  L1_Top Layer w10: C415.1@3944.28,5363.13 R364.2@3994.28,5363.13
DCLKOUT12_N: C415.2 J4.1 J46.Z21 | length 7334.6
  L1_Top Layer w10: J4.1@3433.66,5432.82 3433.66,5433.02 3433.66,5540.29 3502.19,5608.82 ; 3502,5609.02 3590.48,5609.02 3821.5,5378 3858.41,5378 3871.91,5364.5 v1(3895.66,5364.5)
  L4_Signal Layer 1 w4.9: v1(3895.66,5364.5) 3917.16,5386 3937.97,5386 3959,5407.03 3959,5762 4081,5884 4694,5884 4889,6079 4889,6307.64 4899.21,6317.85 4997.76,6317.85 5015,6335.09 5015,6367.51 4997.76,6384.75 4773.21,6384.75 4763,6394.96 4763,6417.44 4773.21,6427.65 4997.76,6427.65 5015,6444.89 5015,6477.31 4997.76,6494.55 4899.21,6494.55 4889,6504.76 4889,6586.44 4889,6609.84 4899.21,6620.05 5010.76,6620.05 5028,6637.29 5028,6669.71 5010.76,6686.95 4760.21,6686.95 4750,6697.16 4750,6719.64 4760.21,6729.85 5010.76,6729.85 5028,6747.09 5028,6779.51 5010.76,6796.75 4760.21,6796.75 4750,6806.96 4750,6829.44 4760.21,6839.65 5010.76,6839.65 5028,6856.89 5028,6889.31 5010.76,6906.55 4899.21,6906.55 4889,6916.76 4889,7004 5309,7424 6042,7424 6457.01,7839.01 6744.11,7839.01 v1(6763.11,7820.01)
DCLKOUT12_P: C413.2 J3.1 J46.Z20 | length 7334.6
  L1_Top Layer w10: J3.1@3433.66,5812.82 3433.66,5705.35 3502,5637.02 ; 3502.19,5636.82 3502,5637.02 ; v1(3895.66,5419.5) 3871.91,5419.5 3858.41,5406 3833.09,5406 3602.08,5637.02 3502,5637.02
  L4_Signal Layer 1 w4.9: v1(3895.66,5419.5) 3917.16,5398 3933,5398 3947,5412 3947,5766.97 4076.03,5896 4689.03,5896 4877,6083.97 4877,6312.61 4894.24,6329.85 4992.79,6329.85 5003,6340.06 5003,6362.54 4992.79,6372.75 4768.24,6372.75 4751,6389.99 4751,6422.41 4768.24,6439.65 4992.79,6439.65 5003,6449.86 5003,6472.34 4992.79,6482.55 4894.24,6482.55 4877,6499.79 4877,6586.44 4877,6614.81 4894.24,6632.05 5005.79,6632.05 5016,6642.26 5016,6664.74 5005.79,6674.95 4755.24,6674.95 4738,6692.19 4738,6724.61 4755.24,6741.85 5005.79,6741.85 5016,6752.06 5016,6774.54 5005.79,6784.75 4755.24,6784.75 4738,6801.99 4738,6834.41 4755.24,6851.65 5005.79,6851.65 5016,6861.86 5016,6884.34 5005.79,6894.55 4894.24,6894.55 4877,6911.79 4877,7008.97 5304.03,7436 6037.03,7436 6452.04,7851.01 6744.11,7851.01 v1(6763.11,7870.01)
DEVCLKIN1: J10.1 T1.6 | length 230.8
  L1_Top Layer w11: J10.1@1473.08,8282.9 1473.18,8283 T1.6@1703.79,8283
DEVCLKIN2: J21.1 T2.6 | length 230.6
  L1_Top Layer w11: J21.1@1476.51,1937 T2.6@1707.12,1937
DGND: C69.1 C70.2 C74.1 C82.1 C83.1 C107.2 C108.2 C109.2 C119.2 C120.2 C121.2 C122.2 C123.2 C124.2 C125.2 C126.2 C127.2 C128.2 C129.2 C130.2 C131.2 C132.2 C133.2 C134.2 C135.2 C136.2 C137.2 C138.2 C139.2 C140.2 C141.2 C142.2 C143.2 C144.2 C145.2 C146.2 C147.2 C148.2 C149.2 C150.2 C151.2 C152.2 C153.2 C154.2 C155.2 C156.2 C157.2 C158.2 C159.2 C160.2 C229.1 C230.2 C234.1 C242.1 C243.1 C267.2 C268.2 C269.2 C279.2 C280.2 C281.2 C282.2 C283.2 C284.2 C285.2 C286.2 C287.2 C288.2 C289.2 C290.2 C291.2 C292.2 C293.2 C294.2 C295.2 C296.2 C297.2 C298.2 C299.2 C300.2 C301.2 C302.2 C303.2 C304.2 C305.2 C306.2 C308.1 C309.2 C310.2 C311.2 C312.2 C313.2 C314.2 C315.2 C316.2 C317.2 C318.2 C319.2 C320.2 C322.1 C323.1 C324.1 C326.2 C327.1 C328.1 C329.1 C330.1 C331.1 C332.1 C333.1 C335.1 C336.2 C338.1 C339.2 C340.1 C342.2 C343.1 C344.2 C345.2 C346.1 C347.1 C350.1 C351.1 C352.1 C353.1 C354.1 C356.2 C357.1 C358.1 C359.1 C360.1 C361.1 C362.1 C363.1 C365.1 C366.2 C368.1 C369.2 C370.1 C372.2 C373.1 C374.2 C375.2 C376.1 C377.1 C380.1 C381.2 C382.2 C383.2 C384.2 C385.1 C386.2 C387.1 C388.2 C389.2 C390.2 C395.2 C399.1 C405.1 C406.1 C409.1 C411.1 C412.1 C414.1 C416.1 C417.1 C418.1 C419.1 C420.2 C421.2 C422.2 C423.1 C424.1 C425.1 C426.1 C427.1 C428.2 C429.2 C430.2 C431.2 C432.2 C433.2 C434.2 C435.2 C436.1 C437.1 C438.1 C439.2 C440.2 C441.1 C442.1 C443.1 C444.1 C445.1 C446.1 C447.1 C448.1 C449.1 C450.1 C451.1 C452.1 C453.1 C454.1 C455.1 C456.1 C457.2 C458.1 C459.1 C460.1 C461.1 C462.1 C463.1 C464.1 C465.1 C466.2 C467.1 C468.1 C469.1 C470.2 C471.2 C472.1 C473.2 C474.2 C475.2 C476.2 C482.2 C483.2 C484.2 C485.2 C486.2 C487.1 C488.2 C489.1 C508.2 C511.2 C512.1 C528.2 C529.2 C530.2 C531.2 C532.1 C533.1 C534.1 C535.1 C536.1 C542.1 C543.1 C545.2 C546.1 C547.2 C548.1 C549.2 C550.1 C551.2 C552.1 C553.1 C554.1 C555.1 C556.1 C577.1 C578.1 C579.1 C580.1 C581.1 C582.1 C596.2 C597.2 C598.1 C599.2 C605.2 C606.1 C607.2 C609.2 C610.2 C611.1 C612.2 C622.2 C623.1 C624.2 C625.2 C626.2 C627.1 C628.2 C629.2 C630.2 C631.1 C632.2 C633.2 C634.2 C635.1 C636.2 C736.2 C737.1 C738.1 C739.2 C740.2 C741.1 D11.2 D12.2 D13.2 D14.2 D15.2 D16.2 D18.1 J1.2 J1.3 J1.4 J1.5 J2.2 J2.3 J2.4 J2.5 J3.2 J3.3 J3.4 J3.5 J4.2 J4.3 J4.4 J4.5 J8.2 J8.3 J8.4 J8.5 J9.2 J9.3 J9.4 J9.5 J10.2 J10.3 J10.4 J10.5 J19.2 J19.3 J19.4 J19.5 J20.2 J20.3 J20.4 J20.5 J21.2 J21.3 J21.4 J21.5 J25.1 J25.2 J25.3 J25.4 J26.2 J26.3 J26.4 J26.5 J27.2 J27.3 J27.4 J27.5 J28.2 J28.3 J28.4 J28.5 J31.5 J32.5 J35.1 J36.1 J37.1 J38.1 J40.8 J41.1 J42.1 J43.1 J44.1 J46.A1 J46.A4 J46.A5 J46.A8 J46.A9 J46.A12 J46.A13 J46.A16 J46.A17 J46.A20 J46.A24 J46.A25 J46.A28 J46.A29 J46.A32 J46.A33 J46.A36 J46.A37 J46.A40 J46.B3 J46.B6 J46.B7 J46.B10 J46.B11 J46.B14 J46.B15 J46.B18 J46.B26 J46.B27 J46.B30 J46.B31 J46.B34 J46.B35 J46.B38 J46.B39 J46.C5 J46.C8 J46.C24 J46.C25 J46.C28 J46.C29 J46.C32 J46.C33 J46.C36 J46.C38 J46.C40 J46.D3 J46.D6 J46.D25 J46.D28 J46.D37 J46.D39 J46.E26 J46.E29 J46.E32 J46.E35 J46.E38 J46.E40 J46.F27 J46.F30 J46.F33 J46.F36 J46.F39 J46.G5 J46.G8 J46.G11 J46.G14 J46.G26 J46.G29 J46.G32 J46.G35 J46.G38 J46.G40 J46.H27 J46.H30 J46.H33 J46.H36 J46.H39 J46.J29 J46.J32 J46.J35 J46.J38 J46.J40 J46.K30 J46.K33 J46.K36 J46.K39 J46.L30 J46.L31 J46.L34 J46.L35 J46.L38 J46.L39 J46.M1 J46.M29 J46.M32 J46.M33 J46.M36 J46.M37 J46.M40 J46.Y4 J46.Y5 J46.Y8 J46.Y9 J46.Y12 J46.Y13 J46.Y16 J46.Y17 J46.Y20 J46.Y21 J46.Y24 J46.Y25 J46.Y28 J46.Y29 J46.Y32 J46.Y33 J46.Y36 J46.Y37 J46.Y40 J46.Z2 J46.Z3 J46.Z7 J46.Z10 J46.Z11 J46.Z14 J46.Z15 J46.Z18 J46.Z19 J46.Z22 J46.Z23 J46.Z26 J46.Z27 J46.Z30 J46.Z31 J46.Z34 J46.Z35 J46.Z38 J46.Z39 J48.3 J51.A1 J51.A4 J51.A5 J51.A8 J51.A9 J51.A12 J51.A13 J51.A16 J51.A17 J51.A20 J51.A24 J51.A25 J51.A28 J51.A29 J51.A32 J51.A33 J51.A36 J51.A37 J51.A40 J51.B3 J51.B6 J51.B7 J51.B10 J51.B11 J51.B14 J51.B15 J51.B18 J51.B26 J51.B27 J51.B30 J51.B31 J51.B34 J51.B35 J51.B38 J51.B39 J51.C5 J51.C8 J51.C24 J51.C25 J51.C28 J51.C29 J51.C32 J51.C33 J51.C36 J51.C38 J51.C40 J51.D3 J51.D6 J51.D25 J51.D28 J51.D37 J51.D39 J51.E26 J51.E29 J51.E32 J51.E35 J51.E38 J51.E40 J51.F27 J51.F30 J51.F33 J51.F36 J51.F39 J51.G5 J51.G8 J51.G11 J51.G14 J51.G26 J51.G29 J51.G32 J51.G35 J51.G38 J51.G40 J51.H27 J51.H30 J51.H33 J51.H36 J51.H39 J51.J29 J51.J32 J51.J35 J51.J38 J51.J40 J51.K30 J51.K33 J51.K36 J51.K39 J51.L30 J51.L31 J51.L34 J51.L35 J51.L38 J51.L39 J51.M1 J51.M29 J51.M32 J51.M33 J51.M36 J51.M37 J51.M40 J51.Y4 J51.Y5 J51.Y8 J51.Y9 J51.Y12 J51.Y13 J51.Y16 J51.Y17 J51.Y20 J51.Y21 J51.Y24 J51.Y25 J51.Y28 J51.Y29 J51.Y32 J51.Y33 J51.Y36 J51.Y37 J51.Y40 J51.Z2 J51.Z3 J51.Z7 J51.Z10 J51.Z11 J51.Z14 J51.Z15 J51.Z18 J51.Z19 J51.Z22 J51.Z23 J51.Z26 J51.Z27 J51.Z30 J51.Z31 J51.Z34 J51.Z35 J51.Z38 J51.Z39 J53.3 J56.2 J56.3 J56.4 J56.5 J57.2 J57.3 J57.4 J57.5 J58.11 J59.8 J59.10 J59.18 J59.20 J59.28 J59.30 J59.32 J61.2 J61.3 J61.4 J61.5 J72.5 J72.Shell L93.2 L94.2 L95.2 L96.2 OSCinM1.2 OSCinM1.3 OSCinM1.4 OSCinM1.5 OSCinM2.2 OSCinM2.3 OSCinM2.4 OSCinM2.5 OSCinM3.2 OSCinM3.3 OSCinM3.4 OSCinM3.5 OSCinP1.2 OSCinP1.3 OSCinP1.4 OSCinP1.5 OSCinP2.2 OSCinP2.3 OSCinP2.4 OSCinP2.5 OSCinP3.2 OSCinP3.3 OSCinP3.4 OSCinP3.5 R50.1 R51.1 R52.2 R53.2 R58.2 R59.2 R60.1 R61.1 R62.1 R65.1 R66.1 R72.1 R131.1 R132.1 R133.2 R134.2 R139.2 R140.2 R141.1 R142.1 R143.1 R146.1 R147.1 R153.1 R166.1 R174.2 R179.2 R181.2 R182.2 R183.2 R186.2 R189.2 R202.1 R220.2 R223.2 R224.2 R230.2 R243.1 R258.1 R259.1 R268.1 R269.1 R272.1 R275.1 R281.1 R284.1 R285.2 R287.1 R291.1 R297.1 R298.2 R303.2 R307.1 R308.1 R311.1 R312.1 R319.1 R328.1 R329.1 R330.1 R331.1 R332.1 R333.1 R334.1 R335.1 R336.1 R337.1 R338.1 R339.1 R341.1 R347.1 R348.1 R351.1 R362.1 R363.1 R364.1 R365.1 R366.1 R367.1 R368.1 R397.1 R469.1 R475.1 R476.1 R480.1 R481.1 R542.2 R593.2 R594.2 R595.1 R596.1 R598.2 R600.1 T1.4 T2.4 T3.2 T3.4 TP16.1 TP27.1 TP30.1 TP65.1 TP66.1 TP67.1 TP68.1 TP69.1 TP70.1 TP71.1 TP72.1 TP73.1 TP74.1 TP75.1 TP76.1 U7.4 U8.A1 U8.A2 U8.A3 U8.A6 U8.A7 U8.A12 U8.B2 U8.B3 U8.B4 U8.B5 U8.B6 U8.B7 U8.B12 U8.C6 U8.D1 U8.D6 U8.D9 U8.D10 U8.E1 U8.E6 U8.F2 U8.F3 U8.F6 U8.F9 U8.F10 U8.G2 U8.G3 U8.G6 U8.G9 U8.G10 U8.H1 U8.H6 U8.J1 U8.J6 U8.J9 U8.J10 U8.L2 U8.L3 U8.L4 U8.L5 U8.L6 U8.L7 U8.L12 U8.M1 U8.M2 U8.M3 U8.M6 U8.M7 U8.M12 U9.8 U9.9 U9.15 U16.4 U17.A1 U17.A2 U17.A3 U17.A6 U17.A7 U17.A12 U17.B2 U17.B3 U17.B4 U17.B5 U17.B6 U17.B7 U17.B12 U17.C6 U17.D1 U17.D6 U17.D9 U17.D10 U17.E1 U17.E6 U17.F2 U17.F3 U17.F6 U17.F9 U17.F10 U17.G2 U17.G3 U17.G6 U17.G9 U17.G10 U17.H1 U17.H6 U17.J1 U17.J6 U17.J9 U17.J10 U17.L2 U17.L3 U17.L4 U17.L5 U17.L6 U17.L7 U17.L12 U17.M1 U17.M2 U17.M3 U17.M6 U17.M7 U17.M12 U18.8 U18.15 U19.2 U19.4 U19.6 U19.13 U19.14 U19.25 U19.31 U19.34 U19.39 U19.40 U19.41 U20.5 U21.2 U21.4 U21.6 U21.13 U21.14 U21.25 U21.31 U21.34 U21.39 U21.40 U21.41 U22.5 U23.1 U23.8 U23.17 U23.24 U23.33 U24.65 U25.3@5405.97,5913 U26.7 U26.10 U27.2 U27.10 U28.3 U29.10 U30.10 U31.10 U32.1 U32.2 U32.7 U32.8 U32.10 U33.1 U33.2 U33.7 U33.8 U33.10 U34.1 U34.5 U34.10 U34.11 U34.13 U34.15 U34.25 U34.35 U34.47 U34.51 U35.2 U36.3 U36.4 U37.3 U37.4 U54.3 U55.1 U55.2 U55.3 U55.8 U56.5 U57.2 U57.3 U57.8 U58.1 U58.3 U58.8 U63.3 U64.3 U73.2 U74.6 U74.7 U74.8 U74.17 U75.2 U75.3 U75.4 Y1.2 | length 21236.5
  L1_Top Layer w8: U17.M1@2228.27,1705.87 U17.M2@2259.76,1705.87 ; U8.M2@2256.43,8051.87 U8.L2@2256.43,8083.36 ; U17.L2@2259.76,1737.37 U17.M2@2259.76,1705.87 ; v1(2287.93,8051.87) U8.L3@2287.93,8083.36 ; U17.L3@2291.26,1737.37 v1(2291.26,1705.87) U17.M2@2259.76,1705.87 ; v2(3111.65,9403.6) 3112.29,9403.6 3112.97,9404.28 U9.8@3112.97,9436.53 ; v2(3179.98,3057.83) 3180.62,3057.83 3181.3,3058.51 U18.8@3181.3,3090.76 ; v2(3181,4872) 3181,4887 3200.88,4906.88 U23.8@3225.8,4906.88 3251.39,4906.88 v3(3269.11,4924.59) v3(3320.29,4975.78) ; v2(3204,5111) 3204,5060 3219.33,5044.67 U23.1@3225.8,5044.67 3251.39,5044.67 v3(3269.11,5026.96) v3(3320.29,4975.78) ; v2(3415,5119) 3415,5044.9 U23.24@3414.78,5044.67 3389.19,5044.67 v3(3371.47,5026.96) v3(3320.29,4975.78) ; v2(3456,4916.5) 3446.38,4906.88 U23.17@3414.78,4906.88 3389.19,4906.88 v3(3371.47,4924.59) v3(3320.29,4975.78) ; U34.47@5083.38,9756.02 5148.89,9756.02 v2(5156.87,9764) ; U34.35@5083.38,9992.24 5129.64,9992.24 5145.87,10008.47 v2(5145.87,10024.47) ; U34.51@5193.62,9665.47 5193.62,9709.22 v2(5220.87,9736.47) ; v2(5291.87,10032.47) 5292.04,10032.64 U34.25@5292.04,10102.47 ; v2(5416.87,9771.47) 5452.01,9736.33 U34.1@5520.39,9736.33 ; v2(5416.87,9833.47) 5435.27,9815.07 U34.5@5520.39,9815.07 ; v2(5416.87,9896.47) 5445.87,9925.47 5463.87,9925.47 ; v2(5416.87,9960.47) 5451.87,9960.47 5463.95,9972.55 U34.13@5520.39,9972.55 ; v2(5440.87,10011.47) 5441.32,10011.92 U34.15@5520.39,10011.92 ; U34.10@5520.39,9913.5 5475.84,9913.5 5463.87,9925.47 ; U34.11@5520.39,9933.18 5471.58,9933.18 5463.87,9925.47
  L1_Top Layer w9: U19.40@2100.68,6051.23 2126.28,6051.23 U19.41@2145.96,6070.92 ; U19.39@2100.68,6070.92 U19.41@2145.96,6070.92 ; U19.34@2100.68,6169.34 2153.06,6169.34 2156.59,6169.34 U19.41@2185.33,6169.34 ; U19.31@2100.68,6228.4 2126.28,6228.4 v3(2153.06,6201.62) U19.41@2185.33,6169.34 ; U19.2@2145.96,6025.64 U19.41@2145.96,6070.92 ; U19.4@2185.33,6025.64 U19.41@2185.33,6110.29 ; U21.14@2222.59,3707.69 U21.41@2307.23,3707.69 ; U21.13@2222.59,3727.37 2287.55,3727.37 U21.41@2307.23,3707.69 ; U19.6@2224.7,6025.64 U19.41@2224.7,6129.97 ; U19.25@2224.7,6253.99 2224.7,6149.66 U19.41@2214.86,6139.82 ; U21.25@2326.92,3563.98 2326.92,3668.32 U21.41@2336.76,3678.16 ; U21.6@2326.92,3792.33 U21.41@2326.92,3688 ; U19.13@2329.03,6090.6 2264.07,6090.6 U19.41@2244.39,6110.29 ; U19.14@2329.03,6110.29 U19.41@2244.39,6110.29 ; U21.4@2366.29,3792.33 U21.41@2366.29,3707.69 ; U21.2@2405.66,3792.33 U21.41@2405.66,3747.06 ; U21.31@2450.93,3589.58 2425.34,3589.58 U21.41@2366.29,3648.63 ; U21.34@2450.93,3648.63 U21.41@2366.29,3648.63 ; U21.39@2450.93,3747.06 U21.41@2405.66,3747.06 ; U21.40@2450.93,3766.74 2425.34,3766.74 U21.41@2405.66,3747.06 ; U19.41@2145.96,6070.92 v3(2153.06,6078.01) U19.41@2185.33,6110.29 ; U19.41@2185.33,6110.29 v3(2194.26,6119.22) U19.41@2214.86,6139.82 ; U19.41@2185.33,6169.34 U19.41@2214.86,6139.82 ; U19.41@2214.86,6139.82 U19.41@2224.7,6129.97 ; U19.41@2224.7,6129.97 v3(2235.46,6119.22) U19.41@2244.39,6110.29 ; U21.41@2307.23,3707.69 U21.41@2326.92,3688 ; U21.41@2326.92,3688 U21.41@2336.76,3678.16 ; U21.41@2336.76,3678.16 v3(2357.36,3657.56) U21.41@2366.29,3648.63 ; U21.41@2336.76,3678.16 v3(2357.36,3698.76) U21.41@2366.29,3707.69 ; U21.41@2366.29,3707.69 U21.41@2405.66,3747.06
  L1_Top Layer w10: U8.M1@2224.94,8051.87 U8.M2@2256.43,8051.87 v1(2287.93,8051.87) ; U17.M6@2385.75,1705.87 v1(2417.24,1705.87)
  L1_Top Layer w11: U8.M6@2382.42,8051.87 v1(2413.91,8051.87) ; v1(3038.17,9495.58) 3077.54,9456.21 U9.9@3112.97,9456.21 ; v2(3907,6968) 3908.49,6969.49 U55.2@3963.68,6969.49 ; v2(4148,9917) 4148,9938 4165,9955 R598.2@4200.5,9955 ; 4165,9230 4179.16,9244.16 U75.2@4206.99,9244.16 ; v2(4855,9302) 4875.82,9281.18 U27.10@4908.68,9281.18 ; v2(5232.63,4644.71) 5232.63,4658.63 U74.7@5264.65,4690.65 ; U74.8@5250.73,4704.57 U74.7@5264.65,4690.65 ; U74.6@5278.57,4676.73 U74.7@5264.65,4690.65 ; C512.1@5296,4725 5296,4722 U74.7@5264.65,4690.65
  L1_Top Layer w12: v2(3775.15,7074.01) 3775.21,7073.95 U32.2@3827.61,7073.95 ; v2(3775.15,7201.96) 3775.21,7201.9 U32.7@3827.61,7201.9 ; v2(3778.48,728.02) 3778.54,727.96 U33.2@3830.94,727.96 ; v2(3778.48,855.97) 3778.54,855.91 U33.7@3830.94,855.91 ; U32.1@3827.61,7048.36 3880.01,7048.36 v2(3880.07,7048.3) ; U32.8@3827.61,7227.49 3880.01,7227.49 v2(3880.07,7227.43) ; U33.1@3830.94,702.36 3883.34,702.36 v2(3883.4,702.3) ; U33.8@3830.94,881.5 3883.34,881.5 v2(3898,866.84) ; U57.3@3967.01,597.9 3926.83,597.9 3901.23,623.49 U57.2@3967.01,623.49 ; R308.1@5403.37,4497.37 v2(5428.19,4522.19) ; R307.1@5479.37,4422.37 v2(5504.19,4447.19)
  L1_Top Layer w15: U30.10@3595.33,6757.2 3672.49,6757.2 v2(3673.43,6756.26) ; U32.10@3595.33,7201.9 3668.08,7201.9 v2(3669.43,7203.26) ; U31.10@3598.66,411.2 3652.87,411.2 v2(3653.4,411.73) ; U33.10@3598.66,855.91 3652.87,855.91 v2(3653.4,856.44) ; U58.1@3662.32,4098.58 3721.28,4098.58 v2(3722,4097.87) ; U58.3@3662.32,4149.77 3721.28,4149.77 v2(3722,4149.05) ; U58.8@3662.32,4277.72 3721.28,4277.72 v2(3722,4277) ; C399.1@4780.97,4658.39 4780.97,4632.02 R284.1@4802.98,4610.02 ; C395.2@4849.35,5113.46 4860.48,5124.58 R275.1@4860.48,5150.94 4860.48,5174.95 4902.53,5217 v1(4909,5217) ; v2(4883,4846) 4883,4838.98 C405.1@4894.97,4827.01 ; C351.1@4894.89,4739.01 v2@4923.32,4739.01 ; v2(4986.21,7403.68) v2@4986.71,7403.18 ; v2@4995.97,4712.59 R298.2@4995.97,4741.02 ; R312.1@4995.97,4826.01 5024.4,4826.01 v2(5025.47,4827.08) ; v2@4997.71,7346.18 v2(4998.21,7345.68) ; C406.1@5031.66,4981.17 v2@5060.09,4981.17 ; C406.1@5031.66,4981.47 v2@5060.09,4981.47 ; C409.1@5031.66,5132.42 v2@5060.09,5132.42 ; R281.1@5060.97,4841.02 v2@5089.4,4841.02 ; R291.1@5060.97,4927.01 v2@5089.4,4927.01 ; v2(5069.3,995.75) v2@5069.8,995.25 ; v2@5079.2,9153.76 v2(5079.74,9153.22) U27.2@5140.96,9153.22 ; v2@5080.8,938.25 v2(5081.3,937.75) ; v2@5157.24,4981.62 R319.1@5185.67,4981.62 ; v2@5157.24,5132.57 R341.1@5185.67,5132.57 ; v2(5427,10359) U26.7@5474.72,10359 ; v2@5660.17,10359 U26.10@5707,10359 ; C445.1@6157.59,9767.75 v2(6157.59,9815.46) ; v2(6499.8,10281.21) 6529.21,10251.79 J72.5@6596.53,10251.79
  L1_Top Layer w20: J21.2@1576.41,1836.9 1576.51,1837 T2.4@1707.12,1837 ; v2(2040.51,3723.16) 2040.51,3676.93 C368.1@2041.18,3676.26 ; v2(2051.8,3235.26) D12.2@2051.8,3297.73 ; v2(2164.46,5784.18) 2168.66,5788.38 C345.2@2168.66,5857.32 ; v2(2219.8,3337.26) 2220.55,3338 C352.1@2220.55,3382.58 ; v2(2330.77,6468.32) 2331.07,6468.02 C322.1@2331.07,6435.39 ; C375.2@2382.96,3960.65 2382.96,4029.6 v2(2387.16,4033.8) ; D11.2@2499.81,6520.24 2501.57,6522 v2(2541,6522) ; C338.1@2510.44,6141.72 2555.01,6141.72 v2(2555.76,6140.97) ; C374.2@2644.45,3550.46 C377.1@2644.45,3606.86 ; v2(2663.13,9684.13) C108.2@2747.1,9684.13 2767.87,9704.89 v2(2826.9,9704.89) ; v2@2731.46,3338.36 C268.2@2815.43,3338.36 C268.2@2836.2,3359.12 ; C107.2@2840.1,9610.27 v2(2840.1,9652.72) ; v2(2889.63,4789.67) 2890.63,4790.67 R268.1@2928,4790.67 ; v2(2889.63,4941.91) 2890.63,4942.91 R269.1@2928,4942.91 ; C109.2@2890.1,9609.27 v2(2890.1,9651.72) ; v2(2890.13,4992.17) 2891.13,4993.17 R258.1@2928.5,4993.17 ; v2(2891.13,5142.41) 2892.14,5143.41 R259.1@2929.5,5143.41 ; C267.2@2908.43,3264.5 v2(2908.43,3306.95) ; R268.1@2928,4789.67 R268.1@2929,4789.67 ; R269.1@2928,4941.91 R269.1@2929,4941.91 ; R258.1@2928.5,4992.17 R258.1@2929.5,4992.17 ; R259.1@2929.5,5142.41 R259.1@2930.5,5142.41 ; C269.2@2958.43,3263.5 v2(2958.43,3305.95) ; U18.15@3111.01,3117.92 U18.15@3111.24,3118.16 ; v2(3180,4810) 3180.38,4809.62 C383.2@3219,4809.62 ; v2(3381,6532) 3381.47,6532.47 C450.1@3432.73,6532.47 ; v2(3393.55,185.27) 3394.51,186.22 C452.1@3435.81,186.22 ; v2(3432.08,6930.43) 3432.48,6930.83 C454.1@3432.48,6976.93 ; v2(3435.41,584.44) 3435.81,584.84 C456.1@3435.81,630.93 ; v2(3450,4877) 3469.21,4857.79 C381.2@3498,4857.79 ; v2(3456,4916.5) 3456.21,4916.29 C382.2@3497.88,4916.29 ; C489.1@3493.67,4033.15 v2(3544.87,4033.15) ; C449.1@3658.57,6537.73 v2(3706.07,6537.73) ; C453.1@3658.57,6982.43 v2(3706.07,6982.43) ; C451.1@3661.9,191.73 v2(3709.4,191.73) ; C455.1@3661.9,636.44 v2(3709.4,636.44) ; v2(3850.62,4768.19) R303.2@3885.85,4768.19 ; v2(3858.62,5064.44) R272.1@3893.85,5064.44 ; v2(3924.46,6816.56) 3925.07,6815.95 U55.8@3963.68,6815.95 ; v2(3927.79,470.56) 3928.4,469.95 U57.8@3967.01,469.95 ; R364.1@3994.28,5315.88 v2(4029.5,5315.88) ; R365.1@3994.28,5468.13 v2(4029.5,5468.13) ; R362.1@4034,5558.5 v2(4034,5593.73) ; v2(4049.16,4598.08) R287.1@4084.39,4598.08 ; R285.2@4054.79,5049.77 v2(4054.79,5084.99) ; C737.1@4133.33,7057.51 4141.33,7065.51 4141.33,7104.98 v2(4142.07,7105.73) ; C741.1@4136.66,711.52 C741.1@4136.66,718.52 4136.66,755.87 v2(4137.76,756.97) ; v2(4164.35,4347.07) R348.1@4164.35,4382.29 ; 4165,9230 4165,9171.5 C148.2@4167.5,9169 4197,9139.5 v2(4197,9120) ; v2(4166.01,5496.99) R366.1@4201.23,5496.99 ; R363.1@4186.25,5558.5 v2(4186.25,5593.73) ; v2(4316.06,4347.07) R347.1@4316.06,4382.29 ; v2(4353.48,5461.77) R367.1@4353.48,5496.99 ; v2(4385.01,4347.07) R339.1@4385.01,4382.29 ; v2(4423,5461.93) R328.1@4423,5497.16 ; v2(4535.88,4347.07) R338.1@4535.88,4382.29 ; v2(4573.01,4453.72) R337.1@4573.01,4488.95 ; R595.1@4574.57,9244.09 4575,9244.52 v2(4575,9287) ; v2(4575.25,5461.93) R329.1@4575.25,5497.16 ; R332.1@4614.38,5390.5 v2(4614.38,5425.73) ; v2(4725.25,4453.72) R336.1@4725.25,4488.95 ; D18.1@4730.66,10109 4734,10105.66 v2(4734,10052) ; v2(4745.01,9013) 4745.83,9013.82 C443.1@4745.83,9056.2 ; v2(4747.47,4658.94) 4748.01,4658.39 C399.1@4780.97,4658.39 ; R333.1@4766.62,5390.5 v2(4766.62,5425.73) ; R335.1@4771.86,4381.19 v2(4771.86,4416.42) ; R330.1@4825.79,5390.26 v2(4825.79,5425.48) ; v2(4840.21,7091.68) R51.1@4840.21,7130.56 ; v2(4889.21,7091.68) C74.1@4889.21,7130.56 4892.59,7127.18 U7.4@4974.72,7127.18 ; v2(4914,10261) 4926.47,10273.47 C468.1@4962.88,10273.47 4991.88,10244.47 5055.87,10244.47 5094.87,10283.47 5094.97,10283.37 U54.3@5138.02,10283.37 ; v2(4923.3,683.75) R132.1@4923.3,722.63 ; v2(4924.1,4345.97) R334.1@4924.1,4381.19 ; R50.1@4933.83,7409.18 4980.71,7409.18 v2(4986.21,7403.68) ; C444.1@4971.7,9072.76 4971.7,9118.23 v2(4972.1,9118.64) ; v2(4972.3,683.75) C234.1@4972.3,722.63 ; R331.1@4978.03,5390.26 v2(4978.03,5425.48) ; v2@4986.71,7403.18 C70.2@5029.71,7403.18 ; D15.2@4988.39,4192.45 5035.85,4192.45 v2(5035.94,4192.53) ; v2@4997.71,7346.18 C69.1@5039.59,7346.18 ; R131.1@5016.92,1001.25 5016.92,968.13 5031.3,953.75 v2(5034.3,953.75) ; v2(5058.81,667.05) U16.4@5058.81,718.25 ; v2@5069.8,995.25 C230.2@5112.8,995.25 ; v2@5080.8,938.25 C229.1@5122.67,938.25 ; R397.1@5213.35,4347 5249,4347 5290,4306 v2(5291,4306) ; D16.2@5251,5220.14 5310,5220.14 v2(5309.45,5220.68) ; D13.2@5251.02,5353.39 5310.01,5353.39 v2(5309.47,5353.94) ; D14.2@5251.55,5286.39 5310.55,5286.39 v2(5310.01,5286.94) ; v2(5259.21,7039.68) C83.1@5259.21,7078.56 ; C512.1@5296,4725 v2(5327,4756) ; v2(5308.21,7039.68) R62.1@5308.21,7078.56 ; C82.1@5309.83,7178.18 5345.71,7178.18 v2(5346.21,7178.68) ; R60.1@5309.83,7228.18 5345.71,7228.18 v2(5346.21,7228.68) ; R61.1@5337.83,7394.18 5337.83,7357.06 v2(5339.21,7355.68) ; U56.5@5341.88,9119.69 5341.88,9059.46 5356.37,9044.97 C738.1@5429.39,9044.97 v2(5429.39,8998.95) ; v2(5342.3,631.75) C243.1@5342.3,670.63 ; v2(5366.82,6169.6) 5366.82,6090.77 Y1.2@5374.02,6083.56 ; v2(5391.3,631.75) R143.1@5391.3,670.63 ; C242.1@5392.92,770.25 5428.8,770.25 v2(5429.3,770.75) ; R141.1@5392.92,820.25 5428.8,820.25 v2(5429.3,820.75) ; R142.1@5420.92,986.25 5420.92,949.13 v2(5422.3,947.75) ; R351.1@5437.62,5668.6 v2(5437.62,5723.11) ; v2(5439.63,6184.1) 5440.61,6185.09 C417.1@5527.03,6185.09 ; v2(5644.01,10619.58) 5644.22,10619.79 C441.1@5644.22,10572.95 ; v2(5693.87,9834.47) 5695.88,9832.46 C740.2@5695.88,9792.47 ; v2(5695.87,9560.47) C739.2@5695.88,9607.47 ; v2(5740.4,660.39) U37.4@5740.4,712.76 ; v2(5741.21,7013.68) U36.4@5741.21,7066.05 ; R469.1@5765.38,9512.97 v2@5765.38,9555 ; v2(5790.4,660.39) U37.3@5790.4,712.76 ; v2(5791.21,7013.68) U36.3@5791.21,7066.05 ; v2(5872,10632) 5873.34,10630.66 C442.1@5873.34,10590.12 ; v2(5872.78,5726.71) 5872.89,5726.83 R166.1@5872.89,5764.11 ; v2(5970.28,532.89) 5971.28,531.89 C476.2@5971.28,485.38 ; v2(5971.09,6886.18) 5972.09,6885.18 C475.2@5972.09,6838.67 ; v2(6085.85,9629.03) 6085.36,9629.51 U28.3@6131.45,9629.51 ; v2@6265.09,9864.18 C470.2@6265.09,9910.27 6265.09,9999.2 6283.15,10017.27 U35.2@6310.72,10017.27 ; v2(6266.73,8885.63) 6266.35,8886.01 R476.1@6312.48,8886.01 ; v2(6273.37,2539.43) R481.1@6319.5,2539.43 ; C473.2@6372.57,9916.19 6418.66,9916.19 v2(6418.18,9916.68) ; R596.1@6492.24,10556.08 v2(6492.27,10623.39) ; v2(6492.27,10623.39) R594.2@6492.27,10672.89 ; v2(6713.79,9139.08) R475.1@6713.79,9185.16 ; v2(6717.12,2808.25) R480.1@6717.12,2850.42 ; C532.1@6746.88,9856 6748.51,9854.37 v1(6785.5,9854.37)
  L1_Top Layer w30: v2(1702.07,5591.65) 1761.24,5591.65 C329.1@1762.3,5592.72 ; v2(1708.1,5670.52) C328.1@1767.27,5670.52 ; C329.1@1761.24,5593.78 C329.1@1762.3,5592.72 ; v2(1762.3,5533.54) C329.1@1762.3,5592.72 ; v2(1767.27,5729.69) C328.1@1767.27,5670.52 ; C328.1@1768.33,5669.45 C328.1@1767.27,5670.52 ; C328.1@1768.33,5671.58 C328.1@1767.27,5670.52 ; C358.1@1828.08,3810.46 C358.1@1829.14,3811.53 ; C358.1@1828.08,3812.59 C358.1@1829.14,3811.53 ; v2(1829.14,3752.35) C358.1@1829.14,3811.53 ; v2(1834.11,3948.5) C359.1@1834.11,3889.33 ; C359.1@1835.17,3888.26 C359.1@1834.11,3889.33 ; v2(1865.09,6047.12) C333.1@1904.23,6047.12 ; v2(1865.09,6102.02) C342.2@1904.23,6102.02 ; v2(1865.09,6156.42) C335.1@1904.23,6156.42 ; v2(1865.09,6211.12) C347.1@1904.23,6211.12 ; v2(1865.09,6267.52) C344.2@1904.23,6267.52 ; R220.2@1881.06,4051.33 1881.06,4051.81 v2(1904.34,4075.08) C366.2@1925.69,4096.43 ; v2(1888.32,3811.53) C358.1@1829.14,3811.53 ; v2(1894.35,3890.39) 1835.17,3890.39 C359.1@1834.11,3889.33 ; v2(1912.32,4275.16) R243.1@1951.46,4275.16 ; R189.2@1952.16,5542.82 v2(1952.16,5581.96) ; v2(2002.81,6414.92) C332.1@2034.85,6414.92 ; v2(2005.33,6350.82) C346.1@2037.37,6350.82 ; C369.2@2112.47,3911.86 v2(2142.67,3942.06) ; C354.1@2153.47,3873.65 v2(2179.88,3900.06) ; v2(2371.73,5917.92) C324.1@2398.15,5944.33 ; v2(2408.95,5875.92) C339.2@2439.14,5906.11 ; C376.1@2514.24,3467.16 v2(2546.28,3467.16) ; C362.1@2516.76,3403.06 v2(2548.8,3403.06) ; R230.2@2599.45,4275.16 2599.45,4323.12 v2(2599.83,4323.49) ; R202.1@2600.15,5542.82 v2(2639.29,5542.82) ; C336.2@2625.93,5721.55 v2(2647.28,5742.9) 2670.55,5766.17 R179.2@2670.55,5766.65 ; v2(2642.13,6153.85) C330.1@2701.3,6153.85 ; v2(2647.1,6078.05) C331.1@2706.27,6078.05 ; C377.1@2647.39,3606.86 v2(2686.53,3606.86) ; C365.1@2647.39,3661.56 v2(2686.53,3661.56) ; C372.2@2647.39,3715.96 v2(2686.53,3715.96) ; C363.1@2647.39,3770.86 v2(2686.53,3770.86) ; v2(2689.21,4246.17) C361.1@2748.38,4246.17 ; v2(2701.3,6213.02) C330.1@2701.3,6153.85 ; C330.1@2702.37,6152.79 C330.1@2701.3,6153.85 ; C330.1@2702.37,6154.91 C330.1@2701.3,6153.85 ; C331.1@2705.21,6079.11 C331.1@2706.27,6078.05 ; v2(2706.27,6018.88) C331.1@2706.27,6078.05 ; C331.1@2707.33,6079.11 C331.1@2706.27,6078.05 ; v2(2748.38,4305.35) C361.1@2748.38,4246.17 ; C361.1@2749.44,4245.11 C361.1@2748.38,4246.17 ; C361.1@2749.44,4247.24 C361.1@2748.38,4246.17 ; C360.1@2823.12,4250.08 C360.1@2824.18,4251.14 ; v2(2824.18,4310.32) C360.1@2824.18,4251.14 ; C360.1@2825.24,4250.08 C360.1@2824.18,4251.14 ; v2(2883.36,4251.14) C360.1@2824.18,4251.14 ; v2(6600.14,9929.74) 6600.14,10007.39 6600.47,10007.72 J72.Shell@6600.47,10013.6 ; J72.Shell@6600.47,10364 6600.47,10369.88 6600.8,10370.21 v2(6600.8,10447.86) ; v2(6816.67,9929.74) 6816.67,10007.39 6817,10007.72 J72.Shell@6817,10013.6 ; J72.Shell@6817,10364 6817,10380.88 6817.33,10381.21 v2(6817.33,10447.86)
  L12_Bottom Layer w8: R153.1@2159.5,2055.72 2162.89,2052.33 v1(2228.27,2052.33) ; R72.1@2166.17,8399.72 v1@2223.54,8399.72 ; v2@2190.94,8435.56 C146.2@2224.28,8435.56 ; v2(2193.72,2089) 2194.28,2089.56 C306.2@2227.61,2089.56 ; v2(3111.65,9403.6) v2@3113.65,9401.6 ; C384.2@3275.38,5025.29 C384.2@3278.12,5025.29
  L12_Bottom Layer w9.84: C154.2@2655.39,8076 v1(2682.39,8076)
  L12_Bottom Layer w11: v2@5108.98,9582.98 v2(5110,9584) ; v2(5693.87,9834.47) v2@5694.38,9833.96
  L12_Bottom Layer w15: C141.2@2147.83,8177.79 2147.83,8155.56 2170.21,8133.17 v1(2170.49,8133.17) ; C305.2@2150.61,1609.56 v1(2150.61,1644.56) ; C301.2@2151.16,1831.8 2151.16,1809.56 2175.17,1785.55 v1(2175.17,1782.82) ; C145.2@2157.28,7958.56 v1(2157.28,7993.56) ; v2(2190.39,8470) 2190.94,8470.56 C140.2@2224.28,8470.56 ; v2(2193.72,2124) 2194.28,2124.56 C300.2@2227.61,2124.56 ; C132.2@2401.76,8454.56 C133.2@2401.76,8516.56 ; v2(2405.09,2108.56) C293.2@2405.09,2170.56 ; C314.2@2665.76,1731.37 v1(2697.76,1731.37) ; R65.1@3104.92,8991.91 v2(3144.3,8991.91) R66.1@3190.68,8991.91 ; C440.2@4660.16,5065.71 C440.2@4665.67,5065.71 ; C436.1@4717.25,5025.95 C436.1@4717.25,5028.31 C435.2@4717.25,5067.68 4717.73,5068.16 C434.2@4717.73,5112.02 ; 5263.5,4722.5 5264.5,4721.5 5292.5,4721.5 5292.5,4693.5 5296,4690 ; 5278,4708 5279,4708 v2(5327,4756) v2(5355,4784) ; v1(5529.02,9316.98) U29.10@5575.96,9316.98 ; C508.2@5885.09,3797.1 5885.09,3709.89 5900.46,3694.51 U63.3@5926.76,3694.51 ; 5133.7,4631.3 C446.1@5133.7,4655.7 5214,4736 5232,4754 v2(5341,4645) 5230.5,4534.5 5133.7,4631.3
  L12_Bottom Layer w20: U20.5@1431.27,5825.01 v2(1431.26,5898.09) ; C350.1@1651.97,5757.28 1652.98,5756.27 v2(1704.17,5756.28) ; v2(2005.33,6350.82) 2005.33,6336.39 2033.21,6308.52 R183.2@2048.69,6308.52 ; v2(2038.16,5961.22) 2043.86,5955.52 R182.2@2081.69,5955.52 ; R223.2@2469.93,3862.45 2507.76,3862.45 v2(2513.46,3856.75) ; R224.2@2502.93,3509.45 2518.41,3509.45 2546.28,3481.58 v2(2546.28,3467.16) ; v2(2852.61,3900.45) 2853.61,3899.45 C380.1@2904.81,3899.45 ; v2(3118.8,3872) U22.5@3118.8,3992.97 ; R146.1@3173.9,2645.49 v2(3209.28,2645.49) R147.1@3244.65,2645.49 ; v2(3181,4872) 3199.67,4890.67 C385.1@3224.26,4890.67 ; v2(3204,5111) 3204,5096.67 C390.2@3230.88,5069.79 ; C386.2@3277.12,4965.29 3278.12,4966.29 C384.2@3278.12,5025.29 ; v3(3320.29,5026.96) C387.1@3330.5,5016.67 C387.1@3330.5,5016.67 ; C388.2@3363.88,4965.29 3363.88,4968.18 v3(3371.47,4975.78) ; C389.2@3414.78,5068.3 3414.78,5118.78 v2(3415,5119) ; v2(3505.3,8971.79) 3505.39,8971.88 R59.2@3549.46,8971.88 ; v2(3505.3,9071.79) 3505.39,9071.88 R58.2@3549.46,9071.88 ; v2(3505.3,9172.79) 3505.39,9172.88 R53.2@3549.46,9172.88 ; v2(3505.3,9271.79) 3505.39,9271.88 R52.2@3549.46,9271.88 ; v2(3586.94,2686.91) 3587.02,2686.99 R140.2@3631.09,2686.99 ; v2(3586.94,2786.91) 3587.02,2786.99 R139.2@3631.09,2786.99 ; v2(3586.94,2887.91) 3587.02,2887.99 R134.2@3631.09,2887.99 ; v2(3586.94,2986.91) 3587.02,2986.99 R133.2@3631.09,2986.99 ; v2(3850.62,4768.19) v2@3851.84,4766.98 ; v2(3858.62,5064.44) v2@3859.84,5063.22 ; v2@4028.29,5317.1 v2(4029.5,5315.88) ; v2@4028.29,5469.34 v2(4029.5,5468.13) ; v2@4032.79,5592.51 v2(4034,5593.73) ; v2(4041.25,5945.25) 4055.25,5931.25 C147.2@4095.75,5931.25 ; v2(4049.16,4598.08) v2@4050.38,4596.86 ; v2@4053.57,5083.78 v2(4054.79,5084.99) ; C147.2@4095.5,5931 4116.33,5910.18 4116.33,5821.67 4125,5813 U73.2@4158.74,5813 ; v2(4164.35,4347.07) v2@4165.57,4348.28 ; v2@4185.03,5592.51 v2(4186.25,5593.73) ; R600.1@4200.5,9739 4200.5,9688.5 v2(4202,9687) ; v1(4233.89,5041) 4236.79,5041 C424.1@4270.85,5006.94 ; v2(4236.47,4796.94) 4285.89,4796.94 C432.2@4298.97,4810.02 ; v2(4282,9088) 4283,9087 R593.2@4283,9038.5 ; v2(4316.06,4347.07) v2@4317.28,4348.28 ; v2(4317.89,5196) 4344.65,5222.76 C439.2@4365.97,5222.76 ; C430.2@4350.97,4632.27 4350.97,4571.44 v2(4351.47,4570.94) ; v2(4353.48,5461.77) v2@4354.69,5462.99 ; v1(4382.79,4734.77) 4382.79,4736.25 4418.03,4771.5 C431.2@4418.03,4788.15 ; v2(4385.01,4347.07) v2@4386.23,4348.28 ; v2(4409.47,4586.94) 4409.97,4587.44 C427.1@4409.97,4629.46 4410.41,4629.9 C426.1@4458.97,4629.9 4459.48,4629.39 C425.1@4507.97,4629.39 ; v2(4423,5461.93) v2@4424.22,5463.15 ; C423.1@4471.51,5057 4471.51,5009.39 R368.1@4472.28,5008.62 ; v2(4535.88,4347.07) v2@4537.09,4348.28 ; v2(4573.01,4453.72) v2@4574.23,4454.94 ; v2(4575.25,5461.93) v2@4576.46,5463.15 ; v2@4613.16,5424.51 v2(4614.38,5425.73) ; v3(4671.58,4807.84) 4688.4,4791.02 C422.2@4712.35,4791.02 ; v2(4725.25,4453.72) v2@4726.47,4454.94 ; v2@4765.41,5424.51 v2(4766.62,5425.73) ; v2@4770.64,4415.2 v2(4771.86,4416.42) ; v2@4824.57,5424.27 v2(4825.79,5425.48) ; C433.2@4848.97,5157.64 4848.97,5191.97 4874,5217 v1(4909,5217) ; v2(4852.87,9532.47) 4853.96,9531.38 C474.2@4944.87,9531.38 v2(5024.78,9531.38) ; v2(4924.1,4345.97) v2@4925.32,4347.18 ; v2@4976.82,5424.27 v2(4978.03,5425.48) ; C736.2@5047.87,9582.98 v2@5108.98,9582.98 ; R311.1@5077.19,4463.19 5078.19,4463.19 R297.1@5111.81,4496.81 ; C463.1@5083.38,9783.58 5144.76,9783.58 5156.87,9771.47 v2(5156.87,9764) C469.1@5156.87,9729.47 ; C461.1@5083.38,10023.73 5145.13,10023.73 v2(5145.87,10024.47) ; v2(5095.47,4479.53) 5095.47,4479 T3.2@5141,4433.47 5182,4392.47 5182,4321.76 T3.4@5194.03,4309.73 ; C462.1@5110.39,10102.97 v2@5110.39,10142.01 ; v2(5220.87,9736.47) 5221.18,9736.16 C465.1@5221.18,9665.47 ; v2(5291.87,10032.47) 5319.6,10060.2 C464.1@5319.6,10102.47 ; v2(5348.14,5913.35) 5348.48,5913 U25.3@5405.97,5913 ; v2(5386.87,9726.47) 5387.39,9725.95 C459.1@5387.39,9663.97 ; v2(5416.87,9771.47) 5417.37,9770.97 C458.1@5462.39,9770.97 ; v2(5416.87,9833.47) 5417.37,9832.97 R542.2@5462.39,9832.97 ; v2(5416.87,9896.47) 5417.37,9895.97 C467.1@5462.39,9895.97 ; v2(5416.87,9960.47) 5417.37,9959.97 C460.1@5462.39,9959.97 ; v2(5478,9189) 5513.32,9153.68 C447.1@5513.32,9105 ; v2(5654.6,6163.65) 5654.78,6163.65 C412.1@5680.97,6137.46 ; C457.2@5694.38,9794.97 v2@5694.38,9833.96 ; C466.2@5694.38,9895.97 5736.37,9895.97 v2(5748.87,9908.47) ; v2(5709.82,6170.52) 5733.97,6146.36 C411.1@5733.97,6137.46 ; C448.1@5724.81,9139.2 5774.8,9139.2 v2(5776,9138) ; C511.2@5733.91,3479.26 5733.91,3514.91 v2(5733.96,3514.97) ; C508.2@5885.09,3797.1 5885.09,3832.76 v2(5885.15,3832.82) ; v2(5911,3383) 5931.19,3403.19 U64.3@5931.19,3428.23 ; v2(6059,9979) 6118.09,10038.09 C471.2@6139,10038.09 ; C472.1@6242,9987.5 6242,10022 6253,10033 v2(6253,10049)
  L12_Bottom Layer w30: v2(2164.46,5784.18) 2170.12,5784.18 C323.1@2191.16,5805.22 ; C370.1@2229.61,3762.16 2274.96,3762.16 2281.89,3762.16 2289.52,3754.53 v3@2307.62,3736.43 ; v3@2243.99,6081.55 2262.09,6063.45 2269.72,6055.82 2276.66,6055.82 C340.1@2322,6055.82 ; v3@2243.99,6198.08 2243.99,6206.95 C327.1@2263.57,6226.53 ; C356.2@2249.62,3679.16 2273.09,3655.69 2278.49,3650.28 v3@2278.49,3649.02 ; v3@2273.13,6168.95 2273.13,6167.69 C326.2@2302,6138.82 ; C357.1@2288.05,3591.45 2307.62,3611.02 ; C353.1@2360.46,4012.75 2381.5,4033.8 v2(2387.16,4033.8)
  other v1: 6166.44,524.01 6316.44,524.01 6416.44,524.01 6516.44,524.01 6616.44,524.01 6716.44,524.01 6816.44,524.01 6216.44,574.01 6266.44,574.01 6366.44,574.01 6466.44,574.01 6566.44,574.01 6666.44,574.01 6766.44,574.01 6216.44,624.01 6316.44,624.01 6416.44,624.01 6516.44,624.01 6616.44,624.01 6666.44,624.01 6766.44,624.01 6166.44,674.01 6566.44,674.01 6716.44,674.01 6816.44,674.01 6166.44,724.01 6266.44,724.01 6366.44,724.01 6466.44,724.01 6616.44,724.01 6716.44,724.01 6816.44,724.01 6216.44,774.01 6316.44,774.01 6416.44,774.01 6516.44,774.01 6666.44,774.01 6766.44,774.01 6216.44,824.01 6666.44,824.01 6766.44,824.01 6166.44,874.01 6266.44,874.01 6366.44,874.01 6466.44,874.01 6616.44,874.01 6716.44,874.01 6816.44,874.01 6166.44,924.01 6316.44,924.01 6416.44,924.01 6516.44,924.01 6616.44,924.01 6716.44,924.01 6816.44,924.01 6216.44,974.01 6666.44,974.01 6766.44,974.01 6216.44,1024.01 6266.44,1024.01 6366.44,1024.01 6466.44,1024.01 6666.44,1024.01 6766.44,1024.01 6166.44,1074.01 6316.44,1074.01 6416.44,1074.01 6516.44,1074.01 6616.44,1074.01 6716.44,1074.01 6816.44,1074.01 6566.44,1124.01 6616.44,1124.01 6716.44,1124.01 6816.44,1124.01 6366.44,1174.01 6466.44,1174.01 6666.44,1174.01 6766.44,1174.01 6416.44,1224.01 6516.44,1224.01 6666.44,1224.01 6766.44,1224.01 6566.44,1274.01 6616.44,1274.01 6716.44,1274.01 6816.44,1274.01 6616.44,1324.01 6716.44,1324.01 6816.44,1324.01 6766.44,1374.01 6766.44,1424.01 6816.44,1474.01 1937,1502 1970,1502 2197,1514 2151.54,1515 6716.44,1524.01 6816.44,1524.01 1937,1534 1970,1534 1937,1566 1970,1566 6766.44,1574.01 6666.44,1624.01 6766.44,1624.01 2392,1630 2392,1655 6716.44,1674.01 6816.44,1674.01 2150.61,1680.56 2060.33,1689.6 2574.72,1705.87 1633.33,1719 1748.33,1719 6716.44,1724.01 6816.44,1724.01 2322.76,1737.37 2354.25,1737.37 2385.75,1737.37 2417.24,1737.37 2574.72,1737.37 1633.33,1759 1748.33,1759 6666.44,1774.01 6766.44,1774.01 1748.33,1799 2228.27,1800.36 2385.75,1800.36 2480.24,1800.36 2511.73,1800.36 1925.54,1809.93 2061.33,1815.6 6416.44,1824.01 6666.44,1824.01 6766.44,1824.01 2228.27,1831.85 2385.75,1831.85 1748.33,1839 2259.76,1863.35 2291.26,1863.35 2385.75,1863.35 2480.24,1863.35 2511.73,1863.35 6716.44,1874.01 6816.44,1874.01 2259.76,1894.85 2291.26,1894.85 2385.75,1894.85 2480.24,1894.85 2511.73,1894.85 2150.16,1921.8 6716.44,1924.01 6816.44,1924.01 2228.27,1926.34 2385.75,1926.34 1925.54,1944.17 2048.31,1945.1 2228.27,1957.84 2385.75,1957.84 2480.24,1957.84 2511.73,1957.84 2150.16,1958.8 6416.44,1974.01 6666.44,1974.01 6766.44,1974.01 2385.75,1989.33 2259.76,2020.83 2291.26,2020.83 2322.76,2020.83 2354.25,2020.83 2385.75,2020.83 2417.24,2020.83 2574.72,2020.83 6666.44,2024.01 6766.44,2024.01 1977,2049 2259.76,2052.33 2291.26,2052.33 2385.75,2052.33 2417.24,2052.33 2574.72,2052.33 6716.44,2074.01 6816.44,2074.01 1977,2107.51 6416.44,2124.01 6616.44,2124.01 6716.44,2124.01 6816.44,2124.01 6666.44,2174.01 6766.44,2174.01 6566.44,2224.01 6666.44,2224.01 6416.44,2274.01 6616.44,2274.01 6716.44,2274.01 6816.44,2274.01 6716.44,2324.01 6816.44,2324.01 6566.44,2374.01 6666.44,2374.01 6766.44,2374.01 6766.44,2424.01 6166.44,2474.01 6716.44,2474.01 5733,2724 5839,2724 5854,2847 5960,2847 5608,3023 5714,3023 3106.5,3102.57 3067.13,3149.82 3106.5,3149.82 3145.87,3149.82 3106.5,3197.06 2214.89,3310.43 2340.8,3310.35 1834.41,3451.2 1834.5,3577.11 2207.61,4308.11 2340.52,4308.11 2213.09,4389.09 2336,4389 3300.75,4438.74 3423.66,4438.65 2788.54,4803.88 2788.63,4926.79 2796.98,5005.17 2797.07,5128.08 2218.09,5430.09 2341,5430 2211.09,5509.86 2344,5509.86 4210.9,5694.04 4343.81,5693.96 2717.11,6240.86 2717.2,6366.77 2210.82,6507.63 2336.73,6507.54 6163.11,6870.01 6313.11,6870.01 6413.11,6870.01 6513.11,6870.01 6613.11,6870.01 6713.11,6870.01 6813.11,6870.01 6213.11,6920.01 6263.11,6920.01 6363.11,6920.01 6463.11,6920.01 6563.11,6920.01 6663.11,6920.01 6763.11,6920.01 6213.11,6970.01 6313.11,6970.01 6413.11,6970.01 6513.11,6970.01 6613.11,6970.01 6663.11,6970.01 6763.11,6970.01 4681.89,6994.08 4399.31,7002.51 6163.11,7020.01 6563.11,7020.01 6713.11,7020.01 6813.11,7020.01 4753.31,7065.5 6163.11,7070.01 6263.11,7070.01 6363.11,7070.01 6463.11,7070.01 6613.11,7070.01 6713.11,7070.01 6813.11,7070.01 4470.73,7073.92 6213.11,7120.01 6313.11,7120.01 6413.11,7120.01 6513.11,7120.01 6663.11,7120.01 6763.11,7120.01 4411.89,7149.08 6213.11,7170.01 6663.11,7170.01 6763.11,7170.01 6163.11,7220.01 6263.11,7220.01 6363.11,7220.01 6463.11,7220.01 6613.11,7220.01 6713.11,7220.01 6813.11,7220.01 4483.31,7220.5 6163.11,7270.01 6313.11,7270.01 6413.11,7270.01 6513.11,7270.01 6613.11,7270.01 6713.11,7270.01 6813.11,7270.01 6213.11,7320.01 6663.11,7320.01 6763.11,7320.01 6213.11,7370.01 6263.11,7370.01 6363.11,7370.01 6463.11,7370.01 6663.11,7370.01 6763.11,7370.01 6163.11,7420.01 6313.11,7420.01 6413.11,7420.01 6513.11,7420.01 6613.11,7420.01 6713.11,7420.01 6813.11,7420.01 6563.11,7470.01 6613.11,7470.01 6713.11,7470.01 6813.11,7470.01 6363.11,7520.01 6463.11,7520.01 6663.11,7520.01 6763.11,7520.01 6413.11,7570.01 6513.11,7570.01 6663.11,7570.01 6763.11,7570.01 6563.11,7620.01 6613.11,7620.01 6713.11,7620.01 6813.11,7620.01 6613.11,7670.01 6713.11,7670.01 6813.11,7670.01 2078,7693.16 2110,7709.04 6763.11,7720.01 2045.27,7734 2110,7741.04 6763.11,7770.01 6813.11,7820.01 6713.11,7870.01 6813.11,7870.01 2194.48,7874.13 2149.02,7875.13 6763.11,7920.01 6663.11,7970.01 6763.11,7970.01 2388.08,7973.94 2388.08,7999.94 6713.11,8020.01 6813.11,8020.01 2157.28,8029.56 2057,8037 2571.39,8051.87 1630,8065 1745,8065 6713.11,8070.01 6813.11,8070.01 2319.43,8083.36 2350.92,8083.36 2382.42,8083.36 2413.91,8083.36 2571.39,8083.36 1630,8105 1745,8105 6663.11,8120.01 6763.11,8120.01 1745,8145 2224.94,8146.35 2382.42,8146.35 2476.91,8146.35 2508.4,8146.35 1929,8158 2058,8163 6413.11,8170.01 6663.11,8170.01 6763.11,8170.01 2224.94,8177.85 2382.42,8177.85 1745,8185 2256.43,8209.35 2287.93,8209.35 2382.42,8209.35 2476.91,8209.35 2508.4,8209.35 6713.11,8220.01 6813.11,8220.01 2256.43,8240.84 2287.93,8240.84 2382.42,8240.84 2476.91,8240.84 2508.4,8240.84 2146.83,8267.79 6713.11,8270.01 6813.11,8270.01 2224.94,8272.34 2382.42,8272.34 1929,8292.24 2044.98,8292.51 2224.94,8303.83 2382.42,8303.83 2476.91,8303.83 2508.4,8303.83 2146.83,8304.79 6413.11,8320.01 6663.11,8320.01 6763.11,8320.01 2382.42,8335.33 2256.43,8366.83 2287.93,8366.83 2319.43,8366.83 2350.92,8366.83 2382.42,8366.83 2413.91,8366.83 2571.39,8366.83 6663.11,8370.01 6763.11,8370.01 1985.34,8396.23 2224.94,8398.32 2256.43,8398.32 2287.93,8398.32 2382.42,8398.32 2413.91,8398.32 2571.39,8398.32 6713.11,8420.01 6813.11,8420.01 1985.34,8454.74 6413.11,8470.01 6613.11,8470.01 6713.11,8470.01 6813.11,8470.01 6663.11,8520.01 6763.11,8520.01 6563.11,8570.01 6663.11,8570.01 6413.11,8620.01 6613.11,8620.01 6713.11,8620.01 6813.11,8620.01 6713.11,8670.01 6813.11,8670.01 6563.11,8720.01 6663.11,8720.01 6763.11,8720.01 6763.11,8770.01 6163.11,8820.01 6713.11,8820.01 3038.17,9448.34 2998.8,9495.58 3077.54,9495.58 3038.17,9542.83 6812.5,9854.3 6785.38,9881 6812.38,9880.93 6732.38,9896 6759.38,9895.93 6732.45,9923 6759.45,9922.93
  other v2: 3900.06,622.32 2703.03,1619.24 2703.03,1682.24 2217,2286 2178.02,2286.47 2217,2327 2178.02,2327.47 2942.7,2625.59 2982.47,2625.35 3022.7,2625.35 3022.7,2661.12 2942.7,2661.58 3024.55,2892 3064.53,2892 2968.27,2930.24 3025,2931.77 3064.77,2931.77 3025,2972 3064.77,2972 2371.34,3242.76 2346.67,3273.78 2731.23,3338.12 5333.5,3431 5374.2,3431 5414.5,3431 1999,3438.71 5333.5,3471.3 5414.5,3471.71 2014.45,3515.45 4989,3535 5049,3535 5109,3535 5169,3535 4989,3583 5049,3583 1317.92,4048.38 1365.92,4048.38 1317.92,4096.38 1365.92,4096.38 1468,4371 3022,4376 2803,4377 1504,4392 2832,4405 3013,4410 1468,4419 4997.04,4711.52 4924.39,4740.08 1698.06,4742.9 1740.06,4742.9 1782.06,4742.9 2873.55,4746.7 2912,4747 1698.06,4790.9 1740.06,4790.9 1782.06,4790.9 5090.47,4842.09 5090.47,4928.08 5156.17,4980.84 5061.16,4982.25 1292.94,5018.3 1352.94,5018.3 1412.94,5018.3 1472.94,5018.3 1532.94,5018.3 1292.94,5066.3 1352.94,5066.3 1412.94,5066.3 5156.17,5131.79 5061.16,5133.49 5965,5230 5946,5254 5715,5304 5715,5347 5715,5390 5715,5433 5659.66,5594.34 5659.66,5644.34 5659.66,5696.34 3075,6053 3123,6053 3171,6053 3075,6101 3123,6101 3171,6101 5709.82,6249.1 5366.82,6250.03 2540.69,6273 2552,6305.44 2208.33,6555.22 2183.66,6586.24 3949.33,7034.47 2702.09,7965.35 2702.09,8027.35 2190.39,8435 2404,8456 1924,8547 2009.82,8568 1924.48,8585 2184.08,8632.9 2222,8633 2184.08,8673.9 2222,8674 2874.94,8975.01 2914.71,8974.76 2954.94,8974.76 2874.94,9014.99 2954.94,9014.53 2956.78,9245.41 2996.76,9245.41 2900.51,9283.65 2957.24,9285.19 2997.01,9285.19 2957.24,9325.41 2997.01,9325.41 5765,9555 6684.11,9640.8 6684.11,9716.8 6265.57,9864.66 2158,10144 2197,10144 2236,10144 2275,10144 2314,10144 2742,10144 2781,10144 2820,10144 3242,10144 3281,10144 3320,10144 5110,10148 5654,10359 4890.19,10698.26 4770.19,10736.26 4830.19,10736.26 4890.19,10736.26
  other v3: 5713.79,1128.14 5713.79,1222.14 5647.07,1250.4 5647.07,1344.4 5498.64,1347.16 5432.18,1413.63 5783.29,1414.58 5783.29,1508.58 5695.98,1539.19 5564.13,1631.22 5695.98,1633.19 5497.66,1697.69 5879.83,1772.62 5296.46,1800.29 5977.92,1864.5 5362.92,1866.76 5879.83,1866.62 5977.92,1958.5 5891.6,1998.45 5781.92,2060.56 5891.6,2092.45 5715.45,2127.03 5456.51,2138.39 5456.51,2232.39 5291.42,2342.18 5291.42,2436.18 5378.21,2464.82 5378.2,2555.22 2274.96,3616.36 2316.16,3616.36 2357.36,3616.36 2398.56,3616.36 2274.96,3657.56 2316.16,3657.56 2398.56,3657.56 2274.96,3698.76 2316.16,3698.76 2398.56,3698.76 2274.96,3739.96 2316.16,3739.96 2357.36,3739.96 2398.56,3739.96 4510.95,4807.84 4564.49,4807.84 4618.03,4807.84 4459.37,4859.41 4510.95,4859.41 4564.49,4859.41 4618.03,4859.41 4671.58,4859.41 4723.15,4859.41 4459.37,4912.95 4510.95,4912.95 4564.49,4912.95 4618.03,4912.95 4671.58,4912.95 4723.15,4912.95 3320.29,4924.59 4459.37,4966.5 4510.95,4966.5 4564.49,4966.5 4618.03,4966.5 4671.58,4966.5 4723.15,4966.5 3269.11,4975.78 4459.37,5020.04 4510.95,5020.04 4564.49,5020.04 4618.03,5020.04 4671.58,5020.04 4723.15,5020.04 4510.95,5071.61 4564.49,5071.61 4618.03,5071.61 4671.58,5071.61 2194.26,6078.01 2235.46,6078.01 2276.66,6078.01 2153.06,6119.22 2276.66,6119.22 2153.06,6160.42 2194.26,6160.42 2235.46,6160.42 2276.66,6160.42 2194.26,6201.62 2235.46,6201.62 2276.66,6201.62 5710.46,7474.14 5710.46,7568.14 5643.74,7596.4 5643.74,7690.4 5495.31,7693.16 5428.85,7759.63 5780.96,7761.58 5780.96,7855.58 5692.65,7885.19 5560.8,7977.22 5692.65,7979.19 5494.33,8043.69 5877.5,8117.62 5293.13,8146.29 5974.59,8210.5 5877.5,8211.62 5359.59,8212.76 5974.59,8304.5 5888.27,8344.45 5778.59,8406.56 5888.27,8438.45 5712.12,8473.03 5453.18,8484.39 5453.18,8578.39 5287.68,8691.9 5288.09,8782.18 5374.88,8809.82 5374.88,8903.82
DM: R472.2 U34.7 | length 1049.2
  L1_Top Layer w8.2: U34.7@5520.39,9854.44 5562.92,9854.44 5565.66,9857.18 5881.27,9857.18 6189.9,10165.82 6378.56,10165.82 6403.46,10140.92 R472.2@6430.25,10140.92
DP: R539.2 U34.8 | length 1049.2
  L1_Top Layer w8.2: U34.8@5520.39,9874.13 5562.92,9874.13 5565.66,9871.38 5875.38,9871.38 6184.02,10180.02 6378.56,10180.02 6403.46,10204.92 R539.2@6430.25,10204.92
EADC_SCK: J32.8 R375.2 | length 295.7
  L1_Top Layer w11: R375.2@6046.78,10528.12 6191.88,10528.12 J32.8@6298.35,10634.59
EADC_SCS\: J32.2 J33.2 | length 879.2
  L12_Bottom Layer w11: J32.2@6298.35,10334.59 6298.35,10096.65 6362,10033 6362,9650 J33.2@6481,9531
EADC_SDI: J32.4 R377.2 | length 264.6
  L1_Top Layer w11: R377.2@6046.78,10466.05 6266.89,10466.05 J32.4@6298.35,10434.59
EADC_SDO: J32.3 R379.2 | length 379
  L1_Top Layer w11: R379.2@6046.99,10403 6064.58,10385.41 6349.17,10385.41 J32.3@6398.35,10434.59
EE_ADDR0_RX_1: J46.C34 U36.1 | length 854.7
  L1_Top Layer w11: U36.1@5891.21,7066.05 5891.21,7016.68 5915.21,6992.68 6344.71,6992.68 6522.04,7170.01 v1(6613.11,7170.01)
EE_ADDR0_RX_2: J51.C34 U37.1 | length 845.4
  L1_Top Layer w11: U37.1@5890.4,712.76 5890.4,673.81 5912.4,651.81 6338.75,651.81 6510.95,824.01 v1(6616.44,824.01)
EE_ADDR1_RX_1: J46.D35 U36.2 | length 907.8
  L1_Top Layer w11: U36.2@5841.21,7066.05 5841.21,6998.68 5889.38,6950.51 6442.04,6950.51 6563.11,7071.58 v1(6563.11,7120.01)
EE_ADDR1_RX_2: J51.D35 U37.2 | length 906.3
  L1_Top Layer w11: U37.2@5840.4,712.76 5840.4,645.39 5882.98,602.81 6436.75,602.81 6566.44,732.5 v1(6566.44,774.01)
EECLK: R546.1 U34.62 U56.2 | length 370.9
  L1_Top Layer w8: U34.62@5410.15,9665.47 5410.15,9625.35 5453.87,9581.63 5453.87,9570.44
  L1_Top Layer w11: U56.2@5441.88,9334.25 5441.88,9393.12 5421.88,9413.12 R546.1@5421.88,9481.47 5453.87,9513.46 5453.87,9570.44
EECS: R544.1 U34.63 U56.1 | length 372.7
  L1_Top Layer w8: U34.63@5429.84,9665.47 5429.84,9626.55 5479.38,9577.01 5479.38,9564.44
  L1_Top Layer w11: 5479.38,9564.44 5479.38,9511.98 R544.1@5510.88,9480.47 5510.88,9416 5491.88,9397 U56.1@5491.88,9334.25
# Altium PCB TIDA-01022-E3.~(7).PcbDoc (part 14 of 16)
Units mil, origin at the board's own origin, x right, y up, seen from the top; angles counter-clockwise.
Board outline 6929.13 x 11614.17 mil, 12 copper layers (L1_Top Layer, L2_GND, L3_GND, L4_Signal Layer 1, L5_GND, L6_PWR, L7_GND/PWR, L8_PWR, L9_GND/PWR, L10_Signal Layer 2, L11_GND, L12_Bottom Layer), stack 64.6 mil thick; 1733 components, 993 nets, 5987 pads, 3555 vias.

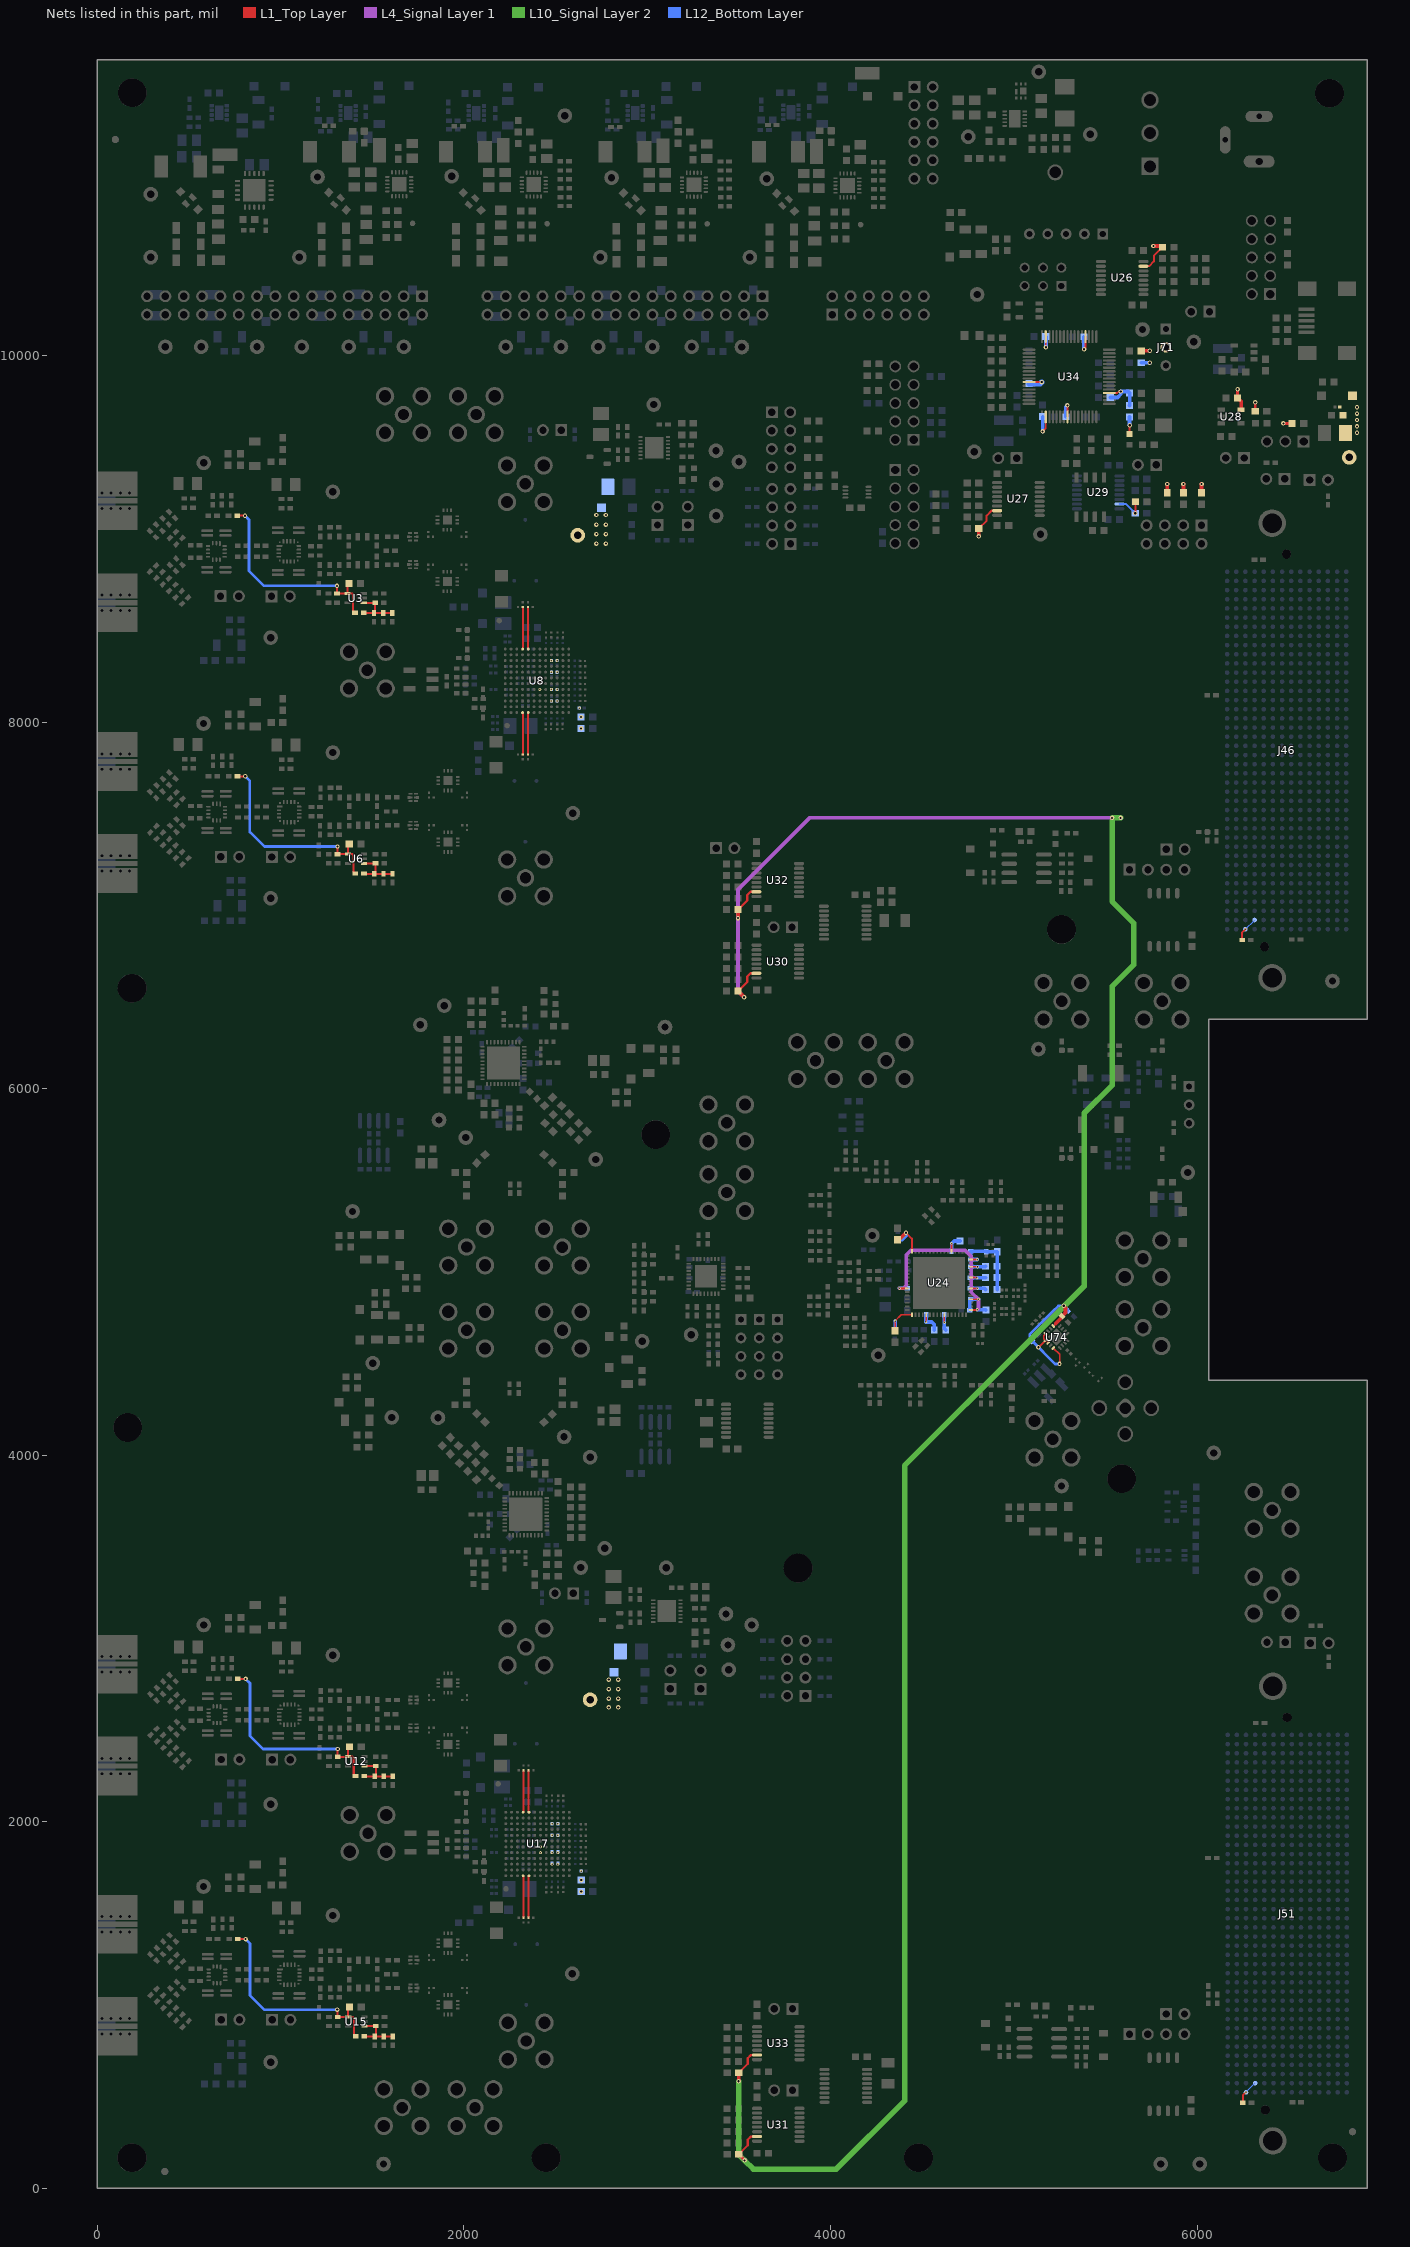
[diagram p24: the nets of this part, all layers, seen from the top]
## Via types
v1: diameter 16, hole 8, L1_Top Layer to L12_Bottom Layer, tented both sides, 1686 vias
v2: diameter 24, hole 12, L1_Top Layer to L12_Bottom Layer, tented both sides, 1590 vias
v3: diameter 20, hole 10, L1_Top Layer to L12_Bottom Layer, 279 vias

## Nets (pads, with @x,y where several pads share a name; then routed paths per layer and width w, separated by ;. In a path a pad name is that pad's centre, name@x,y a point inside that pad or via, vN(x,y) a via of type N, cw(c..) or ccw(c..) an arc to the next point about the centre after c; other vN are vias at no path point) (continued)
VCC1_VCO: C420.1 C421.1 C422.1 L22.2 U24.10 U24.33 U24.36 | length 1207.9
  L1_Top Layer w9.84: U24.33@4764.49,4792.09 v1@4795,4792.09 ; U24.36@4764.49,4851.14 v1(4806.68,4851.14)
  L1_Top Layer w10: v1(4375.73,4910.2) U24.10@4418.03,4910.2
  L4_Signal Layer 1 w20: v1(4375.73,4910.2) 4396.2,4910.2 4413,4927 4413,5092 4439,5118 4734,5118 4768,5084 4768,4889.82 v1(4806.68,4851.14) 4806.68,4800.68 v1(4800,4794)
  L12_Bottom Layer w20: v1(4375.73,4910.2) C420.1@4418.03,4910.2 ; C422.1@4759.59,4791.02 4759.59,4846.24 C421.1@4764.49,4851.14 v1(4806.68,4851.14) ; v1(4800,4794) 4843.56,4794 4846.01,4791.55 L22.2@4846.97,4792.51
VCC2_CG1: C430.1 L23.2 U24.17 | length 212
  L1_Top Layer w8.6: L23.2@4350.97,4679.51 4352,4680.54 v1(4352,4732) 4352,4732.47 4386.03,4766.5 U24.17@4443.62,4766.5
  L12_Bottom Layer w20: C430.1@4350.97,4679.51 4352,4680.54 v1(4352,4732)
VCC3_SYSREF: C429.1 L24.2 U24.21 | length 161.4
  L1_Top Layer w8: v1(4520.47,4727.15) 4522.36,4729.04 U24.21@4522.36,4766.5
  L12_Bottom Layer w20: C429.1@4522.36,4766.5 4520.47,4764.6 v1(4520.47,4727.15) 4552.26,4727.15 4565.97,4713.44 L24.2@4565.97,4683.51
VCC4_CG2: C428.1 L25.2 U24.26 | length 127.2
  L1_Top Layer w8: v1(4620.79,4725.26) U24.26@4620.79,4766.5
  L12_Bottom Layer w20: C428.1@4620.79,4766.5 v1(4620.79,4725.26) 4620.79,4690.69 L25.2@4627.97,4683.51
VCC7_OSCOUT: C438.2 L26.2 U24.39 | length 120.5
  L1_Top Layer w9.84: U24.39@4764.49,4910.2 v1(4800.73,4910.2)
  L12_Bottom Layer w20: C438.2@4764.09,4910.94 4764.83,4910.2 v1(4800.73,4910.2) 4839.29,4910.2 L26.2@4845.47,4904.02
VCC8_OSCIN: C437.2 L27.2 U24.42 | length 117.4
  L1_Top Layer w8: v1@4797.16,4969.25 v1(4798.47,4967.94)
  L1_Top Layer w9.84: U24.42@4764.49,4969.25 v1@4797.16,4969.25
  L12_Bottom Layer w20: C437.2@4763.09,4967.94 v1(4798.47,4967.94) 4844.4,4967.94 L27.2@4845.47,4969.02
VCC9_CP2: C436.2 L28.2 U24.45 | length 119.5
  L1_Top Layer w8: v1@4801.1,5028.31 v1(4801.47,5027.94)
  L1_Top Layer w9.84: U24.45@4764.49,5028.31 v1@4801.1,5028.31
  L12_Bottom Layer w20: C436.2@4764.49,5028.31 4764.86,5027.94 v1(4801.47,5027.94) 4842.4,5027.94 L28.2@4845.47,5031.02
VCC10_PLL2: C433.1 C434.1 C435.1 L26.1 L27.1 L28.1 L29.2 U24.47 | length 467.4
  L1_Top Layer w9.84: U24.47@4764.49,5067.68 v1(4800.21,5067.68)
  L12_Bottom Layer w20: v1(4800.21,5067.68) C435.1@4764.49,5067.68 4764.49,5111.54 C434.1@4764.97,5112.02 4847.35,5112.02 C433.1@4848.97,5110.39 4908.85,5110.39 L29.2@4908.97,5110.52 4908.97,5031.52 L28.1@4908.47,5031.02 L27.1@4908.47,4969.02 L26.1@4908.47,4904.02
VCC11_CG3: C440.1 L30.2 U24.53 | length 134.4
  L1_Top Layer w9.84: U24.53@4660.16,5112.95 v1(4660.16,5154.25)
  L12_Bottom Layer w20: C440.1@4660.16,5112.95 v1(4660.16,5154.25) 4674.35,5168.44 L30.2@4706.05,5168.44
VCC12_CG0: C439.1 L31.2 U24.64 | length 250.4
  L1_Top Layer w9.84: v2(4411.62,5214) 4443.62,5181.99 U24.64@4443.62,5112.95
  L1_Top Layer w20: L31.2@4365.97,5175.52 4369.55,5171.94 v2(4411.62,5214)
  L12_Bottom Layer w20: C439.1@4365.97,5175.52 4390.14,5175.52 4411.62,5197 v2(4411.62,5214)
VCMO1: C28.1 R24.1 R556.1 R557.2 R558.2 U3.1 | length 277.9
  L1_Top Layer w11: R24.1@1452.71,8596.26 1454.56,8594.41 R556.1@1508.91,8594.41 ; U3.1@1453.38,8650.67 1514.88,8650.67 C28.1@1515.47,8651.26 1515.47,8600.97 R556.1@1508.91,8594.41 ; R558.2@1607.91,8594.41 R557.2@1558.91,8594.41 R556.1@1508.91,8594.41
VCMO2: C62.1 R48.1 R565.1 R566.2 R567.2 U6.1 | length 277.9
  L1_Top Layer w11: R48.1@1454.51,7174.13 1456.36,7172.28 R565.1@1510.71,7172.28 ; U6.1@1455.18,7228.54 1516.68,7228.54 C62.1@1517.27,7229.13 1517.27,7178.84 R565.1@1510.71,7172.28 ; R567.2@1609.71,7172.28 R565.1@1510.71,7172.28
VCMO3: C188.1 R105.1 R574.1 R575.2 R576.2 U12.1 | length 277.9
  L1_Top Layer w11: R105.1@1456.03,2249.9 1457.88,2248.05 R574.1@1512.23,2248.05 ; U12.1@1456.7,2304.31 1518.2,2304.31 C188.1@1518.79,2304.9 1518.79,2254.6 R574.1@1512.23,2248.05 ; R576.2@1611.23,2248.05 R574.1@1512.23,2248.05
VCMO4: C222.1 R129.1 R583.1 R584.2 R585.2 U15.1 | length 277.9
  L1_Top Layer w11: R129.1@1456.11,830.56 1457.96,828.71 R583.1@1512.3,828.71 ; U15.1@1456.78,884.97 1518.27,884.97 C222.1@1518.86,885.56 1518.86,835.27 R583.1@1512.3,828.71 ; R585.2@1611.3,828.71 R583.1@1512.3,828.71
VCMO_LMH5401_1: C26.1 R2.2 R23.1 R24.2 U3.4 | length 1162.1
  L1_Top Layer w11: R2.2@762.53,9125.99 v2(805.14,9125.99) ; v2(1307,8743) 1307,8737.7 1307.71,8738.41 R23.1@1307.71,8701.26 1364.21,8701.26 U3.4@1364.8,8701.85 ; C26.1@1372.6,8756.26 1364.8,8748.46 U3.4@1364.8,8701.85 ; R24.2@1405.47,8596.26 1395.19,8606.53 1395.19,8695.93 1389.28,8701.85 U3.4@1364.8,8701.85
  L12_Bottom Layer w15: v2(805.14,9125.99) 827.42,9103.7 827.42,8824.58 909,8743 1306.29,8743 v2@1307,8742.29
VCMO_LMH5401_2: C60.1 R26.2 R47.1 R48.2 U6.4 | length 1162.3
  L1_Top Layer w11: R26.2@764.33,7703.86 v2(806.93,7703.86) ; v2(1310,7321) 1310,7315.8 1309.51,7316.28 R47.1@1309.51,7279.13 1366.01,7279.13 U6.4@1366.6,7279.72 ; C60.1@1374.39,7334.13 1366.6,7326.34 U6.4@1366.6,7279.72 ; R48.2@1407.27,7174.13 1396.99,7184.41 1396.99,7273.8 1391.07,7279.72 U6.4@1366.6,7279.72
  L12_Bottom Layer w15: v2(806.93,7703.86) 831.68,7679.11 831.68,7400.48 911.16,7321 v2(1310,7321)
VCMO_LMH5401_3: C186.1 R83.2 R104.1 R105.2 U12.4 | length 1166.3
  L1_Top Layer w11: R83.2@765.85,2779.63 v2(808.45,2779.63) ; v2@1311,2392.02 v2(1311,2397) ; v2@1311.03,2392.05 R104.1@1311.03,2354.9 1367.53,2354.9 U12.4@1368.12,2355.49 ; C186.1@1375.91,2409.9 1368.12,2402.1 U12.4@1368.12,2355.49 ; R105.2@1408.79,2249.9 1398.51,2260.17 1398.51,2349.57 1392.59,2355.49 U12.4@1368.12,2355.49
  L12_Bottom Layer w15: v2(808.45,2779.63) 832,2756.08 832,2468 903,2397 v2(1311,2397)
VCMO_LMH5401_4: C220.1 R107.2 R128.1 R129.2 U15.4 | length 1160.9
  L1_Top Layer w11: R107.2@765.92,1360.29 v2(808.53,1360.29) ; v2(1308.59,975.23) 1311.11,972.71 R128.1@1311.11,935.56 1367.6,935.56 U15.4@1368.19,936.15 ; C220.1@1375.99,990.56 1368.19,982.76 U15.4@1368.19,936.15 ; R129.2@1408.86,830.56 1398.59,840.84 1398.59,930.23 1392.67,936.15 U15.4@1368.19,936.15
  L12_Bottom Layer w15: v2(808.53,1360.29) 832.1,1336.72 832.1,1052.9 909.77,975.23 v2(1308.59,975.23)
VD1P1_ADC1: C149.1 C150.1 C151.1 C152.1 C153.1 C154.1 C155.1 C156.1 C157.1 C158.1 C159.1 C160.1 L39.2 TP6.1 U8.C9 U8.C10 U8.E9 U8.E10 U8.G7 U8.H7 U8.H9 U8.H10 U8.K9 U8.K10
  other v1: 2629.4,8076 2476.91,8114.86 2508.4,8114.86 2413.91,8177.85 2476.91,8177.85 2508.4,8177.85 2413.91,8209.35 2476.91,8272.34 2508.4,8272.34 2476.91,8335.33 2508.4,8335.33
  other v2: 2639.09,7965.35 2639.09,8027.35 2722.24,8973.41 2774.24,8973.41 2722.24,9025.41 2774.24,9025.41 2722.24,9077.41 2774.24,9077.41 2722.24,9129.41 2774.24,9129.41
VD1P1_ADC2: C309.1 C310.1 C311.1 C312.1 C313.1 C314.1 C315.1 C316.1 C317.1 C318.1 C319.1 C320.1 L40.2 TP12.1 U17.C9 U17.C10 U17.E9 U17.E10 U17.G7 U17.H7 U17.H9 U17.H10 U17.K9 U17.K10
  other v1: 2639.78,1731.37 2480.24,1768.86 2511.73,1768.86 2417.24,1831.85 2480.24,1831.85 2511.73,1831.85 2417.24,1863.35 2480.24,1926.34 2511.73,1926.34 2480.24,1989.33 2511.73,1989.33
  other v2: 2640.04,1619.24 2640.04,1682.24 2790,2624 2842,2624 2790,2672 2842,2672 2790,2724 2842,2724 2790,2776 2842,2776
VDDL19: C308.2 C442.2 C443.2 C445.2 C446.2 C448.2 C450.2 C452.2 C454.2 C456.2 C482.1 C483.1 C484.1 C512.2 L72.2 R380.1 R381.1 R382.1 R383.1 R384.1 R385.1 TP23.1 U26.15 U27.15 U28.5 U29.15 U30.15 U31.15 U32.15 U33.15 U74.9 U74.12 U74.13 U74.14 U74.16 | length 14562.1
  L1_Top Layer w8: v2(5133.59,4589) 5135.16,4589 U74.13@5172.78,4626.62 ; U74.12@5172.78,4662.81 5163,4653.03 5163,4636.4 U74.13@5172.78,4626.62 ; U74.14@5186.7,4612.7 U74.13@5172.78,4626.62 ; U74.16@5214.54,4584.86 5249,4550.4 v2(5249,4498) ; U74.9@5214.54,4704.57 5228.97,4719
  L1_Top Layer w11: C443.2@4808.82,9056.2 4851,9098.38 4851,9126.28 4877.94,9153.22 U27.15@4908.68,9153.22 ; v2(5661.82,9139.2) 5663.13,9140.51 R385.1@5663.13,9202.01 ; U26.15@5707,10486.95 5737.95,10486.95 5764,10513 5764,10543.77 C442.2@5810.35,10590.12
  L1_Top Layer w12: C450.2@3495.47,6532.22 3545.07,6581.82 3545.07,6611.73 3562.59,6629.24 U30.15@3595.33,6629.24 ; C454.2@3495.47,6976.93 3545.07,7026.53 3545.07,7056.43 3562.59,7073.95 U32.15@3595.33,7073.95 ; C452.2@3498.8,186.22 3548.4,235.82 3548.4,265.73 3565.92,283.25 U31.15@3598.66,283.25 ; C456.2@3498.8,630.93 3548.4,680.53 3548.4,710.44 3565.92,727.96 U33.15@3598.66,727.96
  L1_Top Layer w15: C445.2@6220.58,9767.75 v2(6220.58,9815.46) ; R382.1@6316.5,9696 v2(6316.5,9743.72) ; v2(6470.29,9629.5) R380.1@6518.01,9629.5
  L1_Top Layer w20: v2(3495.07,6930.43) 3495.47,6930.83 C454.2@3495.47,6976.93 ; C450.2@3495.47,6532.22 3528.06,6499.63 v2(3528.06,6499.06) ; v2(3498.4,584.44) 3498.8,584.84 C456.2@3498.8,630.93 ; C452.2@3498.56,185.98 3531.15,153.38 v2(3531.15,152.82) ; v2(4808,9013) 4808.82,9013.82 C443.2@4808.82,9056.2 ; 5228.97,4719 5262.59,4752.62 C512.2@5262.59,4758.41 5282,4777.81 5282,4805 v2(5272,4815) ; v2(5761,10597) 5803.46,10597 C442.2@5810.35,10590.12 ; R384.1@5837,9251.5 v2(5837,9299) ; R383.1@5925,9251.5 v2(5925,9299) ; R381.1@6024,9251.5 v2(6024,9299) ; C445.2@6220.58,9767.75 6241.4,9746.93 6239.72,9745.25 U28.5@6239.72,9704.31
  L4_Signal Layer 1 w20: v2(3528.06,6499.06) 3495.07,6532.05 v2(3495.07,6930.43) 3495.07,7087.07 3885,7477 v2(5536,7477)
  L10_Signal Layer 2 w30: v2(3498.4,584.44) 3498.4,185.57 v2(3531.15,152.82) 3578.97,105 4031,105 4404,478 4404,3942.92 5067.54,4606.46 5272.04,4810.96 5384,4922.92 5384,5866 5536,6018 5536,6558 5655,6677 5655,6902 5536,7021 v2(5536,7477) v2(5582,7477) v2@5584,7477
  L12_Bottom Layer w11: U29.15@5575.96,9189.02 5612,9189.02 v2(5661.82,9139.2)
  L12_Bottom Layer w15: v2(5249,4498) 5224.59,4498 C446.2@5100.3,4622.3 5086,4636.59 5086,4658 5211,4783 5243,4815 v2(5272,4815) 5272,4811 C308.2@5293.59,4789.41
  other v2: 6872.24,9577.83 6872.24,9612.83 6872.24,9647.83 6872.24,9682.83 6872.24,9717.83
VIN1_N: R552.2 R604.2 U8.A4 | length 229.4
  L1_Top Layer w10: U8.A4@2319.43,8398.32 ccw(c2315.21,8402.54) 2321.17,8402.54 R604.2@2321.17,8627.08 ; R552.2@2321.26,8627.43 R604.2@2321.36,8627.33
VIN1_P: R551.2 R592.2 U8.A5 | length 229.6
  L1_Top Layer w10: R592.2@2349.36,8627.2 R592.2@2349.27,8627.31 2349.17,8627.2 2349.17,8402.54 ccw(c2355.14,8402.54) U8.A5@2350.92,8398.32
VIN2_N: R561.2 R606.2 U8.M5 | length 229.4
  L1_Top Layer w10: R606.2@2349.08,7823.01 2349.17,7823.11 2349.17,8047.65 cw(c2355.14,8047.65) U8.M5@2350.92,8051.87
VIN2_P: R560.2 R605.2 U8.M4 | length 229.5
  L1_Top Layer w10: U8.M4@2319.43,8051.87 cw(c2315.2,8047.65) 2321.17,8047.65 2321.17,7822.98 R605.2@2321.08,7822.89
VIN3_N: R570.2 R608.2 U17.A4 | length 229.4
  L1_Top Layer w10: U17.A4@2322.76,2052.33 ccw(c2318.54,2056.55) 2324.5,2056.55 R608.2@2324.5,2281.09 ; R570.2@2324.59,2281.43 R608.2@2324.69,2281.33
VIN3_P: R569.2 R607.2 U17.A5 | length 229.3
  L1_Top Layer w10: R569.2@2352.5,2281.21 R607.2@2352.58,2280.94 2352.5,2056.55 ccw(c2358.47,2056.55) U17.A5@2354.25,2052.33
VIN4_N: R579.2 R610.2 U17.M5 | length 229.4
  L1_Top Layer w10: R610.2@2352.41,1477.01 2352.5,1477.11 2352.5,1701.65 cw(c2358.47,1701.65) U17.M5@2354.25,1705.87
VIN4_P: R578.2 R609.2 U17.M4 | length 229.3
  L1_Top Layer w10: U17.M4@2322.76,1705.87 cw(c2318.54,1701.65) 2324.5,1701.65 R578.2@2324.5,1476.99
VIO_B_M2C_RX1: J46.J39 J46.K40 R477.1 | length 137
  L1_Top Layer w11: R477.1@6245.48,6811.01 6245.48,6852.39 v1(6263.11,6870.01)
  L12_Bottom Layer w5: v1(6263.11,6870.01) J46.J39@6313.11,6920.01
VIO_B_M2C_RX2: J51.J39 J51.K40 R482.1 | length 137
  L1_Top Layer w11: R482.1@6249.13,467.81 6249.13,509.19 v1@6266.75,526.81
  L12_Bottom Layer w5: J51.K40@6266.75,526.81 J51.J39@6316.75,576.81
  other v1: 6266.44,524.01
VPHY: C457.1 C458.2 L32.2 U34.4 | length 265.5
  L1_Top Layer w10: U34.4@5520.39,9795.39 5564.42,9795.39 5572.47,9803.44 v2(5583.42,9803.44)
  L12_Bottom Layer w20: C458.2@5525.38,9770.97 5565.37,9770.97 5583.42,9789.02 v2(5583.42,9803.44) 5622.92,9803.44 C457.1@5631.39,9794.97 5631.39,9727.97 L32.2@5630.88,9727.47
VREGIN: C462.2 C463.2 C464.2 C465.2 C469.2 D17.1 J71.2 L32.1 L33.1 R543.1 U34.20 U34.31 U34.42 U34.50 U34.56 | length 884.9
  L1_Top Layer w10: U34.42@5083.38,9854.44 v2@5151.84,9854.44 ; v2@5157.87,9584.47 v2(5156.87,9585.47) 5156.87,9586.41 5173.93,9603.47 U34.50@5173.93,9665.47 ; U34.31@5173.93,10102.47 5173.93,10043.53 v2(5174.87,10044.47) ; v2(5291.87,9727.47) 5292.04,9727.3 U34.56@5292.04,9665.47 ; v2(5382.87,10033.47) 5390.47,10041.07 U34.20@5390.47,10102.47
  L1_Top Layer w11: D17.1@5630.88,9571.5 5630.88,9618.49 v2(5631.87,9619.47)
  L1_Top Layer w20: R543.1@5694.38,10024.97 5740.37,10024.97 v2(5740.87,10025.47)
  L12_Bottom Layer w20: v2(5156.87,9585.47) C469.2@5156.87,9666.48 ; C462.2@5173.38,10102.97 5174.87,10101.48 v2(5174.87,10044.47) ; C465.2@5284.17,9665.47 5284.17,9719.77 v2(5291.87,9727.47) ; C464.2@5382.59,10102.47 5382.59,10033.75 v2(5382.87,10033.47) ; L32.1@5630.88,9664.47 5630.88,9620.46 v2(5631.87,9619.47) ; L33.1@5694.38,9959.97 5740.37,9959.97 v2(5740.87,9960.47)
  L12_Bottom Layer w30: C463.2@5083.38,9846.57 5143.97,9846.57 v2(5151.87,9854.47)
pads on no net: FID1.1 FID2.1 FID3.1 FID4.1 FID5.1 FID6.1 J31.1 J31.7 J31.10 J32.1 J32.7 J39.7 J46.A21 J46.A22 J46.A23 J46.A26 J46.A27 J46.A30 J46.A31 J46.A34 J46.A35 J46.A38 J46.A39 J46.B1 J46.B2 J46.B19 J46.B20 J46.B21 J46.B22 J46.B23 J46.B24 J46.B25 J46.B28 J46.B29 J46.B32 J46.B33 J46.B36 J46.B37 J46.B40 J46.C1 J46.C2 J46.C3 J46.C4 J46.C9 J46.C10 J46.C11 J46.C12 J46.C13 J46.C14 J46.C15 J46.C16 J46.C17 J46.C18 J46.C19 J46.C20 J46.C21 J46.C22 J46.C23 J46.C26 J46.C27 J46.D2 J46.D7 J46.D8 J46.D9 J46.D10 J46.D11 J46.D12 J46.D13 J46.D14 J46.D15 J46.D16 J46.D17 J46.D18 J46.D19 J46.D20 J46.D21 J46.D22 J46.D23 J46.D24 J46.D27 J46.D29 J46.D33 J46.D34 J46.E1 J46.E2 J46.E3 J46.E4 J46.E5 J46.E6 J46.E7 J46.E8 J46.E9 J46.E10 J46.E11 J46.E12 J46.E13 J46.E14 J46.E15 J46.E16 J46.E17 J46.E18 J46.E19 J46.E20 J46.E21 J46.E22 J46.E23 J46.E24 J46.E25 J46.E27 J46.E28 J46.E30 J46.E31 J46.E33 J46.E34 J46.E36 J46.E37 J46.F2 J46.F3 J46.F4 J46.F5 J46.F6 J46.F7 J46.F8 J46.F9 J46.F10 J46.F11 J46.F12 J46.F13 J46.F14 J46.F15 J46.F16 J46.F17 J46.F18 J46.F19 J46.F20 J46.F21 J46.F22 J46.F23 J46.F24 J46.F25 J46.F26 J46.F28 J46.F29 J46.F31 J46.F32 J46.F34 J46.F35 J46.F37 J46.F38 J46.G1 J46.G2 J46.G3 J46.G4 J46.G15 J46.G16 J46.G17 J46.G18 J46.G19 J46.G20 J46.G21 J46.G22 J46.G23 J46.G24 J46.G25 J46.G28 J46.G30 J46.G31 J46.G33 J46.G34 J46.G36 J46.G37 J46.H1 J46.H3 J46.H4 J46.H5 J46.H6 J46.H7 J46.H8 J46.H9 J46.H10 J46.H11 J46.H12 J46.H13 J46.H14 J46.H15 J46.H16 J46.H17 J46.H18 J46.H19 J46.H20 J46.H21 J46.H22 J46.H23 J46.H24 J46.H25 J46.H26 J46.H28 J46.H29 J46.H32 J46.H34 J46.H35 J46.H37 J46.H38 J46.J1 J46.J2 J46.J3 J46.J4 J46.J5 J46.J6 J46.J7 J46.J8 J46.J9 J46.J10 J46.J11 J46.J12 J46.J13 J46.J14 J46.J16 J46.J17 J46.J18 J46.J19 J46.J20 J46.J21 J46.J22 J46.J23 J46.J24 J46.J25 J46.J26 J46.J27 J46.J28 J46.J30 J46.J31 J46.J33 J46.J34 J46.J36 J46.J37 J46.K1 J46.K2 J46.K3 J46.K4 J46.K5 J46.K6 J46.K7 J46.K8 J46.K9 J46.K10 J46.K11 J46.K12 J46.K13 J46.K14 J46.K15 J46.K16 J46.K17 J46.K18 J46.K19 J46.K20 J46.K21 J46.K22 J46.K23 J46.K24 J46.K25 J46.K26 J46.K27 J46.K28 J46.K29 J46.K31 J46.K32 J46.K34 J46.K35 J46.K37 J46.K38 J46.L1 J46.L2 J46.L3 J46.L4 J46.L5 J46.L6 J46.L7 J46.L8 J46.L9 J46.L10 J46.L11 J46.L12 J46.L13 J46.L14 J46.L15 J46.L16 J46.L17 J46.L18 J46.L19 J46.L20 J46.L21 J46.L22 J46.L23 J46.L24 J46.L25 J46.L26 J46.L27 J46.L28 J46.L29 J46.L32 J46.L33 J46.L36 J46.L37 J46.L40 J46.M2 J46.M3 J46.M4 J46.M5 J46.M6 J46.M7 J46.M8 J46.M9 J46.M10 J46.M11 J46.M12 J46.M13 J46.M14 J46.M15 J46.M16 J46.M17 J46.M18 J46.M19 J46.M20 J46.M21 J46.M22 J46.M23 J46.M24 J46.M25 J46.M26 J46.M27 J46.M28 J46.M30 J46.M31 J46.M34 J46.M35 J46.M38 J46.M39 J46.MH1 J46.MH2 J46.Y1 J46.Y2 J46.Y3 J46.Y6 J46.Y7 J46.Y26 J46.Y27 J46.Y30 J46.Y31 J46.Y34 J46.Y35 J46.Y38 J46.Y39 J46.Z4 J46.Z5 J46.Z6 J46.Z8 J46.Z9 J46.Z24 J46.Z25 J46.Z28 J46.Z29 J46.Z32 J46.Z33 J46.Z36 J46.Z37 J46.Z40 J51.A21 J51.A22 J51.A23 J51.A26 J51.A27 J51.A30 J51.A31 J51.A34 J51.A35 J51.A38 J51.A39 J51.B1 J51.B2 J51.B19 J51.B20 J51.B21 J51.B22 J51.B23 J51.B24 J51.B25 J51.B28 J51.B29 J51.B32 J51.B33 J51.B36 J51.B37 J51.B40 J51.C1 J51.C2 J51.C3 J51.C4 J51.C9 J51.C10 J51.C11 J51.C12 J51.C13 J51.C14 J51.C15 J51.C16 J51.C17 J51.C18 J51.C19 J51.C20 J51.C21 J51.C22 J51.C23 J51.C26 J51.C27 J51.D2 J51.D7 J51.D8 J51.D9 J51.D10 J51.D11 J51.D12 J51.D13 J51.D14 J51.D15 J51.D16 J51.D17 J51.D18 J51.D19 J51.D20 J51.D21 J51.D22 J51.D23 J51.D24 J51.D27 J51.D29 J51.D33 J51.D34 J51.E1 J51.E2 J51.E3 J51.E4 J51.E5 J51.E6 J51.E7 J51.E8 J51.E9 J51.E10 J51.E11 J51.E12 J51.E13 J51.E14 J51.E15 J51.E16 J51.E17 J51.E18 J51.E19 J51.E20 J51.E21 J51.E22 J51.E23 J51.E24 J51.E25 J51.E27 J51.E28 J51.E30 J51.E31 J51.E33 J51.E34 J51.E36 J51.E37 J51.F2 J51.F3 J51.F4 J51.F5 J51.F6 J51.F7 J51.F8 J51.F9 J51.F10 J51.F11 J51.F12 J51.F13 J51.F14 J51.F15 J51.F16 J51.F17 J51.F18 J51.F19 J51.F20 J51.F21 J51.F22 J51.F23 J51.F24 J51.F25 J51.F26 J51.F28 J51.F29 J51.F31 J51.F32 J51.F34 J51.F35 J51.F37 J51.F38 J51.G1 J51.G2 J51.G3 J51.G4 J51.G15 J51.G16 J51.G17 J51.G18 J51.G19 J51.G20 J51.G21 J51.G22 J51.G23 J51.G24 J51.G25 J51.G28 J51.G30 J51.G31 J51.G33 J51.G34 J51.G36 J51.G37 J51.H1 J51.H3 J51.H4 J51.H5 J51.H6 J51.H7 J51.H8 J51.H9 J51.H10 J51.H11 J51.H12 J51.H13 J51.H14 J51.H15 J51.H16 J51.H17 J51.H18 J51.H19 J51.H20 J51.H21 J51.H22 J51.H23 J51.H24 J51.H25 J51.H26 J51.H28 J51.H29 J51.H32 J51.H34 J51.H35 J51.H37 J51.H38 J51.J1 J51.J2 J51.J3 J51.J4 J51.J5 J51.J6 J51.J7 J51.J8 J51.J9 J51.J10 J51.J11 J51.J12 J51.J13 J51.J14 J51.J16 J51.J17 J51.J18 J51.J19 J51.J20 J51.J21 J51.J22 J51.J23 J51.J24 J51.J25 J51.J26 J51.J27 J51.J28 J51.J30 J51.J31 J51.J33 J51.J34 J51.J36 J51.J37 J51.K1 J51.K2 J51.K3 J51.K4 J51.K5 J51.K6 J51.K7 J51.K8 J51.K9 J51.K10 J51.K11 J51.K12 J51.K13 J51.K14 J51.K15 J51.K16 J51.K17 J51.K18 J51.K19 J51.K20 J51.K21 J51.K22 J51.K23 J51.K24 J51.K25 J51.K26 J51.K27 J51.K28 J51.K29 J51.K31 J51.K32 J51.K34 J51.K35 J51.K37 J51.K38 J51.L1 J51.L2 J51.L3 J51.L4 J51.L5 J51.L6 J51.L7 J51.L8 J51.L9 J51.L10 J51.L11 J51.L12 J51.L13 J51.L14 J51.L15 J51.L16 J51.L17 J51.L18 J51.L19 J51.L20 J51.L21 J51.L22 J51.L23 J51.L24 J51.L25 J51.L26 J51.L27 J51.L28 J51.L29 J51.L32 J51.L33 J51.L36 J51.L37 J51.L40 J51.M2 J51.M3 J51.M4 J51.M5 J51.M6 J51.M7 J51.M8 J51.M9 J51.M10 J51.M11 J51.M12 J51.M13 J51.M14 J51.M15 J51.M16 J51.M17 J51.M18 J51.M19 J51.M20 J51.M21 J51.M22 J51.M23 J51.M24 J51.M25 J51.M26 J51.M27 J51.M28 J51.M30 J51.M31 J51.M34 J51.M35 J51.M38 J51.M39 J51.MH1 J51.MH2 J51.Y1 J51.Y2 J51.Y3 J51.Y6 J51.Y7 J51.Y26 J51.Y27 J51.Y30 J51.Y31 J51.Y34 J51.Y35 J51.Y38 J51.Y39 J51.Z4 J51.Z5 J51.Z6 J51.Z8 J51.Z9 J51.Z24 J51.Z25 J51.Z28 J51.Z29 J51.Z32 J51.Z33 J51.Z36 J51.Z37 J51.Z40 J58.2 J58.3 J58.4 J58.5 J58.6 J58.7 J58.8 J58.9 J58.10 J72.4 LBL1.0 Q3.0 S1.1 S2.1 S3.1 S4.1 S5.1 S6.1 S7.1 S8.1 S9.1 S10.1 S11.1 S12.1 S17.3 T1.2 T2.2 U2. U5. U9.1 U9.3 U9.4 U11. U14. U18.1 U18.3 U18.4 U23.11 U23.12 U23.18 U23.19 U23.21 U23.22 U23.25 U23.26 U23.27 U23.29 U23.31 U24.8 U24.9 U25.1@5590.22,5913 U25.1@5621.72,5913 U25.2@5490.22,5913 U25.2@5521.72,5913 U25.3@5390.22,5913 U25.3@5421.72,5913 U25.4@5390.22,6058.67 U25.4@5421.72,6058.67 U25.5@5490.22,6058.67 U25.5@5521.72,6058.67 U25.6@5590.22,6058.67 U25.6@5621.72,6058.67 U29.6 U29.11 U34.36 U34.60 U35.4 U36.7 U37.7 U38.9 U38.11@4994.86,11231.57 U38.11@4994.86,11352.04 U38.11@5004.7,11267 U38.11@5004.7,11316.61 U38.11@5014.54,11231.57 U38.11@5014.54,11352.04 U39.0 U42.0 U45.0 U48.0 U50.5 U50.6 U50.7 U50.9 U50.10 U50.11 U51.0 U51.7 U53.2 U53.4 U53.5 U53.6 U53.8 U53.9 U53.10 U53.11 U53.12 U53.17 U53.18 U53.19 U56.6 U56.7 U58.10 U58.11 U58.12 U74.3

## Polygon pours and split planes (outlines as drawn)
12VIN on L1_Top Layer "GNGN" (solid, pour order 937): 21 vertices, not listed, extent 977,11385 4268.73,11587
12V on L1_Top Layer "GNGN" (solid, pour order 936): 26 vertices, not listed, extent 4336,11132.13 4964.01,11516
GND on L1_Top Layer "GNGN" (solid, pour order 929): 27 vertices, not listed, extent 237,10649 692,10921
NetC519_1 on L1_Top Layer "L1_Top Layer-No Net" (solid, pour order 916): 21 vertices, not listed, extent 3035.03,10597.01 3221.57,10918.01
DGND on L1_Top Layer "12" (solid, remove dead copper, pour order 894): 107 vertices, not listed, extent 1262,70 6899,10801
NetC538_1 on L1_Top Layer "L1_Top Layer-No Net" (solid, pour order 910): 1856.74,11189.14 1878.63,11211.03 2012.68,11211.03 2028.92,11194.78 2028.92,11138.83 2028.92,10893.7 1995.23,10860 1868.71,10860 1856.74,10871.97
NetC587_1 on L1_Top Layer "L1_Top Layer-No Net" (solid, pour order 909): 17 vertices, not listed, extent 2055.93,10946.86 2406.74,11179.86
NetC495_1 on L1_Top Layer "L1_Top Layer-No Net" (solid, pour order 907): 2724.48,11194.14 2741.01,11210.66 2885.34,11210.66 2902.44,11193.56 2902.44,11138.46 2902.44,10892.44 2869,10859 2741.07,10859 2724.48,10875.59
NetC516_1 on L1_Top Layer "L1_Top Layer-No Net" (solid, pour order 906): 17 vertices, not listed, extent 2936.51,10946.01 3221.57,11179.01
NetC655_1 on L1_Top Layer "L1_Top Layer-No Net" (solid, pour order 904): 20 vertices, not listed, extent 1343.81,10948.73 1613.87,11181.73
NetC647_1 on L1_Top Layer "L1_Top Layer-No Net" (solid, pour order 903): 1114.52,11200.52 1128.3,11214.3 1270.84,11214.3 1292.49,11192.65 1292.49,11119.49 1292.49,10893.17 1259.97,10860.65 1132.35,10860.65 1114.52,10878.48
3P5_VIN on L1_Top Layer "L1_Top Layer-No Net" (solid, pour order 902): 3564,11193.43 3578.14,11207.57 3724.25,11207.57 3734.7,11197.13 3734.7,11127.41 3734.7,10884.25 3705.98,10855.54 3578.87,10855.53 3564,10870.41
V3P3 on L1_Top Layer "L1_Top Layer-No Net" (solid, pour order 772): 2822,4769 2733,4769 2727,4763 2727,4616 2735,4608 2832,4608 2878,4608 2893,4623 2893,4663 2890,4666 2836,4666 2834,4668 2834,4769
V3P3 on L1_Top Layer "12" (solid, pour order 893): 4650,10668 4615.15,10668 4606,10677.14 4606,10784 4623,10801 4670,10801 4674,10797 4674,10678 4664,10668
DGND on L1_Top Layer "12" (solid, pour order 891): 2216,1522 2129,1522 2124,1527 2124,1673 2143,1692 2180,1692 2191,1681 2191,1596 2197,1590 2213,1590 2216,1587 2216,1525 2213,1522
DGND on L1_Top Layer "12" (solid, pour order 890): 2129,7867 2134,7862 2206,7862 2213,7869 2213,8031 2199,8045 2142,8045 2129,8032
AGND on L1_Top Layer "12" (solid, pour order 844): 248,10255 688,10255 704,10239 704,10001 693,9990 250,9990 238,10002 238,10245 248,10255
AGND on L1_Top Layer "12" (solid, pour order 846): 1048,10255 1487,10255 1503,10239 1503,9998 1495,9990 1050,9990 1038,10002 1038,10245 1048,10255
V3P3 on L1_Top Layer "12" (solid, pour order 877): 5890,4047 5487.84,3644.84 5374.65,3644.84 5286.84,3644.84 5272,3630 5272,3520 5279,3513 5965.59,3513 6019.07,3566.48 6019.07,4087.07 6019.07,5187.93 6008,5199 5904,5199 5890,5185
DGND on L1_Top Layer "V" (solid, pour order 808): 2119,10255 2344,10255 2360,10239 2360,9998 2352,9990 2107,9990 2095,10002 2095,10221 2095,10245 2105,10255
DGND on L1_Top Layer "V" (solid, pour order 807): 2719,10255 2844,10255 2860,10239 2860,10001 2849,9990 2707,9990 2695,10002 2695,10221 2695,10245 2705,10255
NetC414_2 on L1_Top Layer "L1_Top Layer-No Net" (solid, pour order 781): 5599,5853 5512.86,5853 5505.97,5846.11 5505.97,5712.03 5514,5704 5595,5704 5602,5711 5602,5851 5600,5853
GND on L1_Top Layer "h" (solid, pour order 728): 26 vertices, not listed, extent 4657,11060.73 5190.32,11465.73
DGND on L1_Top Layer "h" (solid, pour order 719): 1294.94,5158.3 1408.94,5158.3 1442.94,5124.3 1570.61,5124.3 1588.94,5105.96 1588.94,5009.3 1576.94,4997.3 1297.94,4997.3 1277.39,5017.84 1277.39,5148.75 1286.94,5158.3
V3P3_LMX1 on L1_Top Layer "h" (solid, pour order 718): 1297.94,5175.3 1674.6,5175.3 1685.6,5186.3 1685.6,5387.64 1672.94,5400.3 1288.94,5400.3 1277.39,5388.75 1277.39,5185.61 1287.7,5175.3
DGND on L1_Top Layer "h" (solid, pour order 717): 3072.57,6173.77 3187.57,6173.77 3197.57,6163.77 3197.57,6056.77 3177.57,6036.77 2980.57,6036.77 2970.57,6046.77 2970.57,6165.77 2978.57,6173.77
V3P3_LMX1RF on L1_Top Layer "h" (solid, pour order 716): 2886.57,6192.77 3189.57,6192.77 3198.57,6201.77 3198.57,6400.77 3180.57,6418.77 3174.57,6424.77 3023.57,6424.77 2888.57,6424.77 2867.57,6403.77 2867.57,6211.77
V3P3_LMX2RF on L1_Top Layer "h" (solid, pour order 720): 1457.92,4312.38 1457.92,4009.38 1466.92,4000.38 1665.92,4000.38 1683.92,4018.38 1689.92,4024.38 1689.92,4175.38 1689.92,4310.38 1668.92,4331.38 1476.92,4331.38
DGND on L1_Top Layer "h" (solid, pour order 721): 1438.92,4126.38 1438.92,4011.38 1428.92,4001.38 1321.92,4001.38 1301.92,4021.38 1301.92,4218.38 1311.92,4228.38 1430.92,4228.38 1438.92,4220.38
V3P3_LMX2 on L1_Top Layer "h" (solid, pour order 722): 1783.57,4656.9 1406.91,4656.9 1395.91,4645.9 1395.91,4543.09 1507.1,4431.9 1792.57,4431.9 1810.57,4449.9 1810.57,4646.9 1800.57,4656.9
DGND on L1_Top Layer "h" (solid, pour order 723): 1786.57,4673.9 1672.57,4673.9 1638.57,4707.9 1510.9,4707.9 1492.57,4726.23 1492.57,4822.9 1504.57,4834.9 1783.57,4834.9 1801.57,4816.9 1801.57,4680.9 1794.57,4673.9
DGND on L1_Top Layer "h" (solid, pour order 724): 4950,3675 5064,3675 5098,3641 5203.24,3641 5229.23,3615.01 5229.23,3524.01 5219.22,3514 4953,3514 4935,3532 4935,3668 4942,3675
V3P3_LMK48XX on L1_Top Layer "h" (solid, pour order 725): 4952.23,3695.01 5343.23,3695.01 5349.23,3701.01 5349.23,3892.01 5338.23,3903.01 5333.23,3908.01 5223.23,3908.01 5026.23,3908.01 4942.23,3824.01 4942.23,3702.01 4949.23,3695.01
DGND on L1_Top Layer "h" (solid, pour order 729): 3943.07,6933.73 3995,6933.73 3995,7044.73 3988,7051.73 3939.07,7051.73 3930.07,7042.73 3930.07,6939.73 3936.07,6933.73
V3P3_VDD on L1_Top Layer "h" (solid, pour order 730): 4876.4,10598.82 4980.4,10598.82 4992.4,10586.82 4992.4,10450.4 4956.82,10414.82 4627.4,10414.82 4608.4,10433.82 4608.4,10585.82 4621.4,10598.82
DGND on L1_Top Layer "h" (solid, pour order 731): 4966.4,10611.82 4868.4,10611.82 4851.4,10628.82 4835.4,10644.82 4717.4,10644.82 4707.34,10644.82 4696.47,10655.69 4696.47,10711.9 4696.47,10733.9 4702.4,10739.82 4717.4,10754.82 4972.4,10754.82 5001.4,10725.82 5001.4,10619.82 4993.4,10611.82
AGND on L1_Top Layer "V" (solid, pour order 735): 793.19,9440.93 683.19,9440.93 673.19,9450.93 673.19,9550.93 683.19,9560.93 888.19,9560.93 898.19,9550.93 898.19,9495.93 888.19,9485.93 838.19,9485.93
VA2P5 on L1_Top Layer "V" (solid, pour order 736): 1155.93,9380.93 998.19,9380.93 988.19,9390.93 988.19,9503.19 995.03,9510.03 1154.97,9510.02 1162,9503 1162,9387
VA2P5 on L1_Top Layer "V" (solid, pour order 742): 1155.8,7958.8 999.99,7958.8 989.99,7968.8 989.99,8078.99 998,8087 1156,8087 1165,8078 1165,7968
AGND on L1_Top Layer "V" (solid, pour order 743): 794.99,8018.8 684.99,8018.8 674.99,8028.8 674.99,8128.8 684.99,8138.8 889.99,8138.8 899.99,8128.8 899.99,8073.8 889.99,8063.8 839.99,8063.8
VA2P5 on L1_Top Layer "V" (solid, pour order 753): 1159.5,3031.5 1001.09,3031.5 991.09,3041.5 991.09,3157.09 1002,3168 1154,3168 1166,3156 1166,3038
AGND on L1_Top Layer "V" (solid, pour order 754): 796.09,3091.5 686.09,3091.5 676.09,3101.5 676.09,3201.5 686.09,3211.5 891.09,3211.5 901.09,3201.5 901.09,3146.5 891.09,3136.5 841.09,3136.5
VA2P5 on L1_Top Layer "V" (solid, pour order 758): 1159.17,1616.23 1000.17,1616.23 990.17,1626.23 990.17,1740.22 995,1745.06 1161,1745.06 1165,1741.06 1165,1622.06
AGND on L1_Top Layer "V" (solid, pour order 759): 795.17,1676.23 685.17,1676.23 675.17,1686.23 675.17,1786.23 685.17,1796.23 890.17,1796.23 900.17,1786.23 900.17,1731.23 890.17,1721.23 840.17,1721.23
NetC715_2 on L1_Top Layer "V" (solid, pour order 763): 768.62,10943.88 551.62,10943.88 521,10974.49 521,11107.85 540.15,11127 853.09,11127 862.61,11117.47 862.62,10981.88 859.62,10978.88 783.62,10978.88 778.62,10973.88 778.61,10948.88 773.62,10943.88
12V_DC on L1_Top Layer "V" (solid, pour order 768): 19 vertices, not listed, extent 5049,10973.07 5799,11346.07
NetJ55_1 on L1_Top Layer "V" (solid, pour order 769): 18 vertices, not listed, extent 5684,10946.07 6434,11269.07
GND1 on L1_Top Layer "V" (solid, pour order 771): 24 vertices, not listed, extent 5032,11099.07 6461,11587
V3P3_LMK00304 on L1_Top Layer "L1_Top Layer-No Net" (solid, pour order 773): 2815,4446 2760,4446 2752,4454 2752,4544 2760,4552 2882,4552 2913,4583 2913,4665 2946,4698 3029,4698 3043,4684 3043,4465 3024,4446 2821,4446
DGND on L1_Top Layer "L1_Top Layer-No Net" (solid, pour order 774): 3034,4422 2794,4422 2786,4414 2786,4367 2791,4362 3031,4362 3044,4375 3044,4412
V3P3_LMK61E2 on L1_Top Layer "L1_Top Layer-No Net" (solid, pour order 777): 5844,5393 5844,5556 5906,5618 6006.41,5618 6018.28,5606.13 6018.28,5306.28 5997,5285 5854,5285 5844,5295
DGND on L1_Top Layer "L1_Top Layer-No Net" (solid, pour order 778): 5817,5404 5817,5297 5807,5287 5702,5287 5691,5298 5691,5436 5703,5448 5810,5448 5817,5441
VDDL19 on L1_Top Layer "L1_Top Layer-No Net" (solid, pour order 779): 6786.38,9357 6878.54,9357 6898,9376.46 6898,9810.58 6885.78,9822.8 6792.11,9822.8 6778.11,9808.8 6773.11,9803.8 6773.11,9676.8 6773.11,9370.27
DGND on L1_Top Layer "L1_Top Layer-No Net" (solid, pour order 780): 6654.11,9730.8 6642.11,9718.8 6642.11,9526.8 6654.11,9514.8 6734.11,9514.8 6741.11,9521.8 6741.11,9635.8 6749.11,9643.8 6749.11,9727.8 6746.11,9730.8
DGND on L1_Top Layer "V" (solid, pour order 788): 3219,10255 3344,10255 3360,10239 3360,10001 3349,9990 3207,9990 3195,10002 3195,10221 3195,10245 3205,10255
V1P1V on L1_Top Layer "V" (solid, pour order 789): 2520,10255 2645,10255 2661,10239 2661,10002 2649,9990 2403,9990 2392.99,10000 2393,10248 2400,10255
V1P9V on L1_Top Layer "V" (solid, pour order 792): 3019,10255 3144,10255 3160,10239 3160,10002 3148,9990 2902,9990 2891.99,10000 2892,10248 2899,10255
V3P3 on L1_Top Layer "V" (solid, pour order 793): 3519,10255 3644,10255 3660,10239 3660,10002 3648,9990 3402,9990 3391.99,10000 3392,10248 3399,10255
VA2P5 on L1_Top Layer "V" (solid, pour order 796): 1663,10255 1788,10255 1804,10239 1804,10002 1792,9990 1546,9990 1535.99,10000 1536,10248 1543,10255
VA_N2P5 on L1_Top Layer "V" (solid, pour order 797): 862,10255 987,10255 1003,10239 1003,10002 991,9990 745,9990 734.99,10000 735,10248 742,10255
NetC714_1 on L1_Top Layer "V" (solid, pour order 824): 717,10602 626,10602 618,10610 618,10738.3 624.7,10745 703.32,10745 711.46,10753.14 711.46,10848.93 718.52,10856 764.04,10856 808,10812.04 808,10617.57 792.43,10602
NetC695_2 on L1_Top Layer "V" (solid, pour order 825): 407.64,10819.1 250.9,10819.1 229,10841 229,11190.3 259.7,11221 471.27,11221 484,11208.27 484,10895.46 454,10865.46
VA2P5_IN on L1_Top Layer "V" (solid, pour order 827): 19 vertices, not listed, extent 1301.08,10288 1819,10823.61
V1P1V_IN on L1_Top Layer "V" (solid, pour order 830): 20 vertices, not listed, extent 2037.9,10289 2656.9,10823
GND on L1_Top Layer "12" (solid, pour order 835): 3196,10424 3581.65,10809.65 3693,10809.65 3693,10471.63 3406.63,10471.63 3365,10430 3361,10426 3361,10408 3361,10301 3351,10291 3212,10291 3196,10307
V1P9V on L1_Top Layer "h" (solid, remove dead copper, pour order 841): 6568.22,9808.96 6568.22,9744.96 6573.22,9739.96 6699.27,9739.96 6706.11,9746.8 6706.11,9874.8 6687.1,9893.81 6587.28,9893.81 6568.22,9874.75
VA_N2P5_IN on L1_Top Layer "12" (solid, pour order 842): 18 vertices, not listed, extent 490,10288 1010,10833
GND on L1_Top Layer "12" (solid, pour order 843): 498,10291 688,10291 704,10307 704,10402 690,10416 492,10416 458,10450 458,10724.21 445.21,10737 251.03,10737 237,10722.97 237,10307 253,10291
V3P3 on L1_Top Layer "12" (solid, remove dead copper, pour order 866): 2934,6079 2878,6079 2871.43,6072.43 2871.43,5897.57 2883,5886 3036.72,5886 3046.3,5895.58 3046.3,5972.43 3039.72,5979 2956,5979 2937,5998 2937,6076
V3P3 on L1_Top Layer "12" (solid, pour order 867): 21 vertices, not listed, extent 1277.39,4257 1700,5065.9
DGND on L1_Top Layer "12" (solid, pour order 892): 18 vertices, not listed, extent 4147,9106 4223,9295.34
NetC613_1 on L1_Top Layer "L1_Top Layer-No Net" (solid, pour order 901): 19 vertices, not listed, extent 3789.4,10942 4058.54,11175
GND on L1_Top Layer "L1_Top Layer-No Net" (solid, pour order 913): 23 vertices, not listed, extent 3641.49,10471.63 3967.49,10938.63
V3P3_IN on L1_Top Layer "L1_Top Layer-No Net" (solid, pour order 914): 20 vertices, not listed, extent 3393,10289 3950.91,10817.59
NetC616_1 on L1_Top Layer "L1_Top Layer-No Net" (solid, pour order 915): 21 vertices, not listed, extent 3872,10593 4058.54,10914
GND on L1_Top Layer "L1_Top Layer-No Net" (solid, pour order 917): 20 vertices, not listed, extent 2805.53,10474.62 3131.53,10941.62
V1P9V_IN on L1_Top Layer "L1_Top Layer-No Net" (solid, pour order 919): 18 vertices, not listed, extent 2891,10288 3162,10823
GND on L1_Top Layer "L1_Top Layer-No Net" (solid, pour order 920): 2696,10307 2696,10803 2713.89,10820.89 2863.29,10820.89 2871.4,10829 2891.72,10829 2899.84,10820.89 2899.84,10813.48 2861.35,10775 2861,10774.65 2861,10301 2851,10291 2712,10291 2696,10307
GND on L1_Top Layer "L1_Top Layer-No Net" (solid, pour order 922): 20 vertices, not listed, extent 1931.7,10475.48 2257.7,10942.48
GND on L1_Top Layer "L1_Top Layer-No Net" (solid, pour order 923): 17 vertices, not listed, extent 1859.67,10291 2364,10820
NetC590_1 on L1_Top Layer "L1_Top Layer-No Net" (solid, pour order 924): 21 vertices, not listed, extent 2161.2,10597.86 2347.74,10918.86
GND on L1_Top Layer "L1_Top Layer-No Net" (solid, pour order 926): 20 vertices, not listed, extent 1197.83,10477.34 1523.83,10944.34
GND on L1_Top Layer "L1_Top Layer-No Net" (solid, pour order 927): 18 vertices, not listed, extent 1038,10291 1505,10818
NetC660_1 on L1_Top Layer "L1_Top Layer-No Net" (solid, pour order 928): 21 vertices, not listed, extent 1427.33,10599.73 1613.87,10920.73
GND on L1_Top Layer "Top Layer-No Net" (solid, pour order 739): 36 vertices, not listed, extent 20,10303.82 1007.66,11587
GND on L1_Top Layer "Top Layer-No Net" (solid, remove dead copper, pour order 740): 25 vertices, not listed, extent 1038.45,10844 1798.48,11376
GND on L1_Top Layer "Top Layer-No Net" (solid, remove dead copper, pour order 741): 41 vertices, not listed, extent 1875,11135.14 2645.31,11488
GND on L1_Top Layer "Top Layer-No Net" (solid, pour order 744): 50 vertices, not listed, extent 3971.54,10286.72 6865,11587
VA2P5_LMH5401_2 on L1_Top Layer "GNGN" (solid, remove dead copper, pour order 992): 34 vertices, not listed, extent 506.95,7717.07 1017.35,8046.87
VA2P5_LMH5401_3 on L1_Top Layer "GNGN" (solid, remove dead copper, pour order 994): 32 vertices, not listed, extent 508.47,2792.84 1018.64,3122.64
VA2P5_LMH5401_4 on L1_Top Layer "GNGN" (solid, remove dead copper, pour order 996): 33 vertices, not listed, extent 508.55,1373.5 1019.19,1703.3
VA2P5_LMH5401_1 on L1_Top Layer "GNGN" (solid, remove dead copper, pour order 990): 33 vertices, not listed, extent 505.16,9139.2 1015.47,9469
VA_N2P5_LMH5401_1 on L1_Top Layer "V" (solid, pour order 1012): 776.63,8301.83 984.31,8301.83 1000.98,8318.5 1000.98,8575.02 984.17,8591.83 774.46,8591.83 764.46,8581.83 764.46,8466.83 764.46,8313.99
VA_N2P5_LMH5401_2 on L1_Top Layer "V" (solid, pour order 1014): 780.22,6880.57 992.63,6880.57 1006,6893.95 1006,7159.82 995.24,7170.58 778.06,7170.57 768.06,7160.57 768.06,7045.57 768.06,6892.74
VA_N2P5_LMH5401_3 on L1_Top Layer "V" (solid, pour order 1022): 782.53,1956.32 984.4,1956.32 1002.39,1974.31 1002.39,2228.85 984.91,2246.33 780.37,2246.32 770.37,2236.32 770.37,2121.32 770.37,1968.49
VA_N2P5_LMH5401_4 on L1_Top Layer "V" (solid, pour order 1026): 781.99,535.37 989.79,535.37 1005.85,551.43 1005.85,812.54 993.02,825.37 779.83,825.37 769.83,815.37 769.83,700.37 769.83,547.53
VA_N2P5 on L1_Top Layer "12" (solid, pour order 1036): 747.59,532.43 747.59,577.43 747.59,591.43 629.59,591.43 620.59,582.43 620.59,545.43 620.59,437.43 628.79,429.23 736.54,429.23 747.47,440.15
VA_N2P5 on L1_Top Layer "12" (solid, pour order 1038): 747.21,1951.55 747.21,1996.55 747.21,2010.55 629.21,2010.55 620.21,2001.55 620.21,1964.55 620.21,1856.55 628.41,1848.36 736.16,1848.36 747.09,1859.27
VA_N2P5 on L1_Top Layer "12" (solid, pour order 1040): 743.2,8298.13 743.2,8343.13 743.2,8357.13 625.2,8357.13 616.2,8348.13 616.2,8311.13 616.2,8203.13 624.4,8194.93 732.15,8194.93 743.08,8205.85
VA_N2P5 on L1_Top Layer "12" (solid, pour order 1042): 745,6876 745,6921 745,6935 627,6935 618,6926 618,6889 618,6781 626.19,6772.81 733.94,6772.8 744.87,6783.72
AGND on L1_Top Layer "12" (solid, remove dead copper, pour order 1046): 95 vertices, not listed, extent 17.27,71 2555.33,10255
DGND on L12_Bottom Layer "12" (solid, remove dead copper, pour order 1086): 54 vertices, not listed, extent 1262,70 6899,10776
V1P1V on L12_Bottom Layer "h" (solid, pour order 1082): 2858.26,9060.01 2852.94,9065.33 2852.94,9192.18 2867.18,9206.41 2969.31,9206.41 2986.27,9189.45 2986.27,9068.01 2978.26,9060
VD1P1_ADC1 on L12_Bottom Layer "GNGN" (solid, remove dead copper, pour order 1080): 2813.68,9335.41 2691.24,9335.41 2691.24,9122.55 2667.96,9099.27 2563.3,9099.27 2545.1,9081.08 2545.1,8962.55 2554.24,8953.41 2788.74,8953.41 2804.24,8968.91 2804.24,9216.09 2825.56,9237.41 2825.56,9323.53
VD1P1_ADC2 on L12_Bottom Layer "GNGN" (solid, remove dead copper, pour order 1066): 2881.44,2982 2759,2982 2759,2769.14 2735.72,2745.86 2631.06,2745.86 2612.87,2727.67 2612.87,2609.13 2622,2600 2856.5,2600 2872,2615.5 2872,2862.68 2893.32,2884 2893.32,2970.12
VA_N2P5 on L12_Bottom Layer "12" (solid, pour order 948): 747.59,532.43 747.59,577.43 747.59,591.43 629.59,591.43 620.59,582.43 620.59,545.43 620.59,437.43 628.79,429.23 736.54,429.23 747.47,440.15
VA_N2P5 on L12_Bottom Layer "12" (solid, pour order 967): 749.21,1953.05 749.21,1998.05 749.21,2012.05 631.21,2012.05 622.21,2003.05 622.21,1966.05 622.21,1858.05 630.41,1849.85 738.16,1849.85 749.09,1860.77
VA_N2P5 on L12_Bottom Layer "12" (solid, remove dead copper, pour order 969): 748,6878 748,6923 748,6937 630,6937 621,6928 621,6891 621,6783 629.19,6774.81 736.94,6774.8 747.87,6785.72
GND on L12_Bottom Layer "GNGN" (solid, remove dead copper, pour order 975): 35 vertices, not listed, extent 3576,11141.57 4310.89,11591.18
GND on L12_Bottom Layer "GNGN" (solid, remove dead copper, pour order 974): 37 vertices, not listed, extent 2726.99,11137.44 3525.18,11587.05
GND on L12_Bottom Layer "GNGN" (solid, remove dead copper, pour order 973): 37 vertices, not listed, extent 1859.99,11137.39 2658.19,11587
GND on L12_Bottom Layer "GNGN" (solid, remove dead copper, pour order 972): 1141.23,11376.2 1119.68,11376.2 1073.2,11376.2 1038,11341 1038,11144.09 1053.09,11129 1146,11129 1163,11146 1163,11357.05 1179.95,11373.99 1226.99,11373.99 1232.74,11379.74 1232.74,11404.16 1228.39,11408.51 1173.53,11408.51
GND on L12_Bottom Layer "GNGN" (solid, remove dead copper, pour order 971): 31 vertices, not listed, extent 1168,11135.04 1819,11587
12VIN on L12_Bottom Layer "GNGN" (solid, pour order 938): 4092.72,11492.13 4098.72,11498.13 4211.98,11498.13 4215.97,11494.14 4215.97,11390.77 4210.2,11385 4095.79,11385 4092.58,11388.21
NetC538_1 on L12_Bottom Layer "12" (solid, pour order 911): 2124.2,11296.16 2101.16,11296.16 2099,11294 2099,11265.62 2093.65,11260.28 2040.31,11260.28 2034,11266.59 2034,11291.35 1949.53,11291.35 1949.53,11207.52 1949.52,11143.24 1957.94,11134.82 2113.99,11134.82 2124.2,11145.03 2124.2,11290.82
NetC495_1 on L12_Bottom Layer "12" (solid, pour order 908): 2991.2,11296.2 2968.15,11296.2 2966,11294.05 2966,11265.67 2960.65,11260.32 2907.31,11260.32 2901,11266.64 2901,11291.39 2816.52,11291.39 2816.52,11207.57 2816.52,11143.29 2824.94,11134.87 2980.99,11134.87 2991.2,11145.07 2991.2,11290.87
NetC647_1 on L12_Bottom Layer "12" (solid, pour order 905): 21 vertices, not listed, extent 1199.9,11135.04 1424.41,11296.37
VA_N2P5 on L12_Bottom Layer "12" (solid, pour order 854): 743.2,8298.13 743.2,8343.13 743.2,8357.13 625.2,8357.13 616.2,8348.13 616.2,8311.13 616.2,8203.13 624.4,8194.93 732.15,8194.93 743.08,8205.85
V3P3_IN on L12_Bottom Layer "V" (solid, pour order 834): 3393,10300 3393,10414 3398,10419 3878,10419 3893,10404 3893,10301 3881,10289 3404,10289 3393,10300
GND on L12_Bottom Layer "V" (solid, pour order 833): 2696,10408 2696,10705 2720,10729 2721.64,10730.64 2817.51,10730.64 2850.67,10730.64 2861,10720.3 2861,10423 2861,10408 2861,10301 2851,10291 2712,10291 2696,10307
V1P9V_IN on L12_Bottom Layer "V" (solid, pour order 832): 2901,10288 2891,10298 2891,10414 2929,10452 3152,10452 3162,10442 3162,10301 3149,10288
V1P1V_IN on L12_Bottom Layer "V" (solid, pour order 831): 2405,10288 2392,10301 2392,10434 2410,10452 2655,10452 2664,10443 2664,10302 2650,10288
DGND on L12_Bottom Layer "V" (solid, pour order 811): 3219,10255 3344,10255 3360,10239 3360,10001 3349,9990 3207,9990 3195,10002 3195,10221 3195,10245 3205,10255
DGND on L12_Bottom Layer "V" (solid, pour order 810): 2719,10255 2844,10255 2860,10239 2860,10001 2849,9990 2707,9990 2695,10002 2695,10221 2695,10245 2705,10255
DGND on L12_Bottom Layer "V" (solid, pour order 809): 2119,10255 2344,10255 2360,10239 2360,9998 2352,9990 2107,9990 2095,10002 2095,10221 2095,10245 2105,10255
V3P3_LMK61E2 on L12_Bottom Layer "L1_Top Layer-No Net" (solid, pour order 785): 5854,5285 5844,5295 5844,5452 5855,5463 6028,5463 6038,5453 6038,5300 6023,5285
DGND on L12_Bottom Layer "L1_Top Layer-No Net" (solid, pour order 784): 5810,5448 5703,5448 5691,5436 5691,5298 5702,5287 5807,5287 5817,5297 5817,5441
DGND on L12_Bottom Layer "L1_Top Layer-No Net" (solid, pour order 783): 5606,5715 5606,5560 5615,5551 5667,5551 5673,5557 5673,5731 5666,5738 5618,5738 5606,5726
NetC414_2 on L12_Bottom Layer "L1_Top Layer-No Net" (solid, pour order 782): 20 vertices, not listed, extent 5481,5542 5592,5770
VA1P1_ADC1 on L12_Bottom Layer "V" (solid, remove dead copper, pour order 767): 17 vertices, not listed, extent 2054.93,8436 2366.67,8576
VA1P9_ADC1 on L12_Bottom Layer "V" (solid, pour order 766): 2256.67,7836 2171.67,7836 2166.67,7841 2161.67,7846 2161.67,7941 2161.67,8029.27 2173.39,8041 2188.36,8041 2198.36,8031 2203.36,8026 2236.67,8026 2276.67,8026 2281.67,8021 2281.67,7856 2261.67,7836
VA1P9_ADC2 on L12_Bottom Layer "V" (solid, pour order 765): 2260,1490 2175,1490 2170,1495 2165,1500 2165,1595 2165,1690 2170,1695 2191.69,1695 2201.69,1685 2206.69,1680 2240,1680 2280,1680 2285,1675 2285,1510 2265,1490
VA1P1_ADC2 on L12_Bottom Layer "V" (solid, pour order 764): 17 vertices, not listed, extent 2058.26,2090 2370,2230
V1P1V on L12_Bottom Layer "h" (solid, pour order 726): 2926.03,2706.6 2920.71,2711.92 2920.71,2838.76 2934.94,2853 3037.07,2853 3054.03,2836.04 3054.03,2714.59 3046.03,2706.59
AGND on L12_Bottom Layer "V" (solid, pour order 737): 741.97,8483.83 741.97,8593.83 731.97,8603.83 631.97,8603.83 621.97,8593.83 621.97,8388.83 631.97,8378.83 686.97,8378.83 696.97,8388.83 696.97,8438.83
VA_N2P5_LMH5401_1 on L12_Bottom Layer "V" (solid, pour order 738): 776.63,8301.83 984.31,8301.83 1000.98,8318.5 1000.98,8575.02 984.17,8591.83 774.46,8591.83 764.46,8581.83 764.46,8466.83 764.46,8313.99
VA_N2P5_LMH5401_2 on L12_Bottom Layer "V" (solid, pour order 747): 780.22,6880.57 992.63,6880.57 1006,6893.95 1006,7159.82 995.24,7170.58 778.06,7170.57 768.06,7160.57 768.06,7045.57 768.06,6892.74
AGND on L12_Bottom Layer "V" (solid, pour order 749): 745.56,7062.57 745.56,7172.57 735.56,7182.57 635.56,7182.57 625.56,7172.57 625.56,6967.57 635.56,6957.57 690.56,6957.57 700.56,6967.57 700.56,7017.57
VA_N2P5_LMH5401_3 on L12_Bottom Layer "V" (solid, pour order 756): 782.53,1956.32 984.4,1956.32 1002.39,1974.31 1002.39,2228.85 984.91,2246.33 780.37,2246.32 770.37,2236.32 770.37,2121.32 770.37,1968.49
AGND on L12_Bottom Layer "V" (solid, pour order 757): 747.88,2138.32 747.88,2248.32 737.88,2258.32 637.88,2258.32 627.88,2248.32 627.88,2043.32 637.88,2033.32 692.88,2033.32 702.88,2043.32 702.88,2093.32
VA_N2P5_LMH5401_4 on L12_Bottom Layer "V" (solid, pour order 761): 781.99,535.37 989.79,535.37 1005.85,551.43 1005.85,812.54 993.02,825.37 779.83,825.37 769.83,815.37 769.83,700.37 769.83,547.53
AGND on L12_Bottom Layer "V" (solid, pour order 762): 747.33,717.37 747.33,827.37 737.33,837.37 637.33,837.37 627.33,827.37 627.33,622.37 637.33,612.37 692.33,612.37 702.33,622.37 702.33,672.37
NetJ55_1 on L12_Bottom Layer "V" (solid, pour order 770): 18 vertices, not listed, extent 5684,10946.07 6434,11269.07
V3P3_LMK00304 on L12_Bottom Layer "L1_Top Layer-No Net" (solid, pour order 775): 3024,4446 2862.63,4446 2850.63,4458 2850.63,4543.63 2859,4552 2882,4552 2896,4566 2896,4684 2910,4698 3029,4698 3043,4684 3043,4465 3024,4446
DGND on L12_Bottom Layer "L1_Top Layer-No Net" (solid, pour order 776): 3034,4422 2796,4422 2786,4412 2786,4367 2791,4362 3031,4362 3044,4375 3044,4412 3034,4422
GND on L12_Bottom Layer "V" (solid, pour order 786): 2837,10291 2712,10291 2696,10307 2696,10408 2707,10419 2853,10419 2861,10411 2861,10325 2861,10301 2851,10291
V1P1V on L12_Bottom Layer "V" (solid, pour order 790): 2520,10255 2645,10255 2661,10239 2661,10002 2649,9990 2403,9990 2392.99,10000 2393,10248 2400,10255
V1P9V on L12_Bottom Layer "V" (solid, pour order 791): 3019,10255 3144,10255 3160,10239 3160,10002 3148,9990 2902,9990 2891.99,10000 2892,10248 2899,10255
V3P3 on L12_Bottom Layer "V" (solid, pour order 794): 3519,10255 3644,10255 3660,10239 3660,10002 3648,9990 3402,9990 3391.99,10000 3392,10248 3399,10255
VA2P5 on L12_Bottom Layer "V" (solid, remove dead copper, pour order 795): 1663,10255 1788,10255 1804,10239 1804,10002 1792,9990 1546,9990 1535.99,10000 1536,10248 1543,10255
VA_N2P5 on L12_Bottom Layer "V" (solid, pour order 798): 862,10255 987,10255 1003,10239 1003,10002 991,9990 745,9990 734.99,10000 735,10248 742,10255
NetC510_1 on L12_Bottom Layer "V" (solid, pour order 799): 703,11326.92 965,11326.92 972,11333.92 972,11374.92 921,11425.92 921,11503.92 909,11515.92 831,11515.92 820,11504.92 820,11405.92 812,11397.92 706,11397.92 693,11384.92 693,11332.92 699,11326.92
NetC695_2 on L12_Bottom Layer "V" (solid, pour order 800): 31 vertices, not listed, extent 315,11039.67 773.63,11587
GND on L12_Bottom Layer "V" (solid, pour order 801): 30 vertices, not listed, extent 511,11042.92 975,11315.92
NetC509_1 on L12_Bottom Layer "V" (solid, pour order 802): 1553.81,11338.82 1571.13,11356.14 1571.13,11496.06 1559.05,11508.14 1505.05,11508.14 1491.05,11494.14 1491.05,11422.14 1478.05,11409.14 1417.14,11409.14 1399.05,11391.05 1399.05,11338.82
12VIN on L12_Bottom Layer "V" (solid, pour order 803): 2360,11491 2360,11399.65 2374.65,11385 2518.93,11385 2527,11393.07 2527,11485 2516,11496 2365,11496
NetC364_1 on L12_Bottom Layer "V" (solid, pour order 804): 2112.84,11326.92 2241.92,11326.92 2270.92,11355.92 2270.92,11486.08 2261,11496 2199.91,11496 2190.84,11486.92 2190.84,11421.92 2177.84,11408.92 2112.84,11408.92 2098.84,11394.92 2098.84,11330.92 2102.84,11326.92
NetC355_1 on L12_Bottom Layer "V" (solid, pour order 805): 3122.95,11341 3137.92,11355.97 3137.92,11488.08 3130,11496 3069,11496 3057.84,11484.84 3057.84,11421.97 3044.84,11408.97 2979.84,11408.97 2965.84,11394.97 2965.84,11341
NetC371_1 on L12_Bottom Layer "V" (solid, pour order 806): 3972.46,11345.63 3986.93,11360.1 3986.93,11490.07 3981,11496 3911.74,11496 3906.84,11491.1 3906.84,11426.1 3893.84,11413.1 3832.83,11413.1 3814.84,11395.11 3814.84,11345.63
V1P1V on L12_Bottom Layer "V" (solid, pour order 818): 2014,8735 1981,8702 1981,8612 1988,8605 2071,8605 2079,8613 2079,8665 2084,8670 2128,8670 2137,8679 2137,8730 2132,8735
